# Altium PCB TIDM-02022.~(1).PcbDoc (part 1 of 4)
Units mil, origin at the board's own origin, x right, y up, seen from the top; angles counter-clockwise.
Board outline 1448.82 x 2299.21 mil, 16 copper layers (Top Layer, GND1, PWR1, PWR2, PWR3, GND2, GND3/SIG1, SIG2, SIG3, GND3/SIG4, GND5, PWR4, PWR5, GND6, GND7, Bottom Layer), stack 148.806 mil thick; 257 components, 138 nets, 739 pads, 1147 vias.

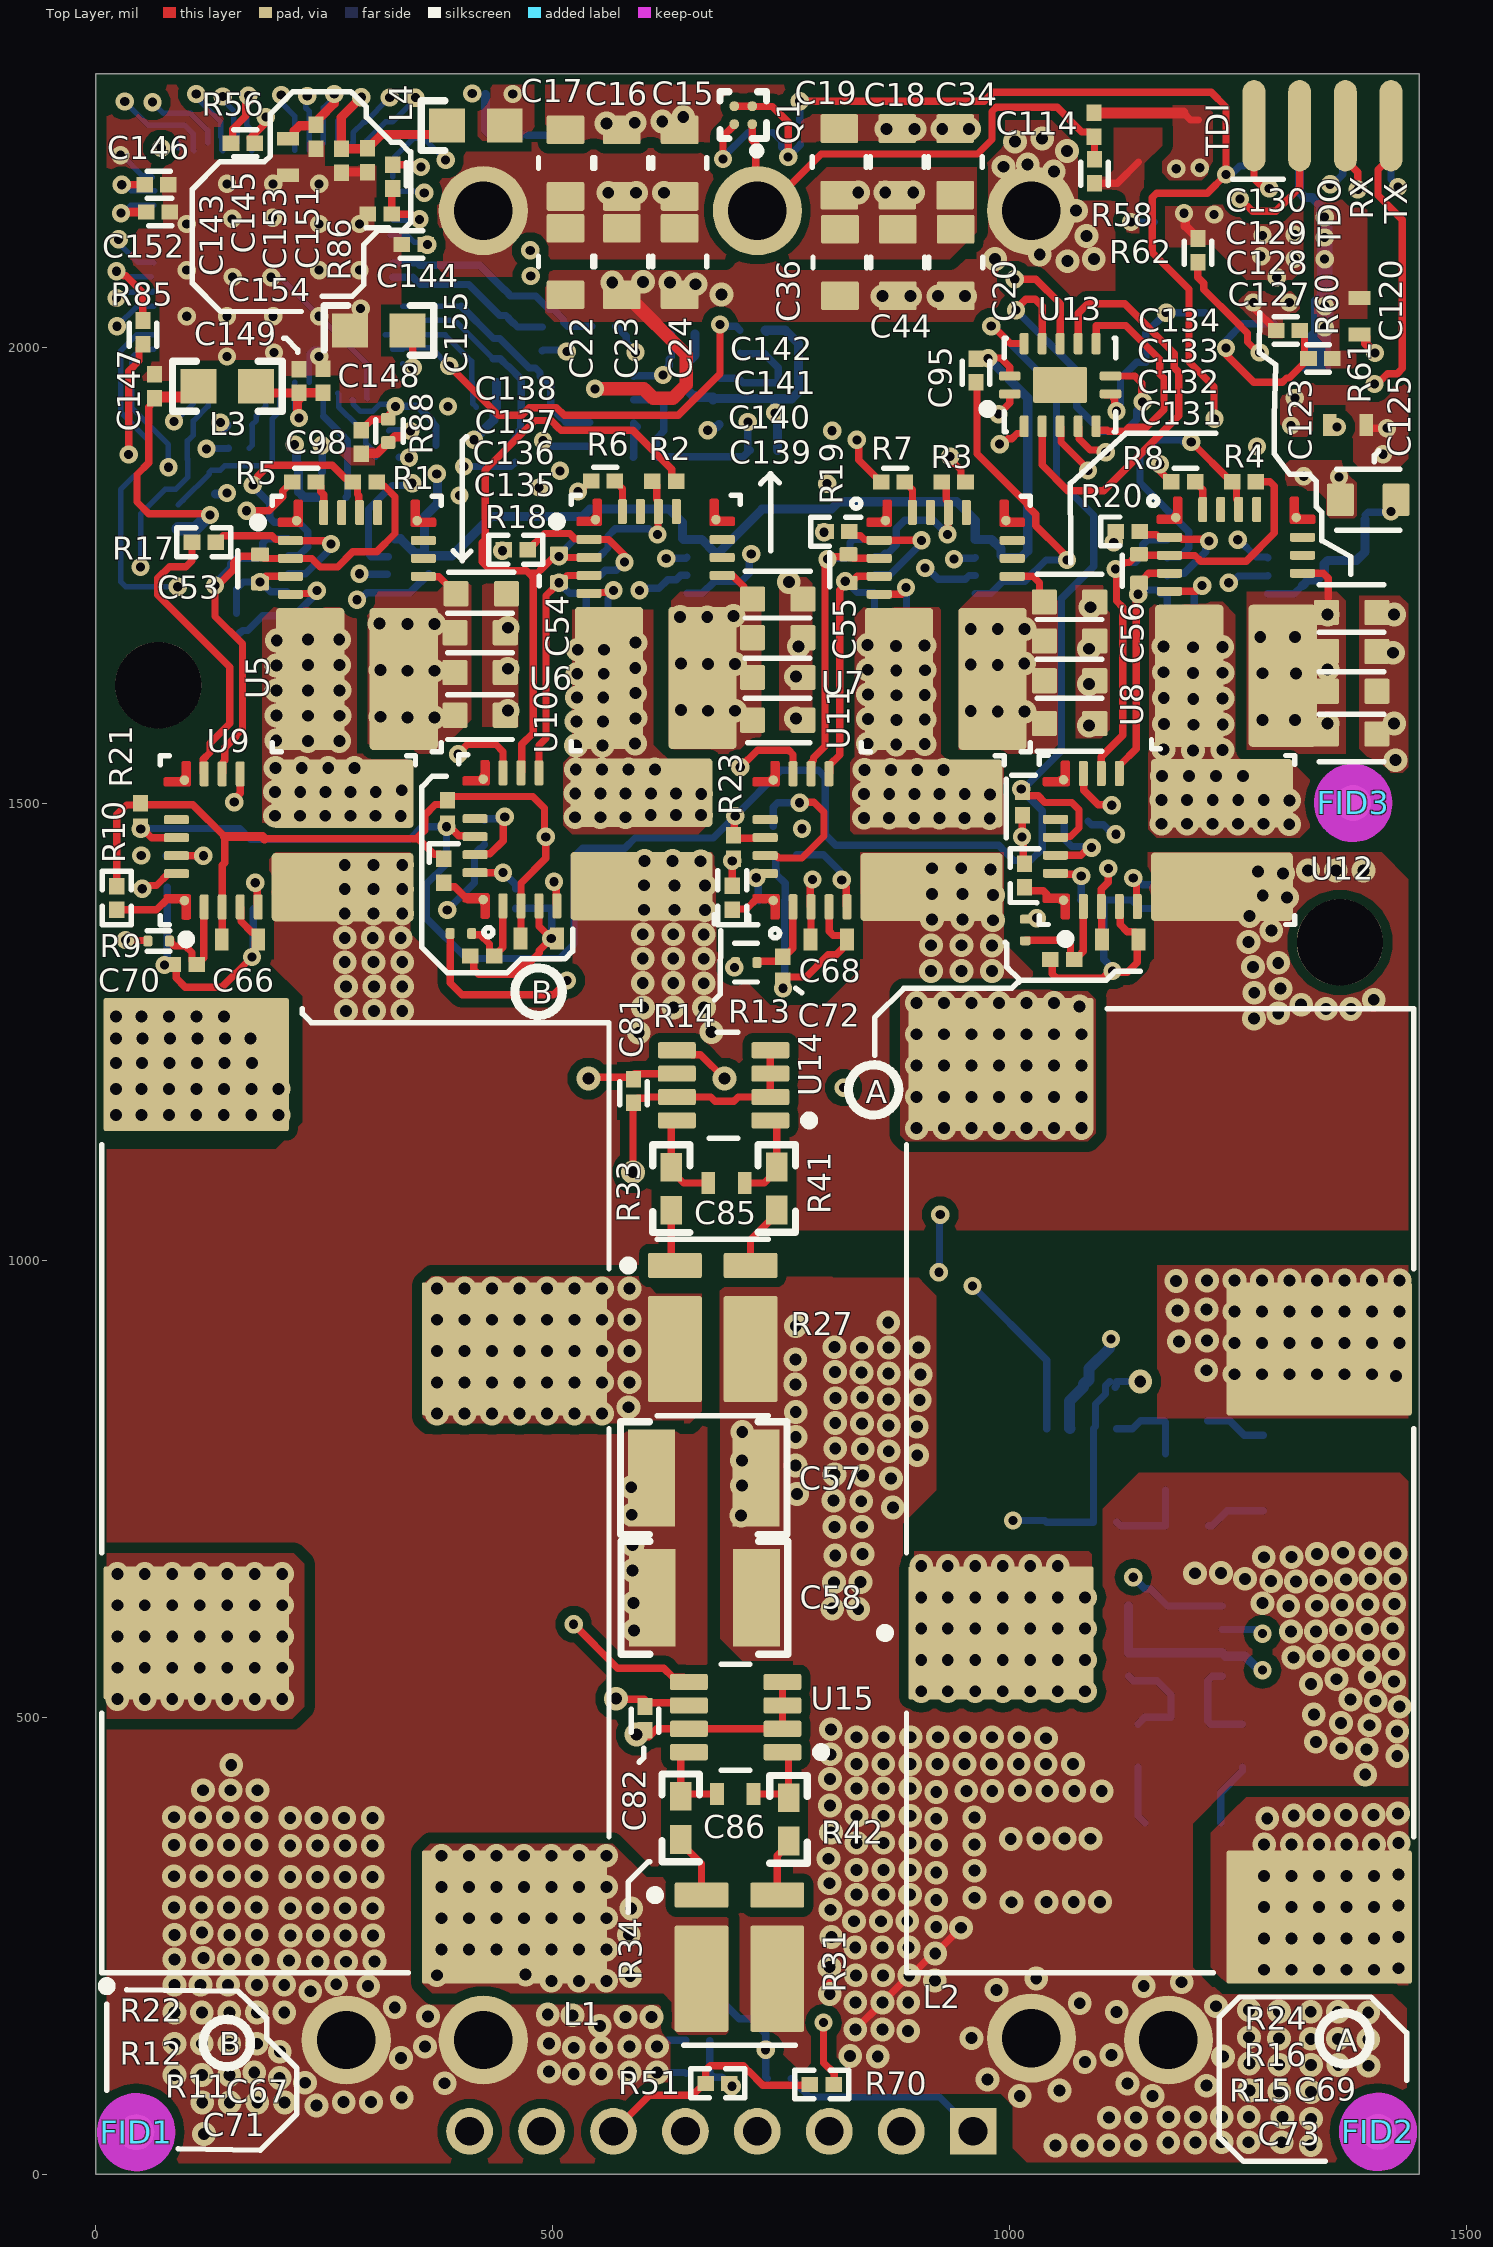
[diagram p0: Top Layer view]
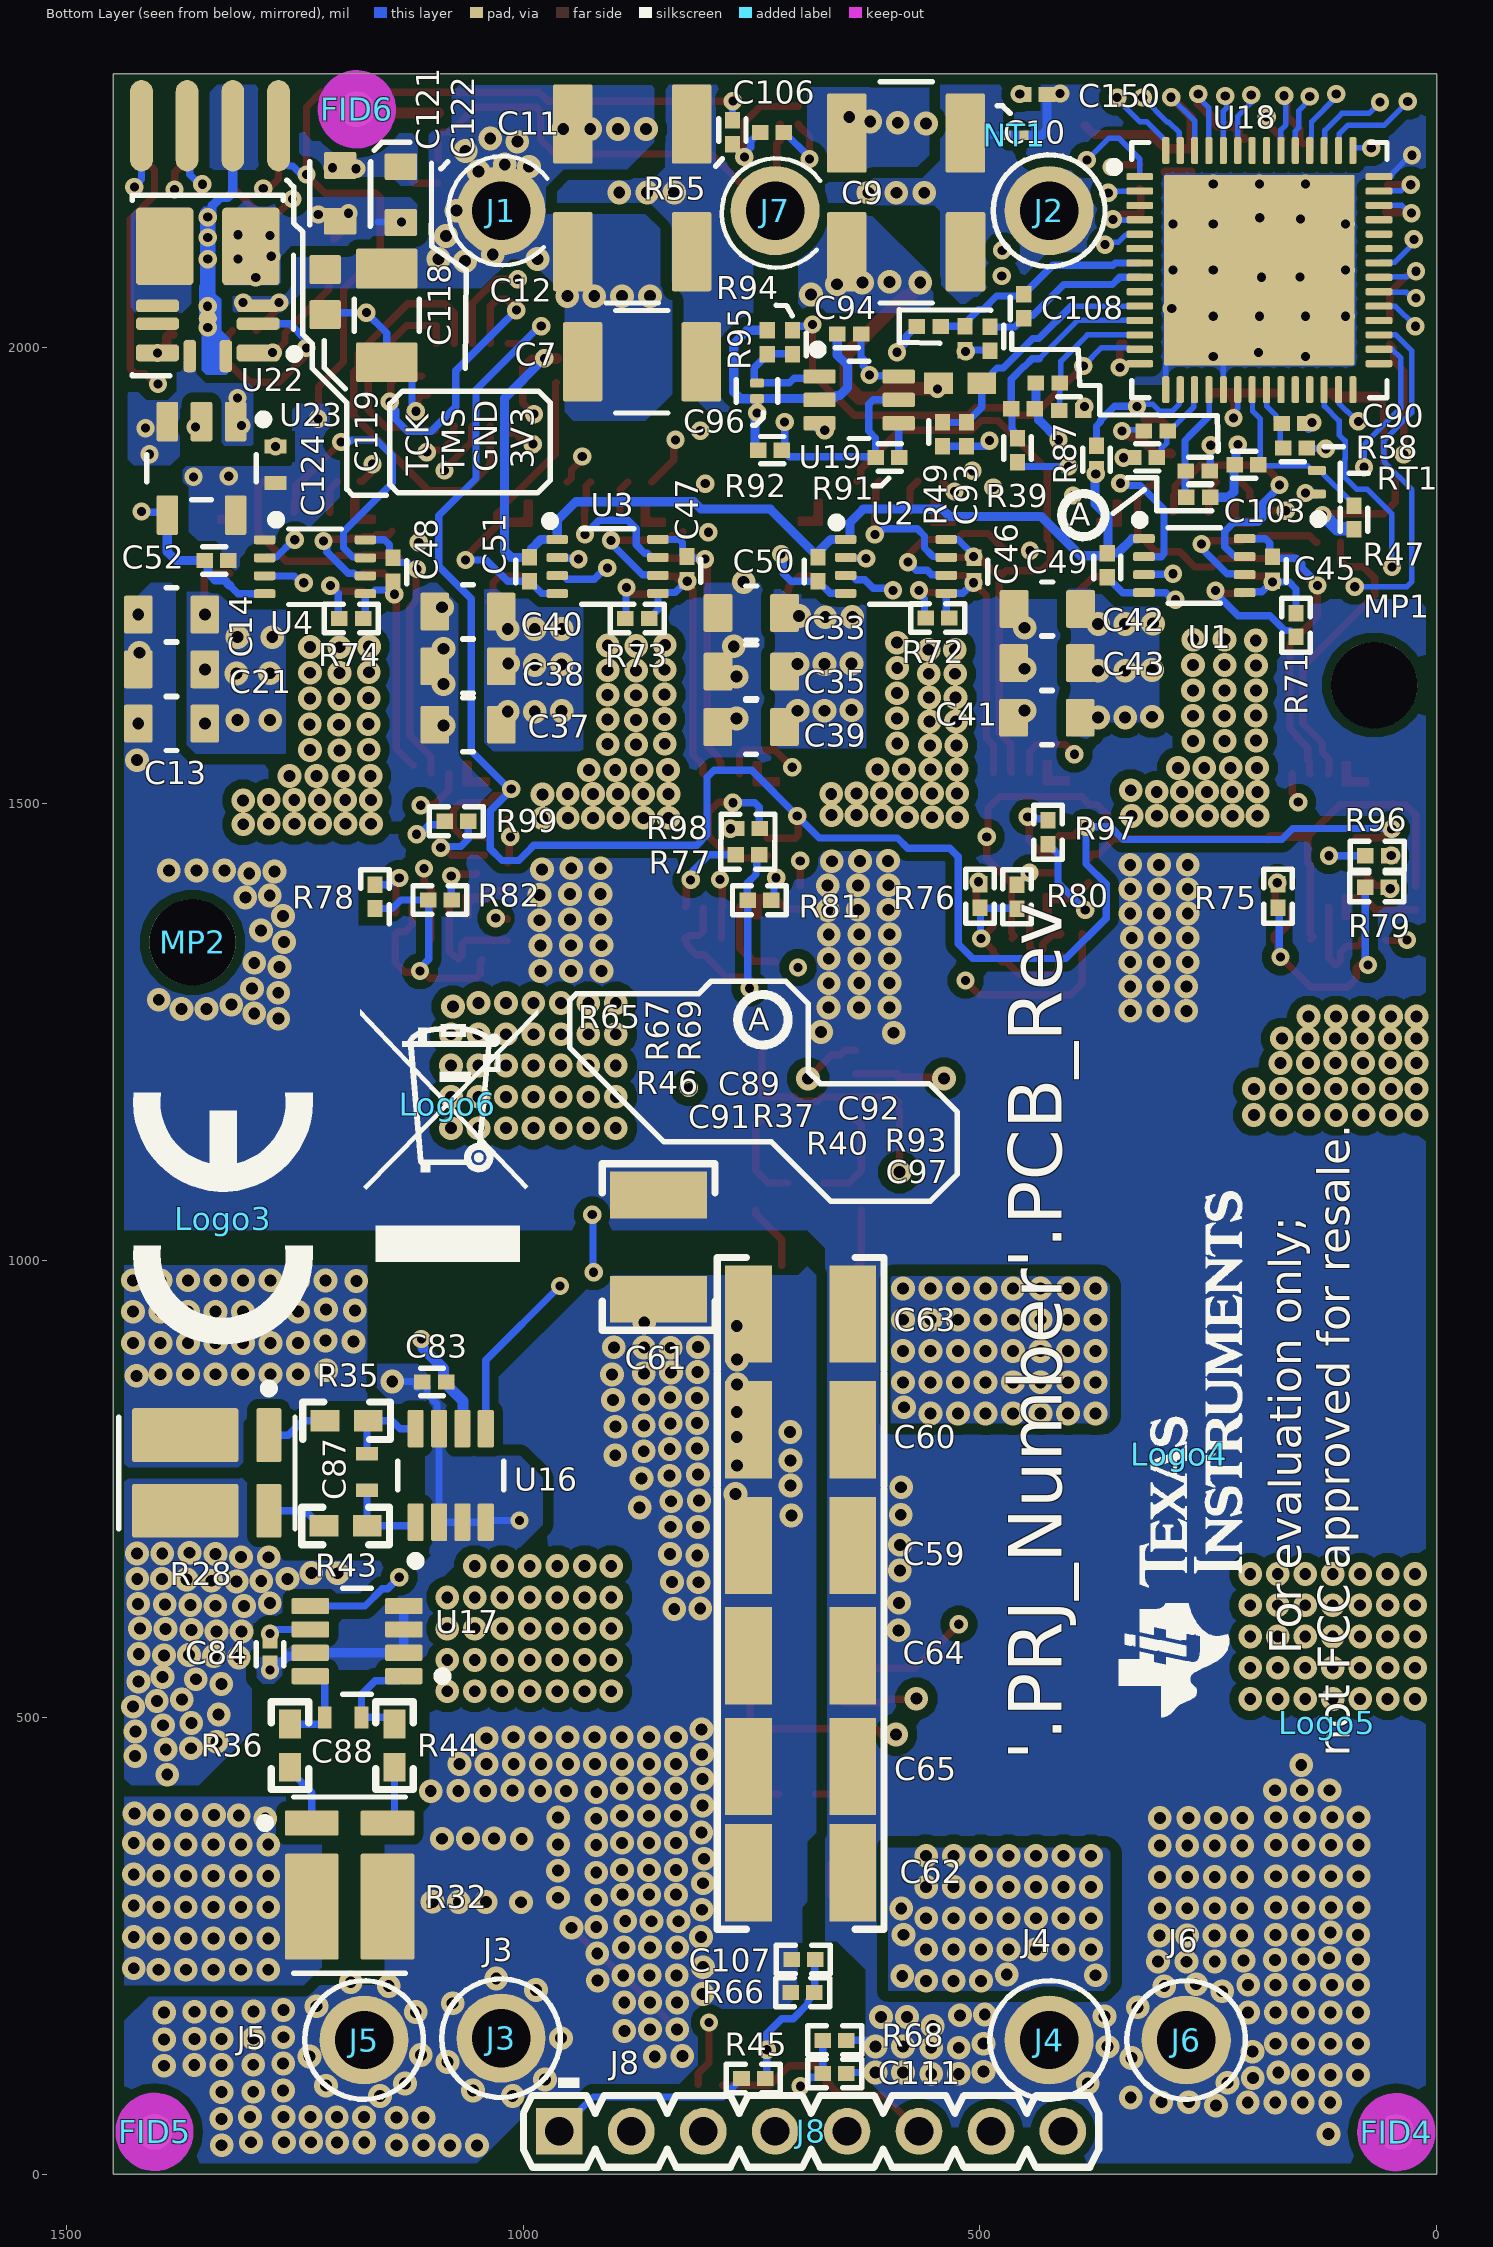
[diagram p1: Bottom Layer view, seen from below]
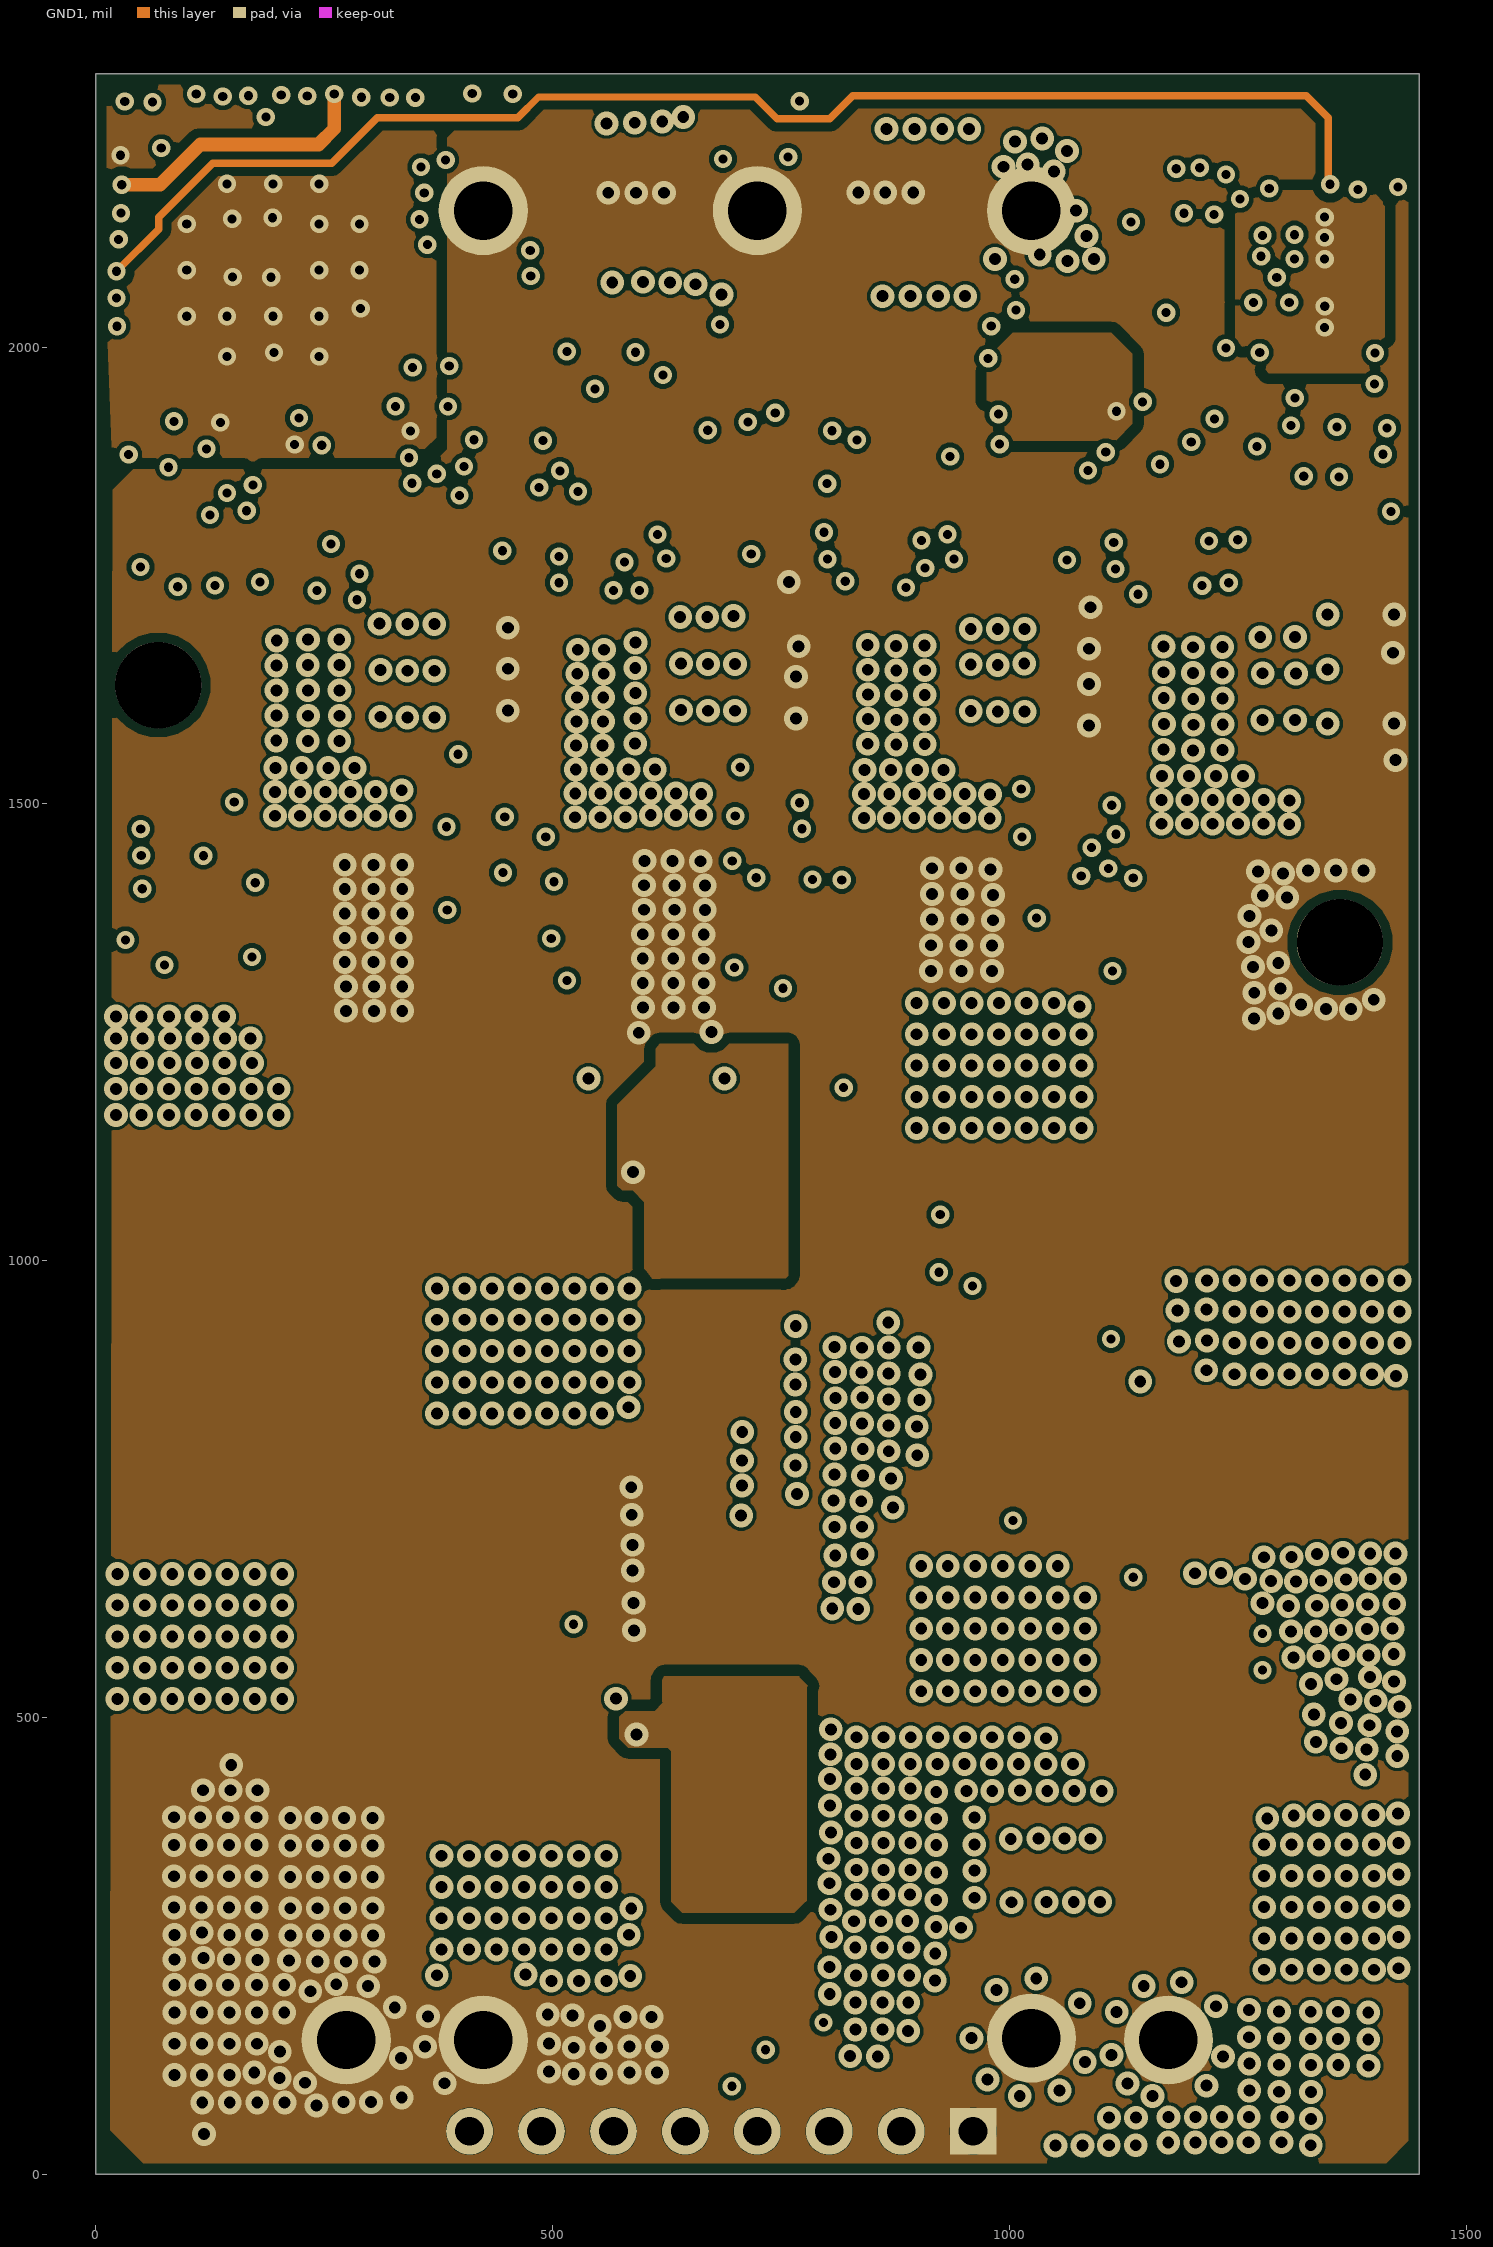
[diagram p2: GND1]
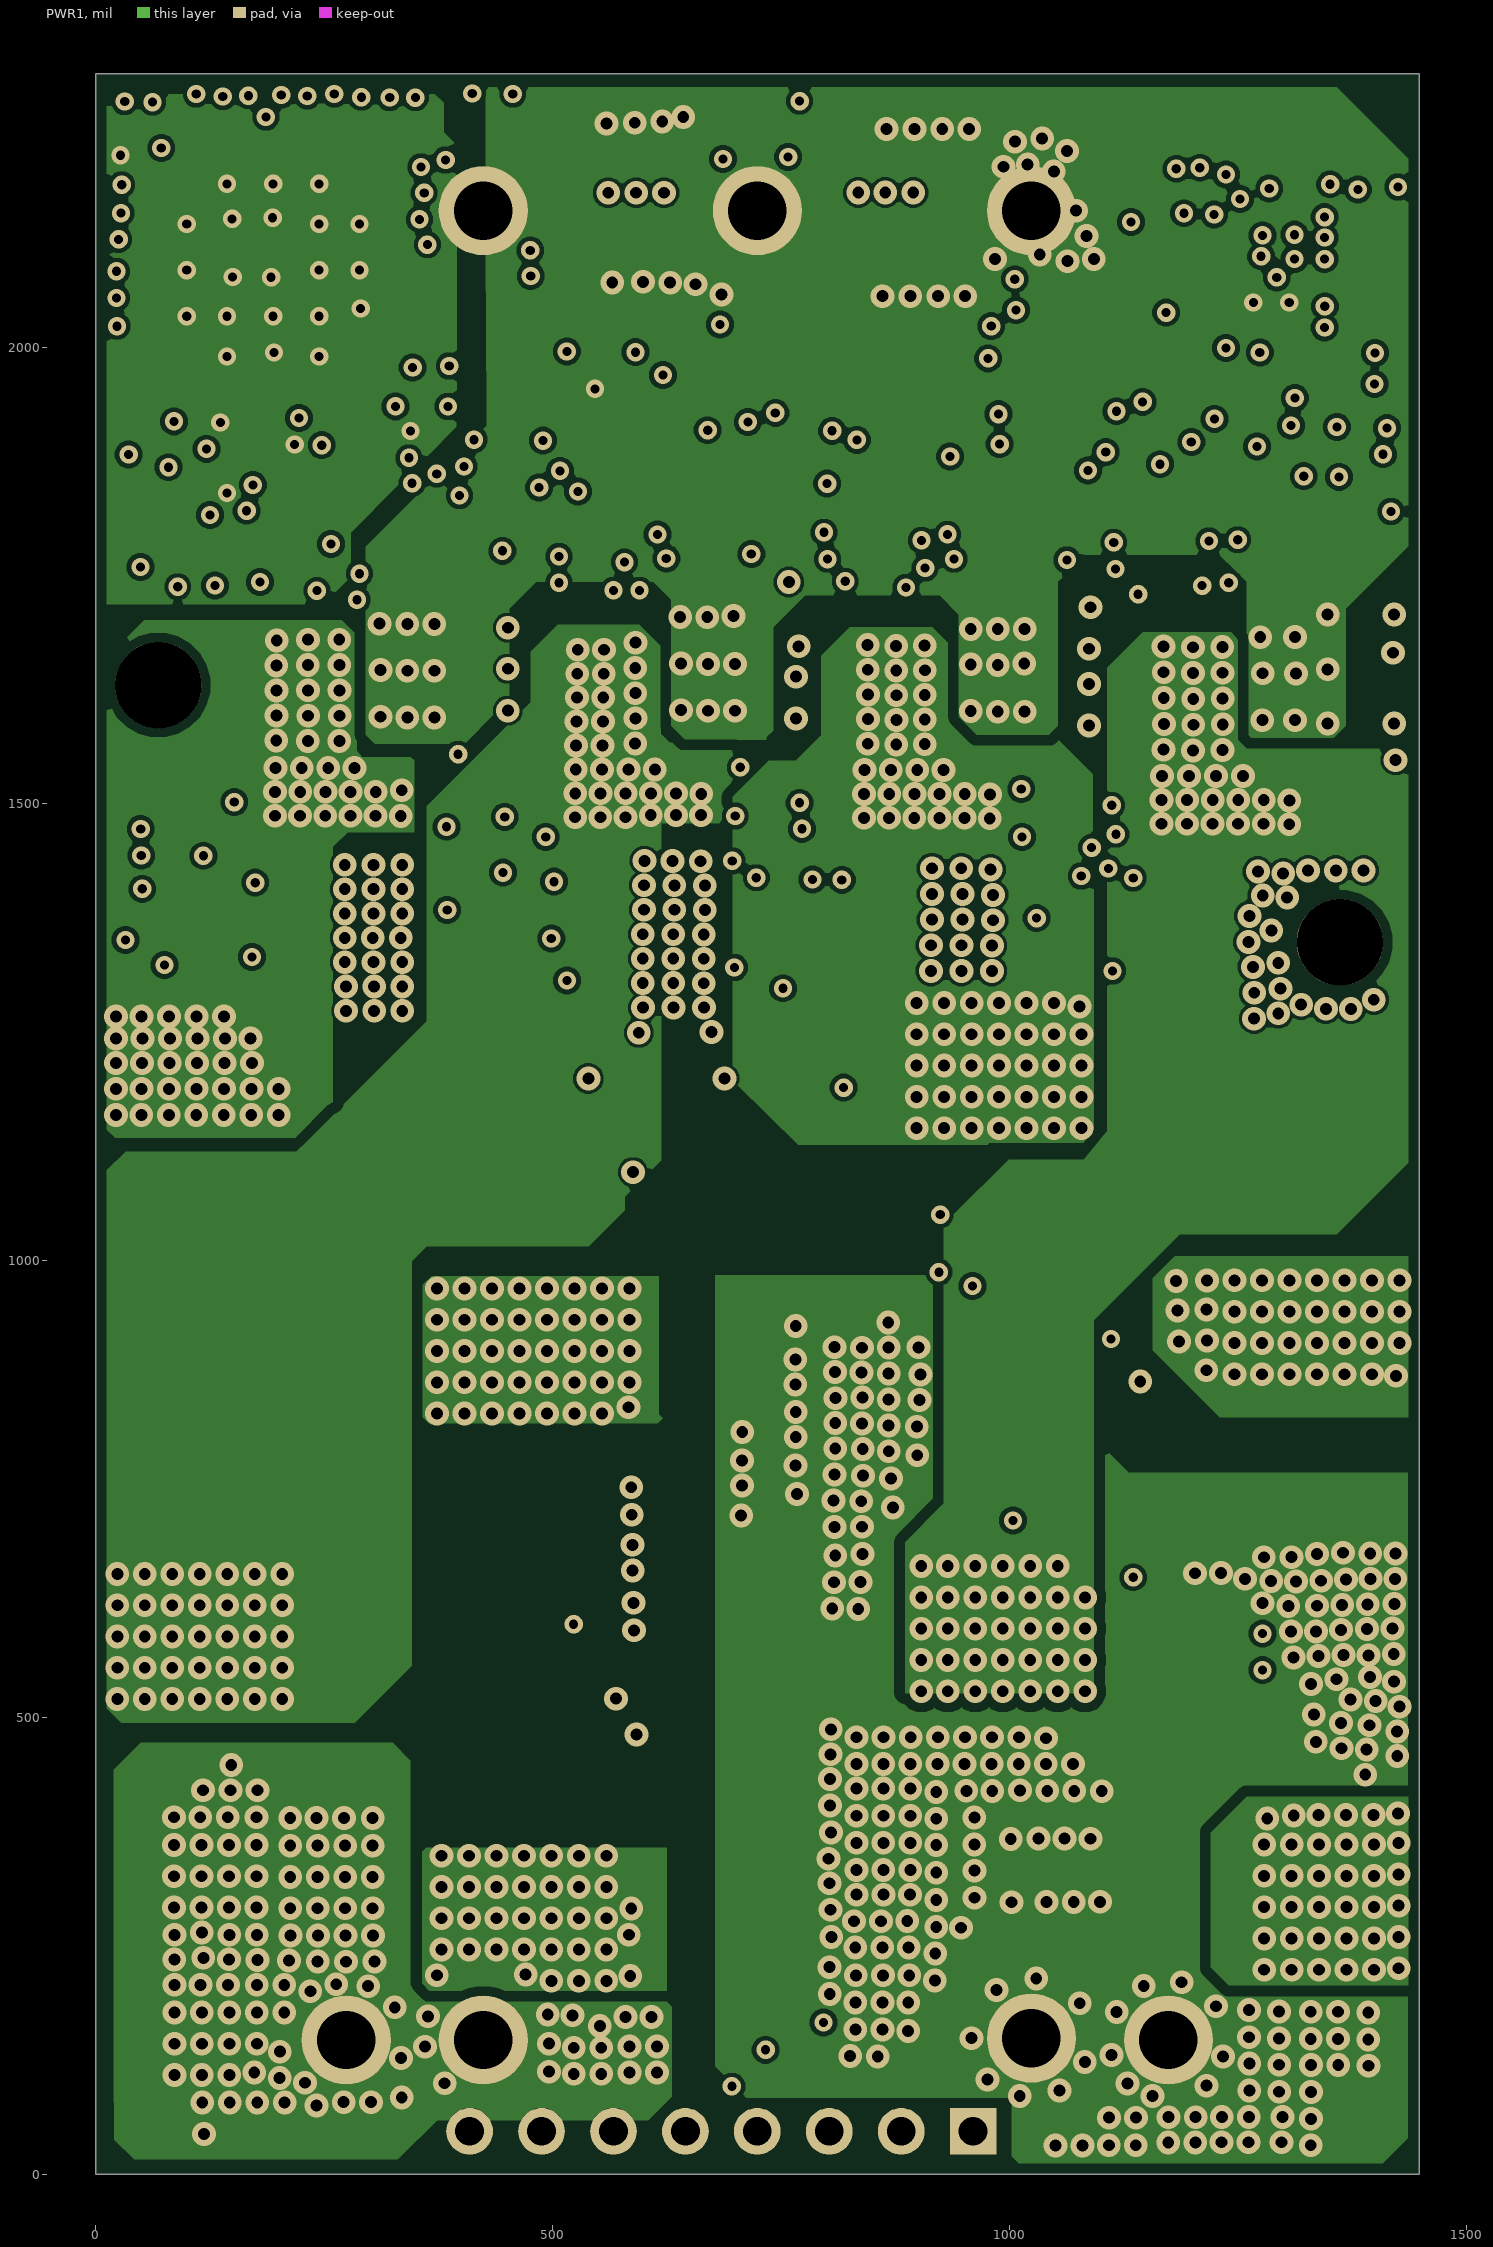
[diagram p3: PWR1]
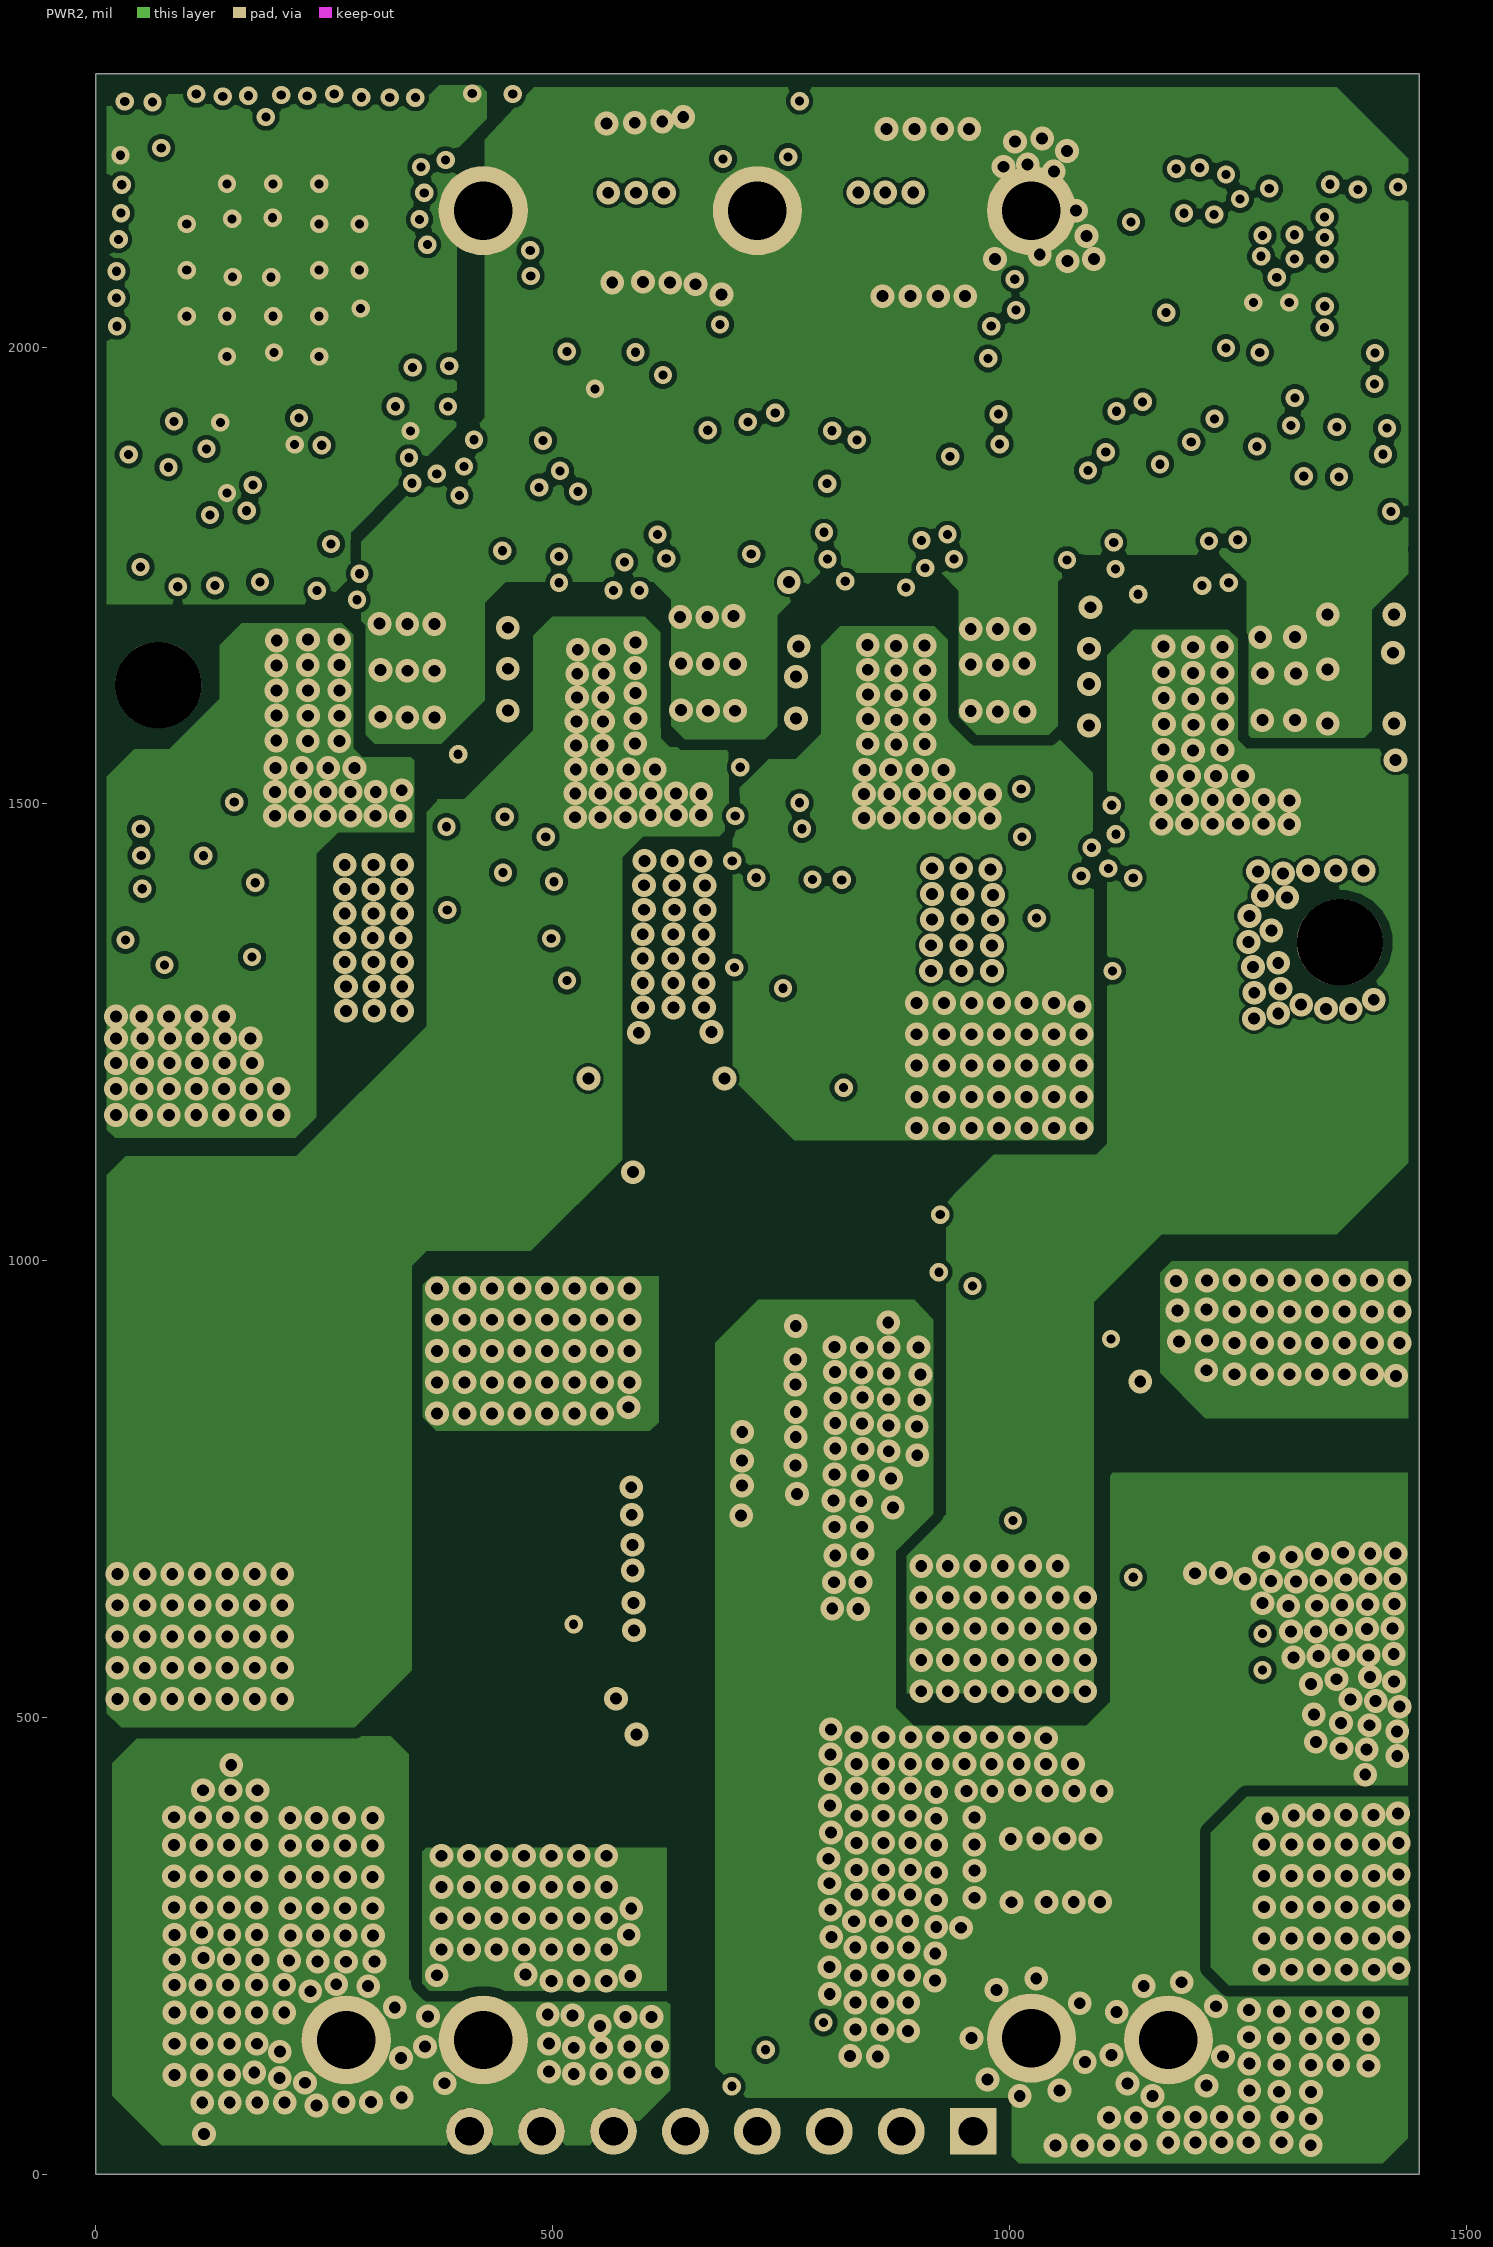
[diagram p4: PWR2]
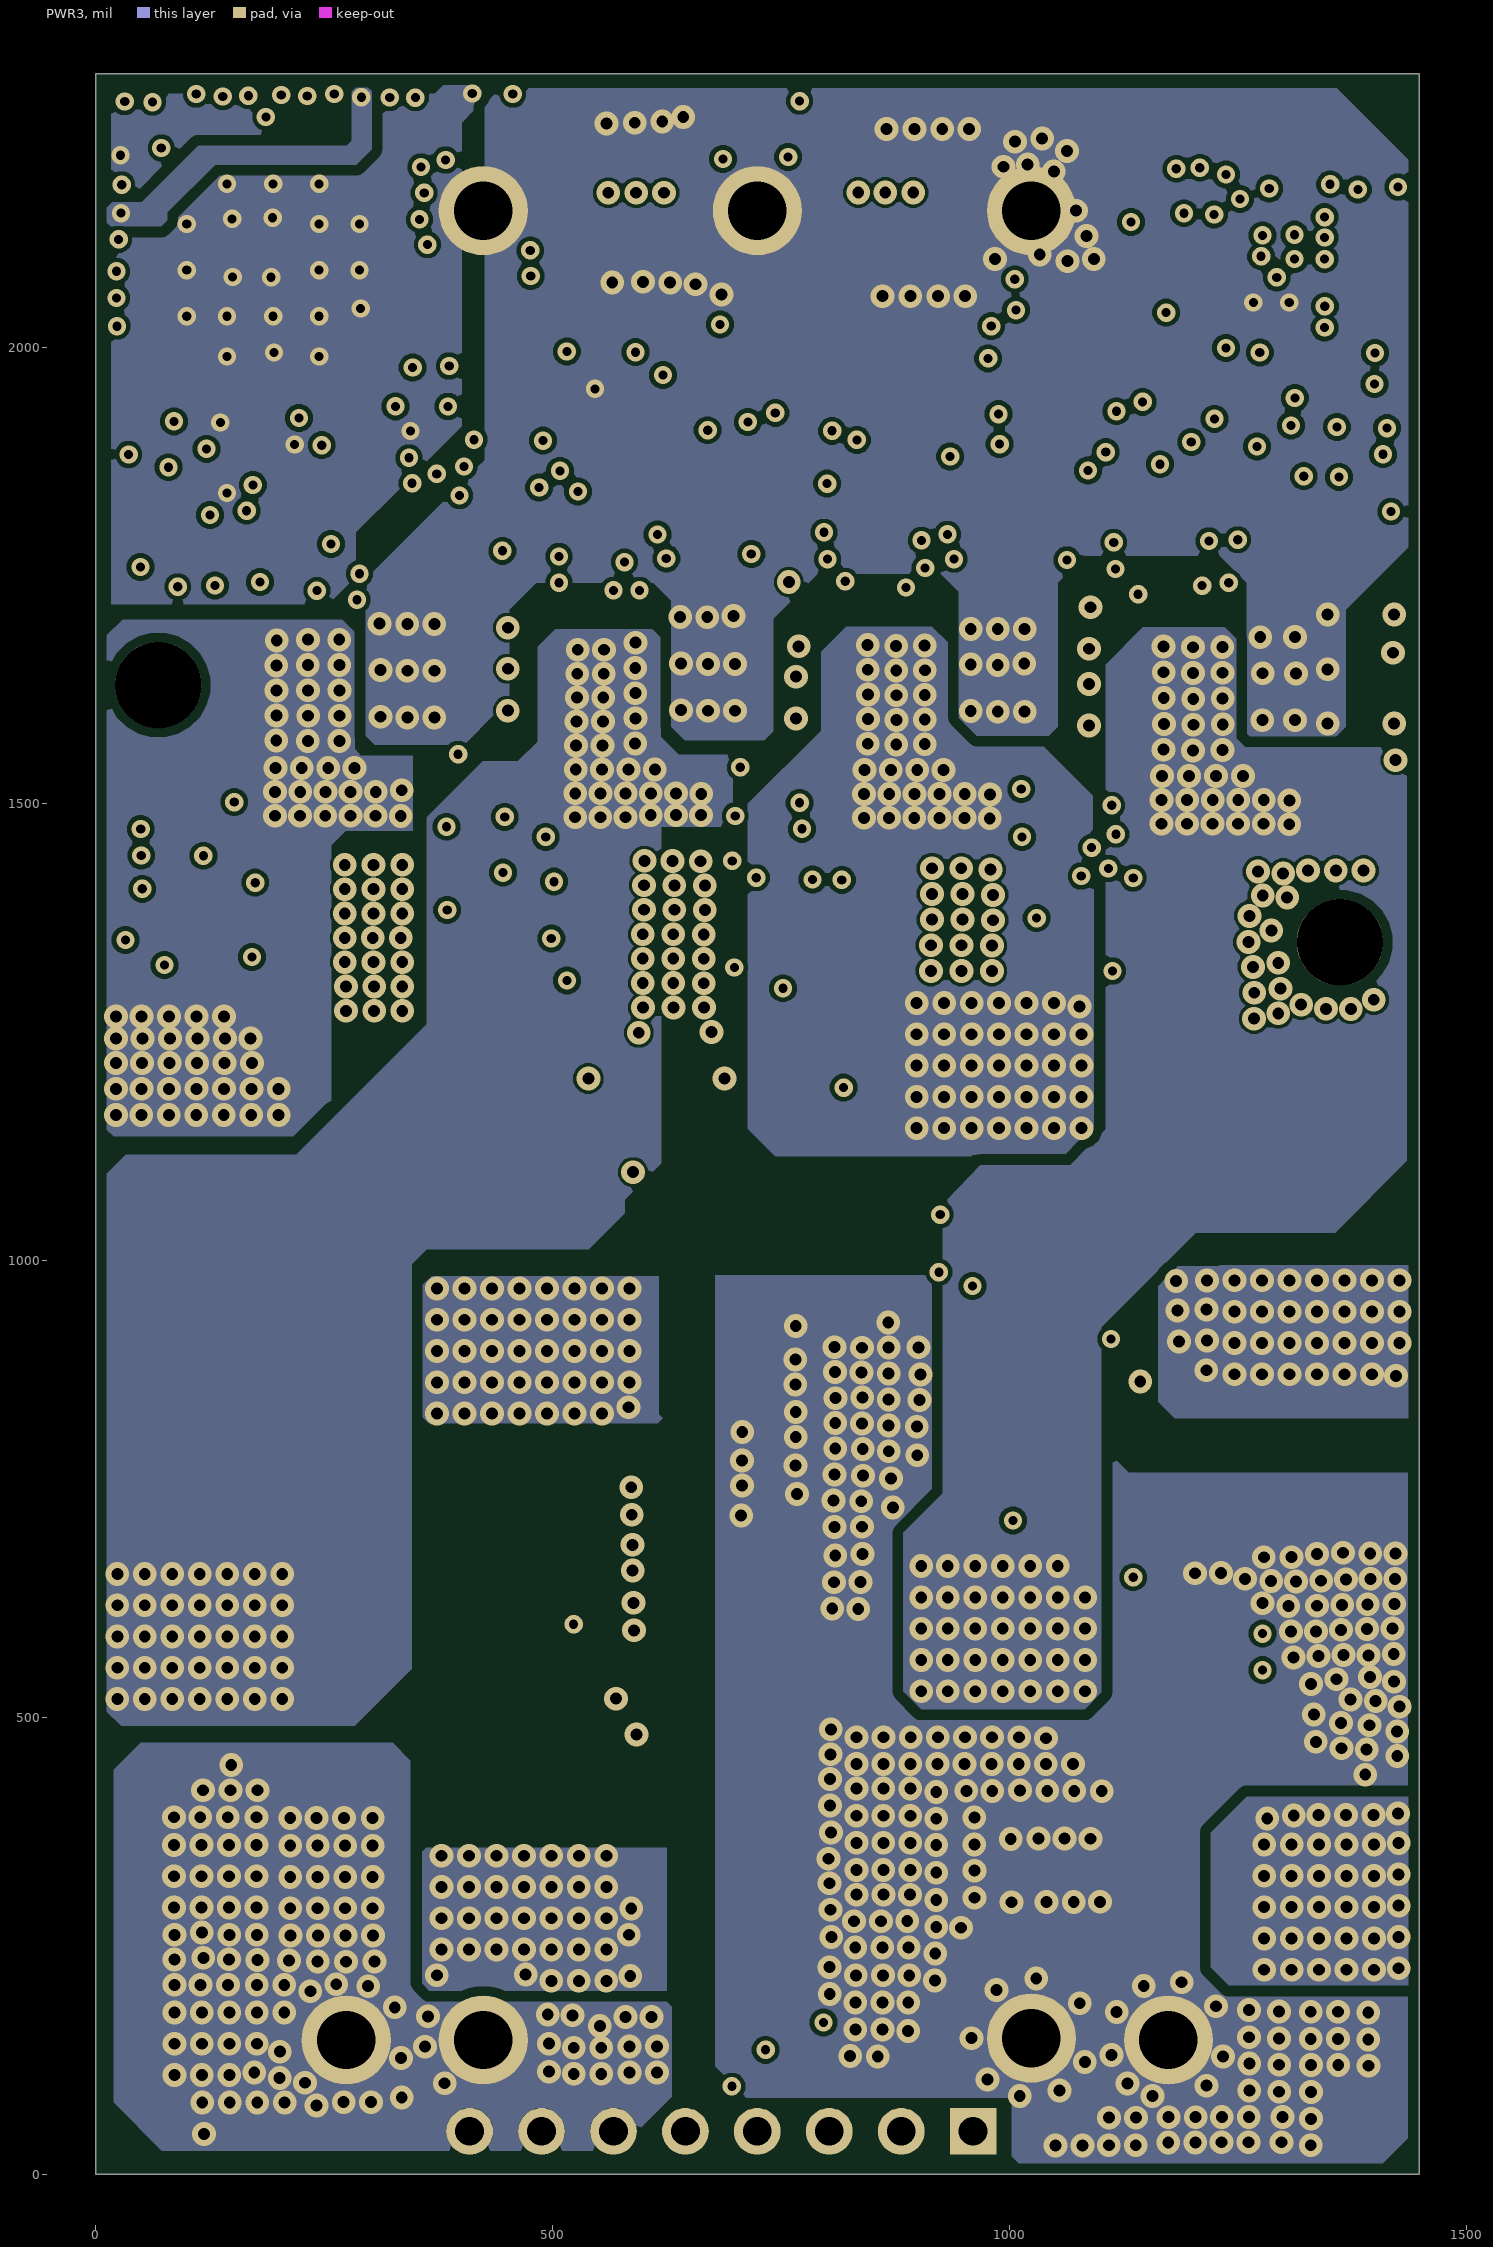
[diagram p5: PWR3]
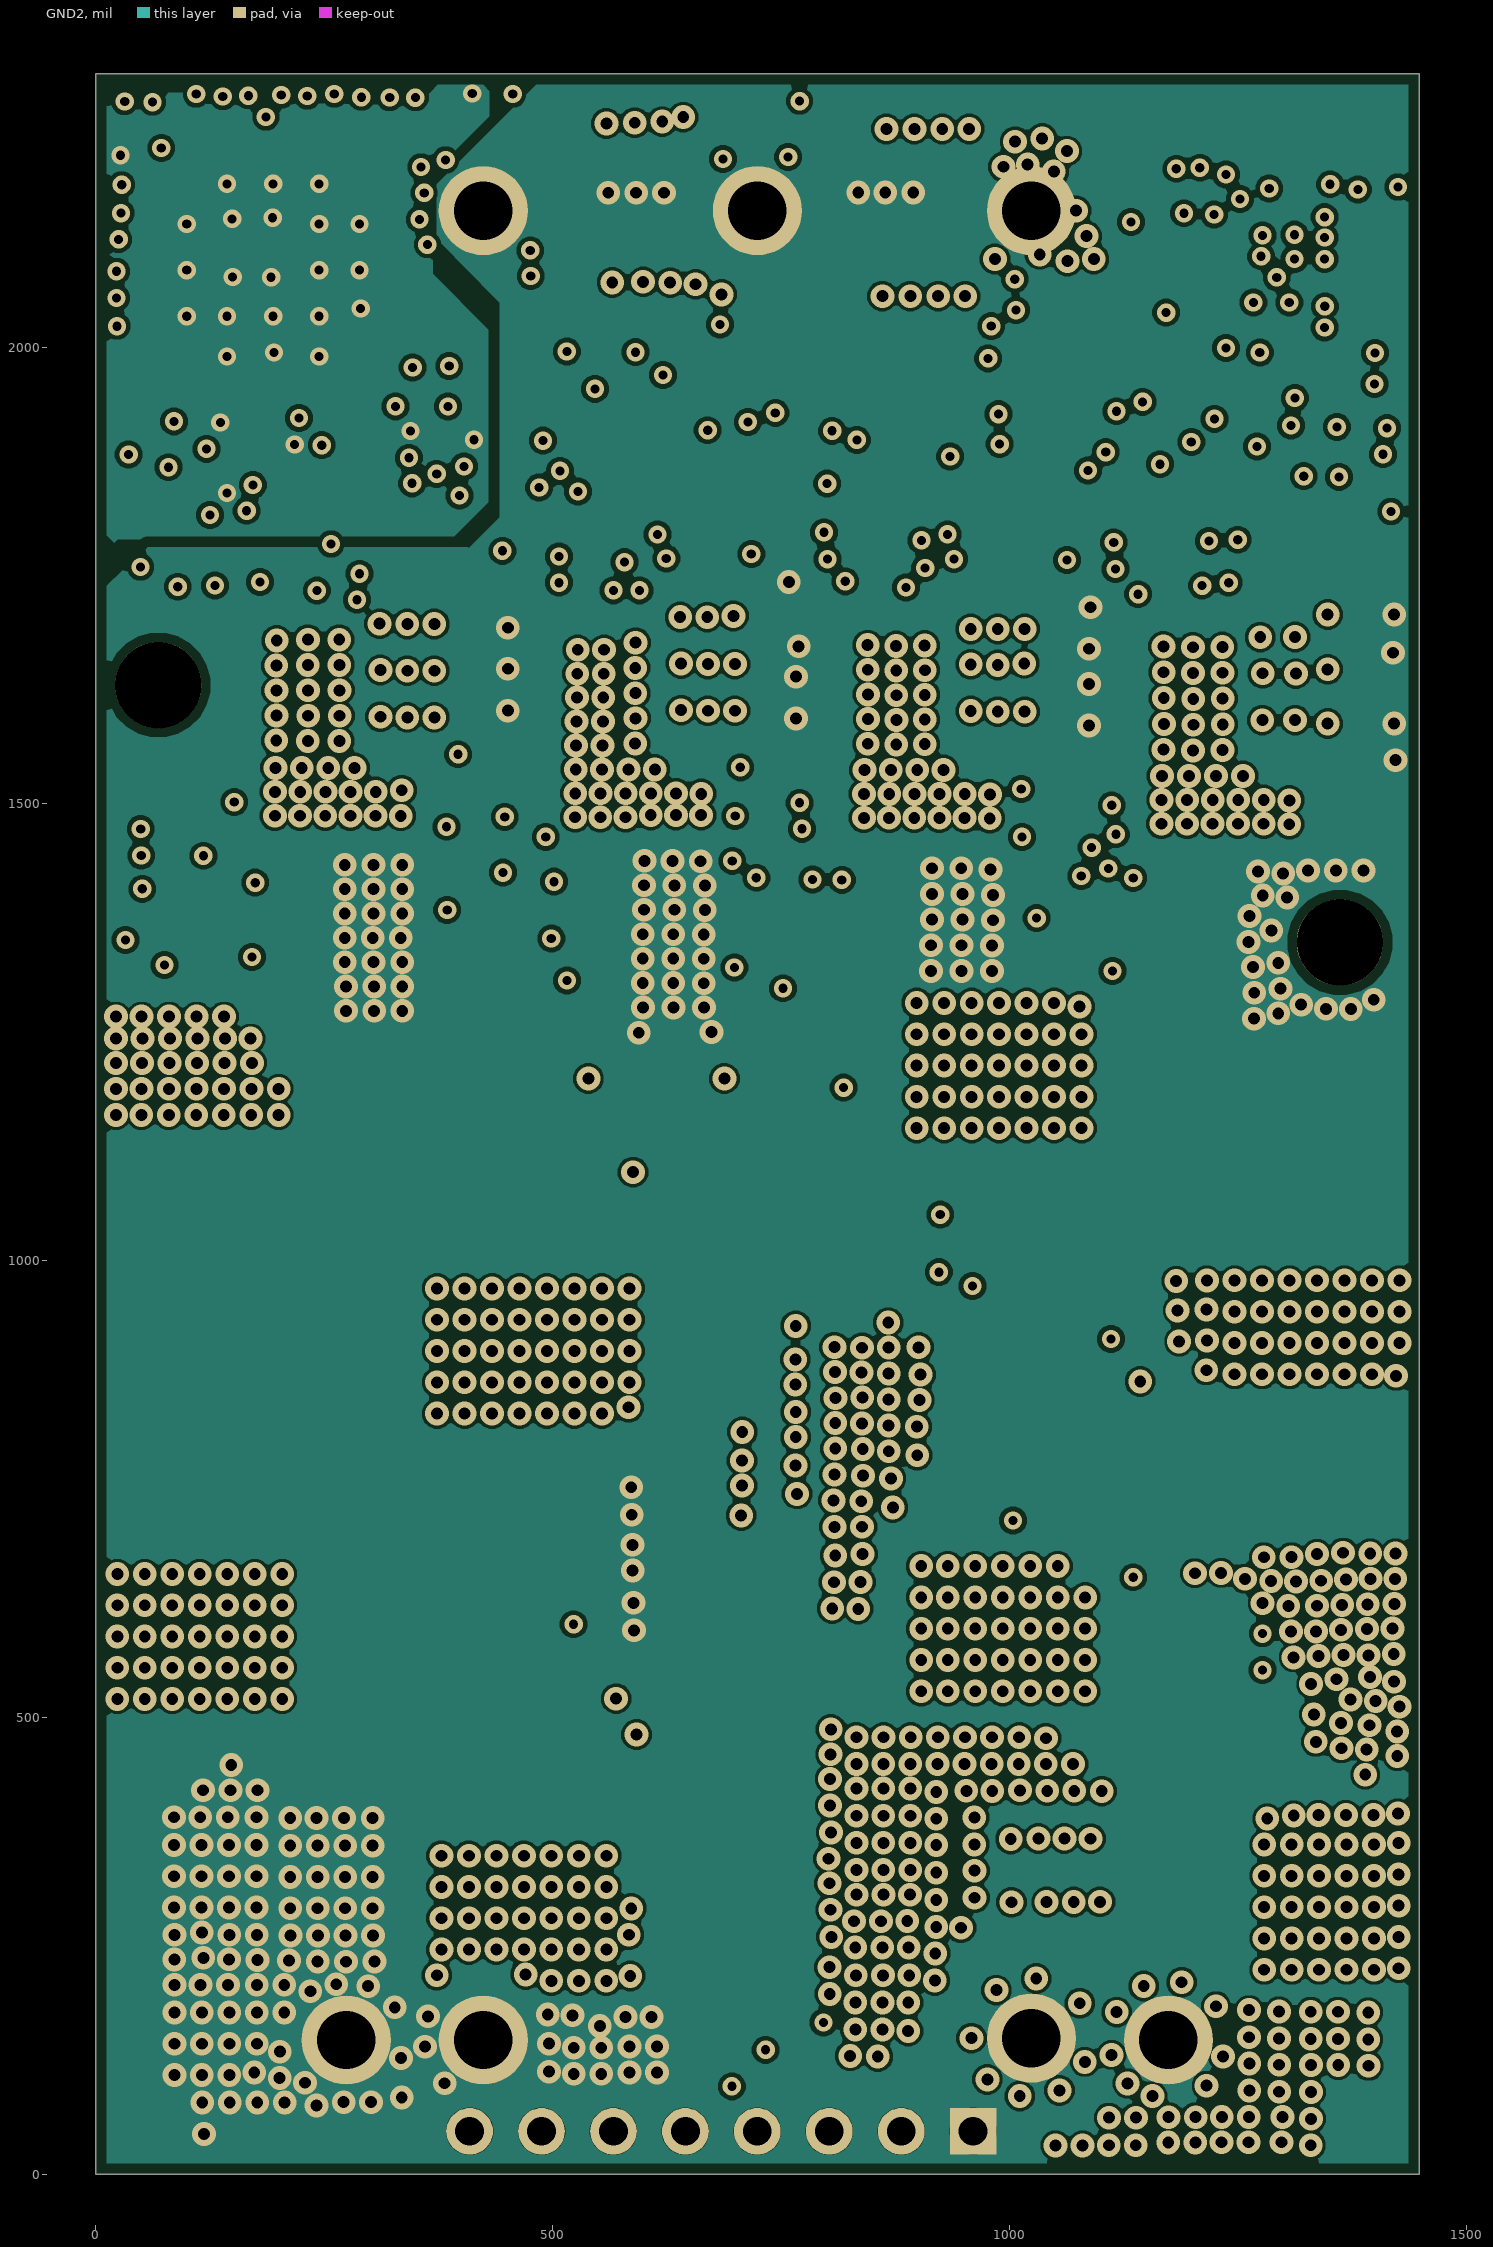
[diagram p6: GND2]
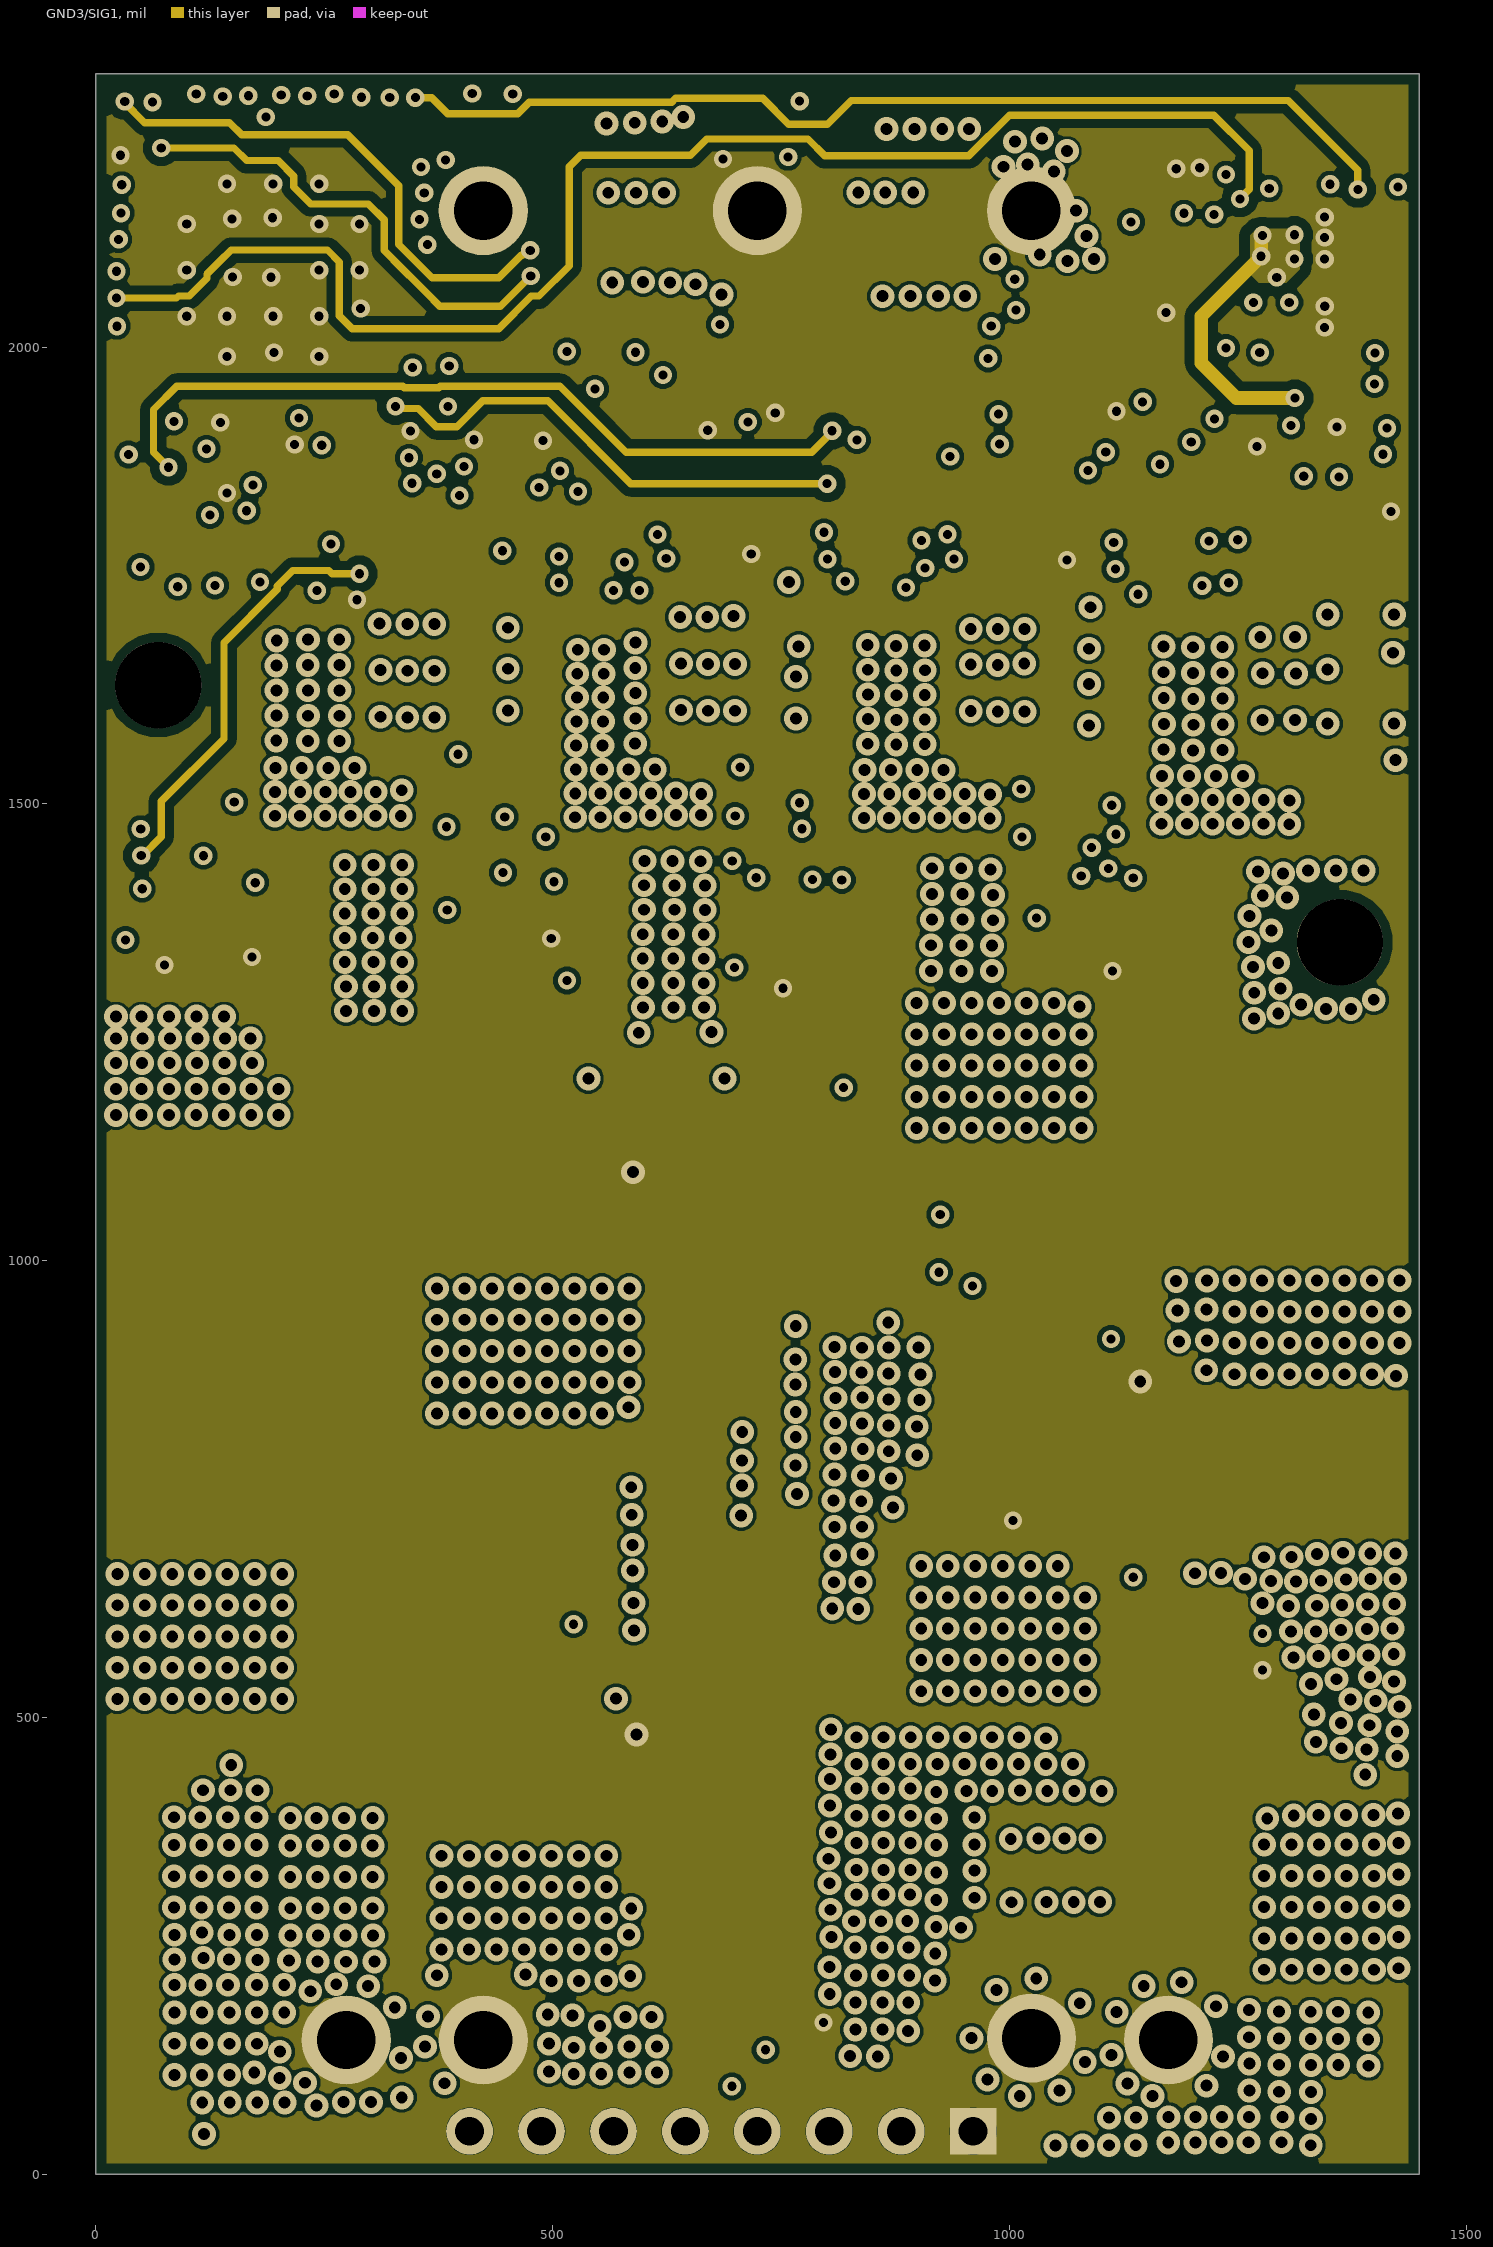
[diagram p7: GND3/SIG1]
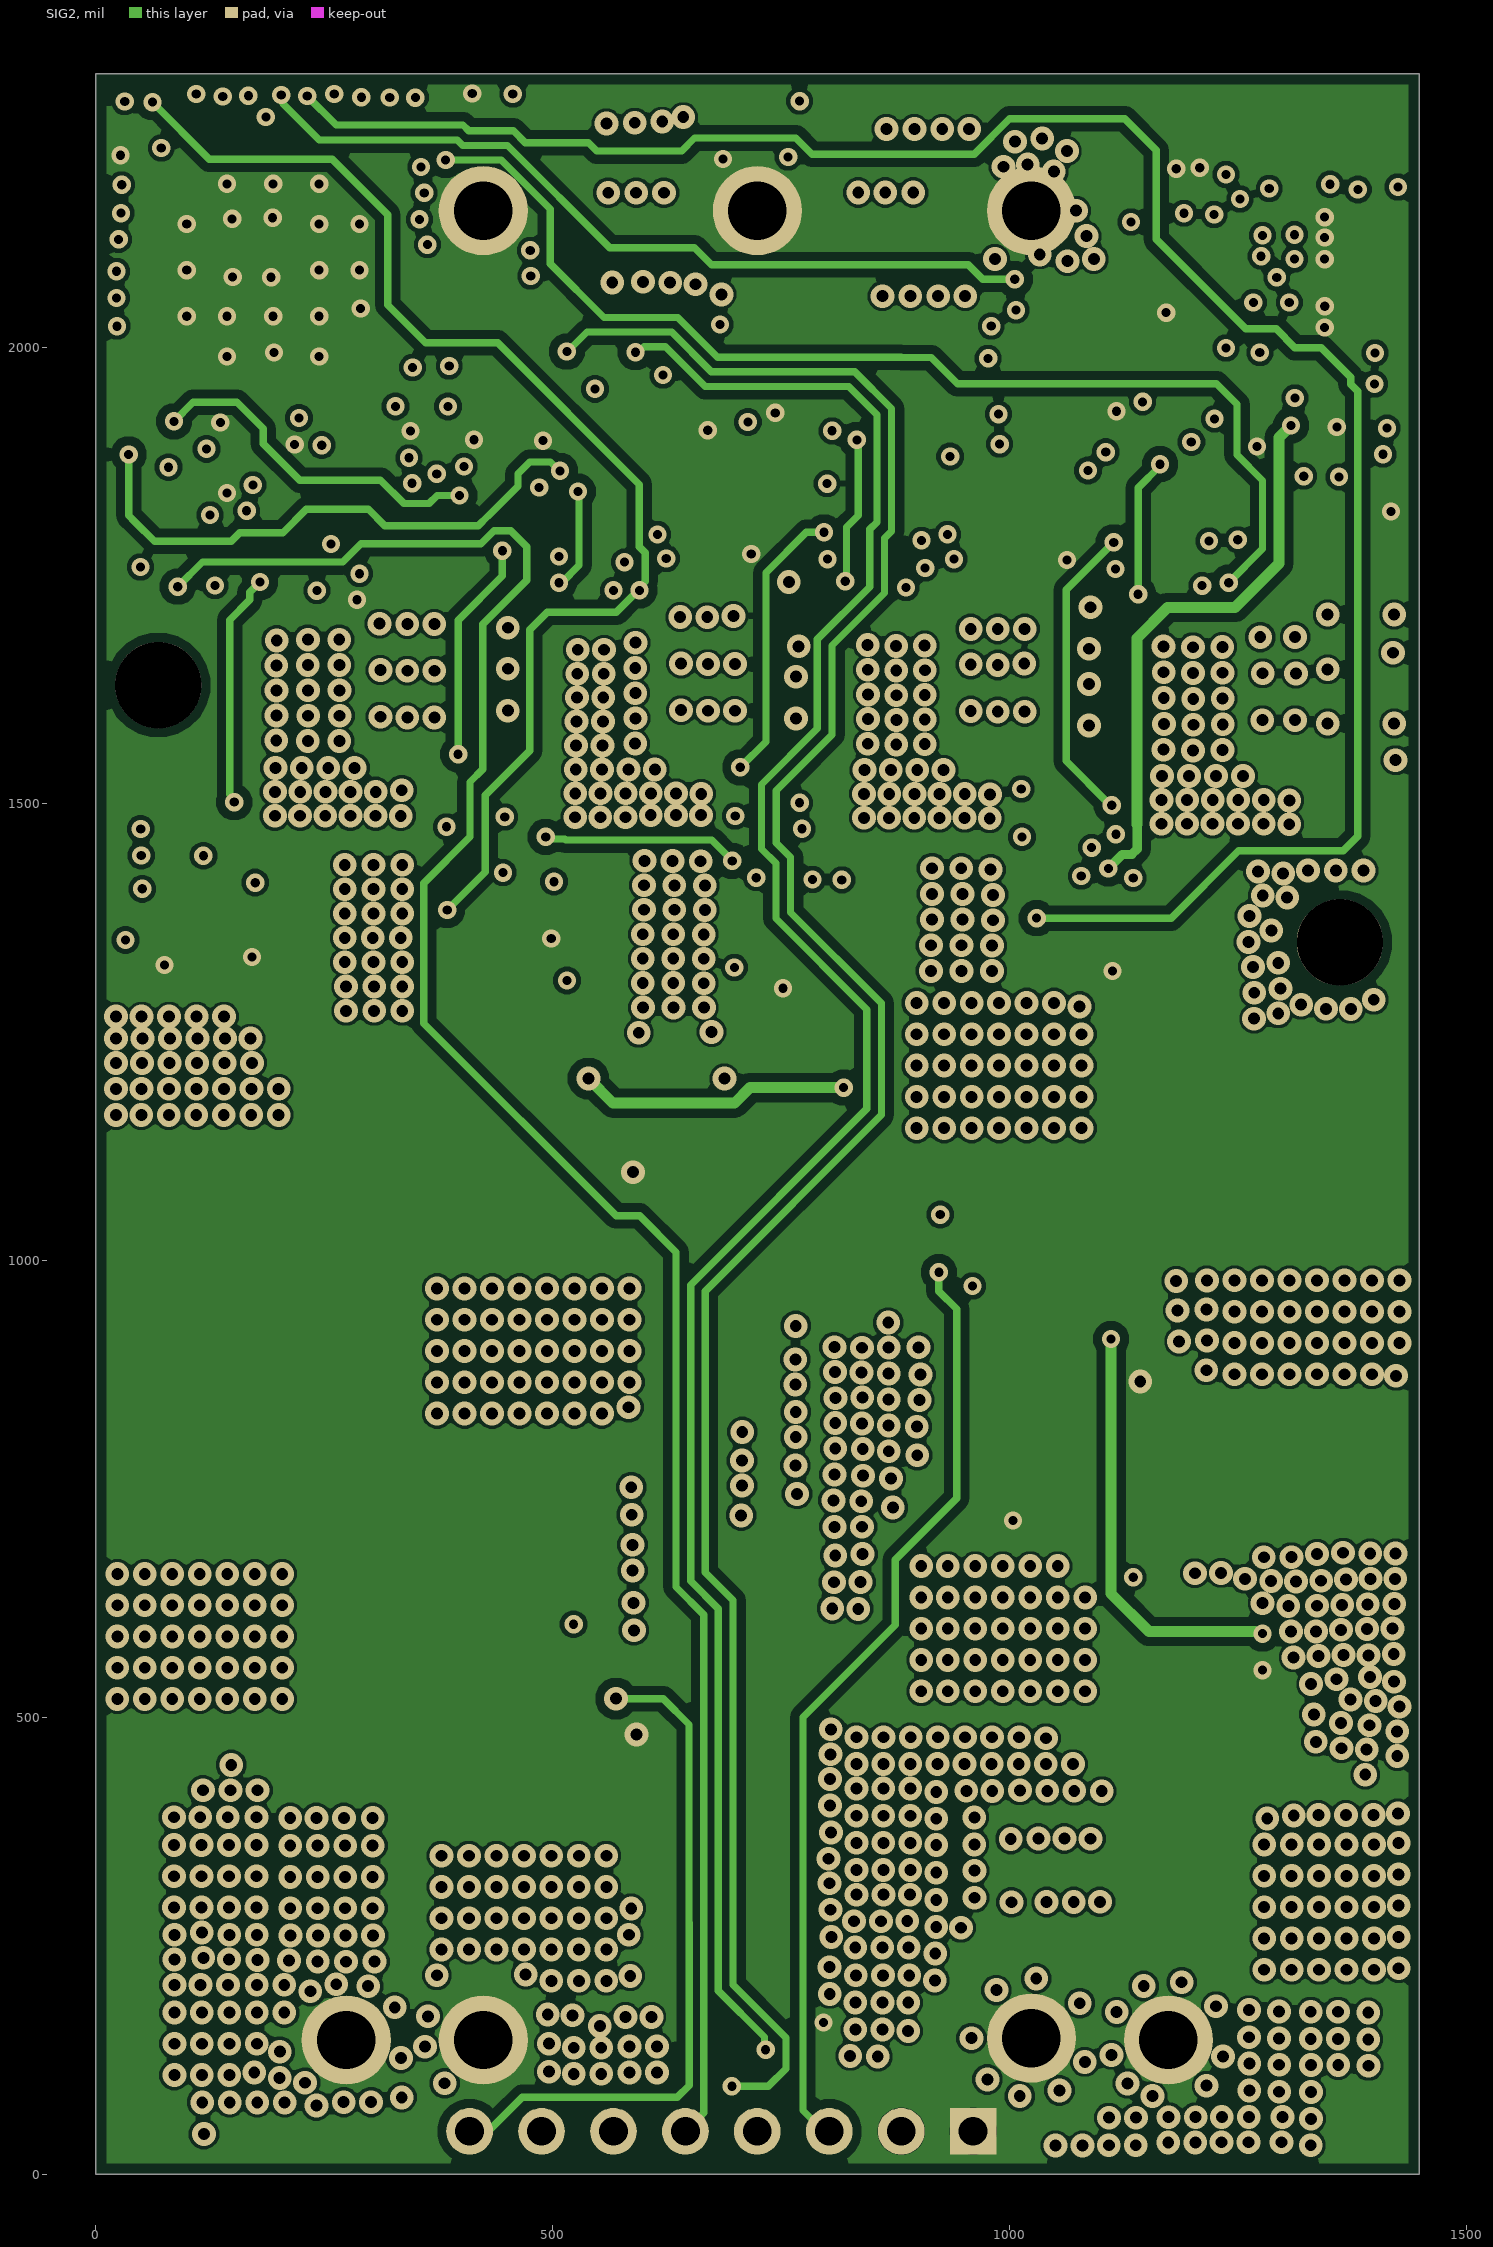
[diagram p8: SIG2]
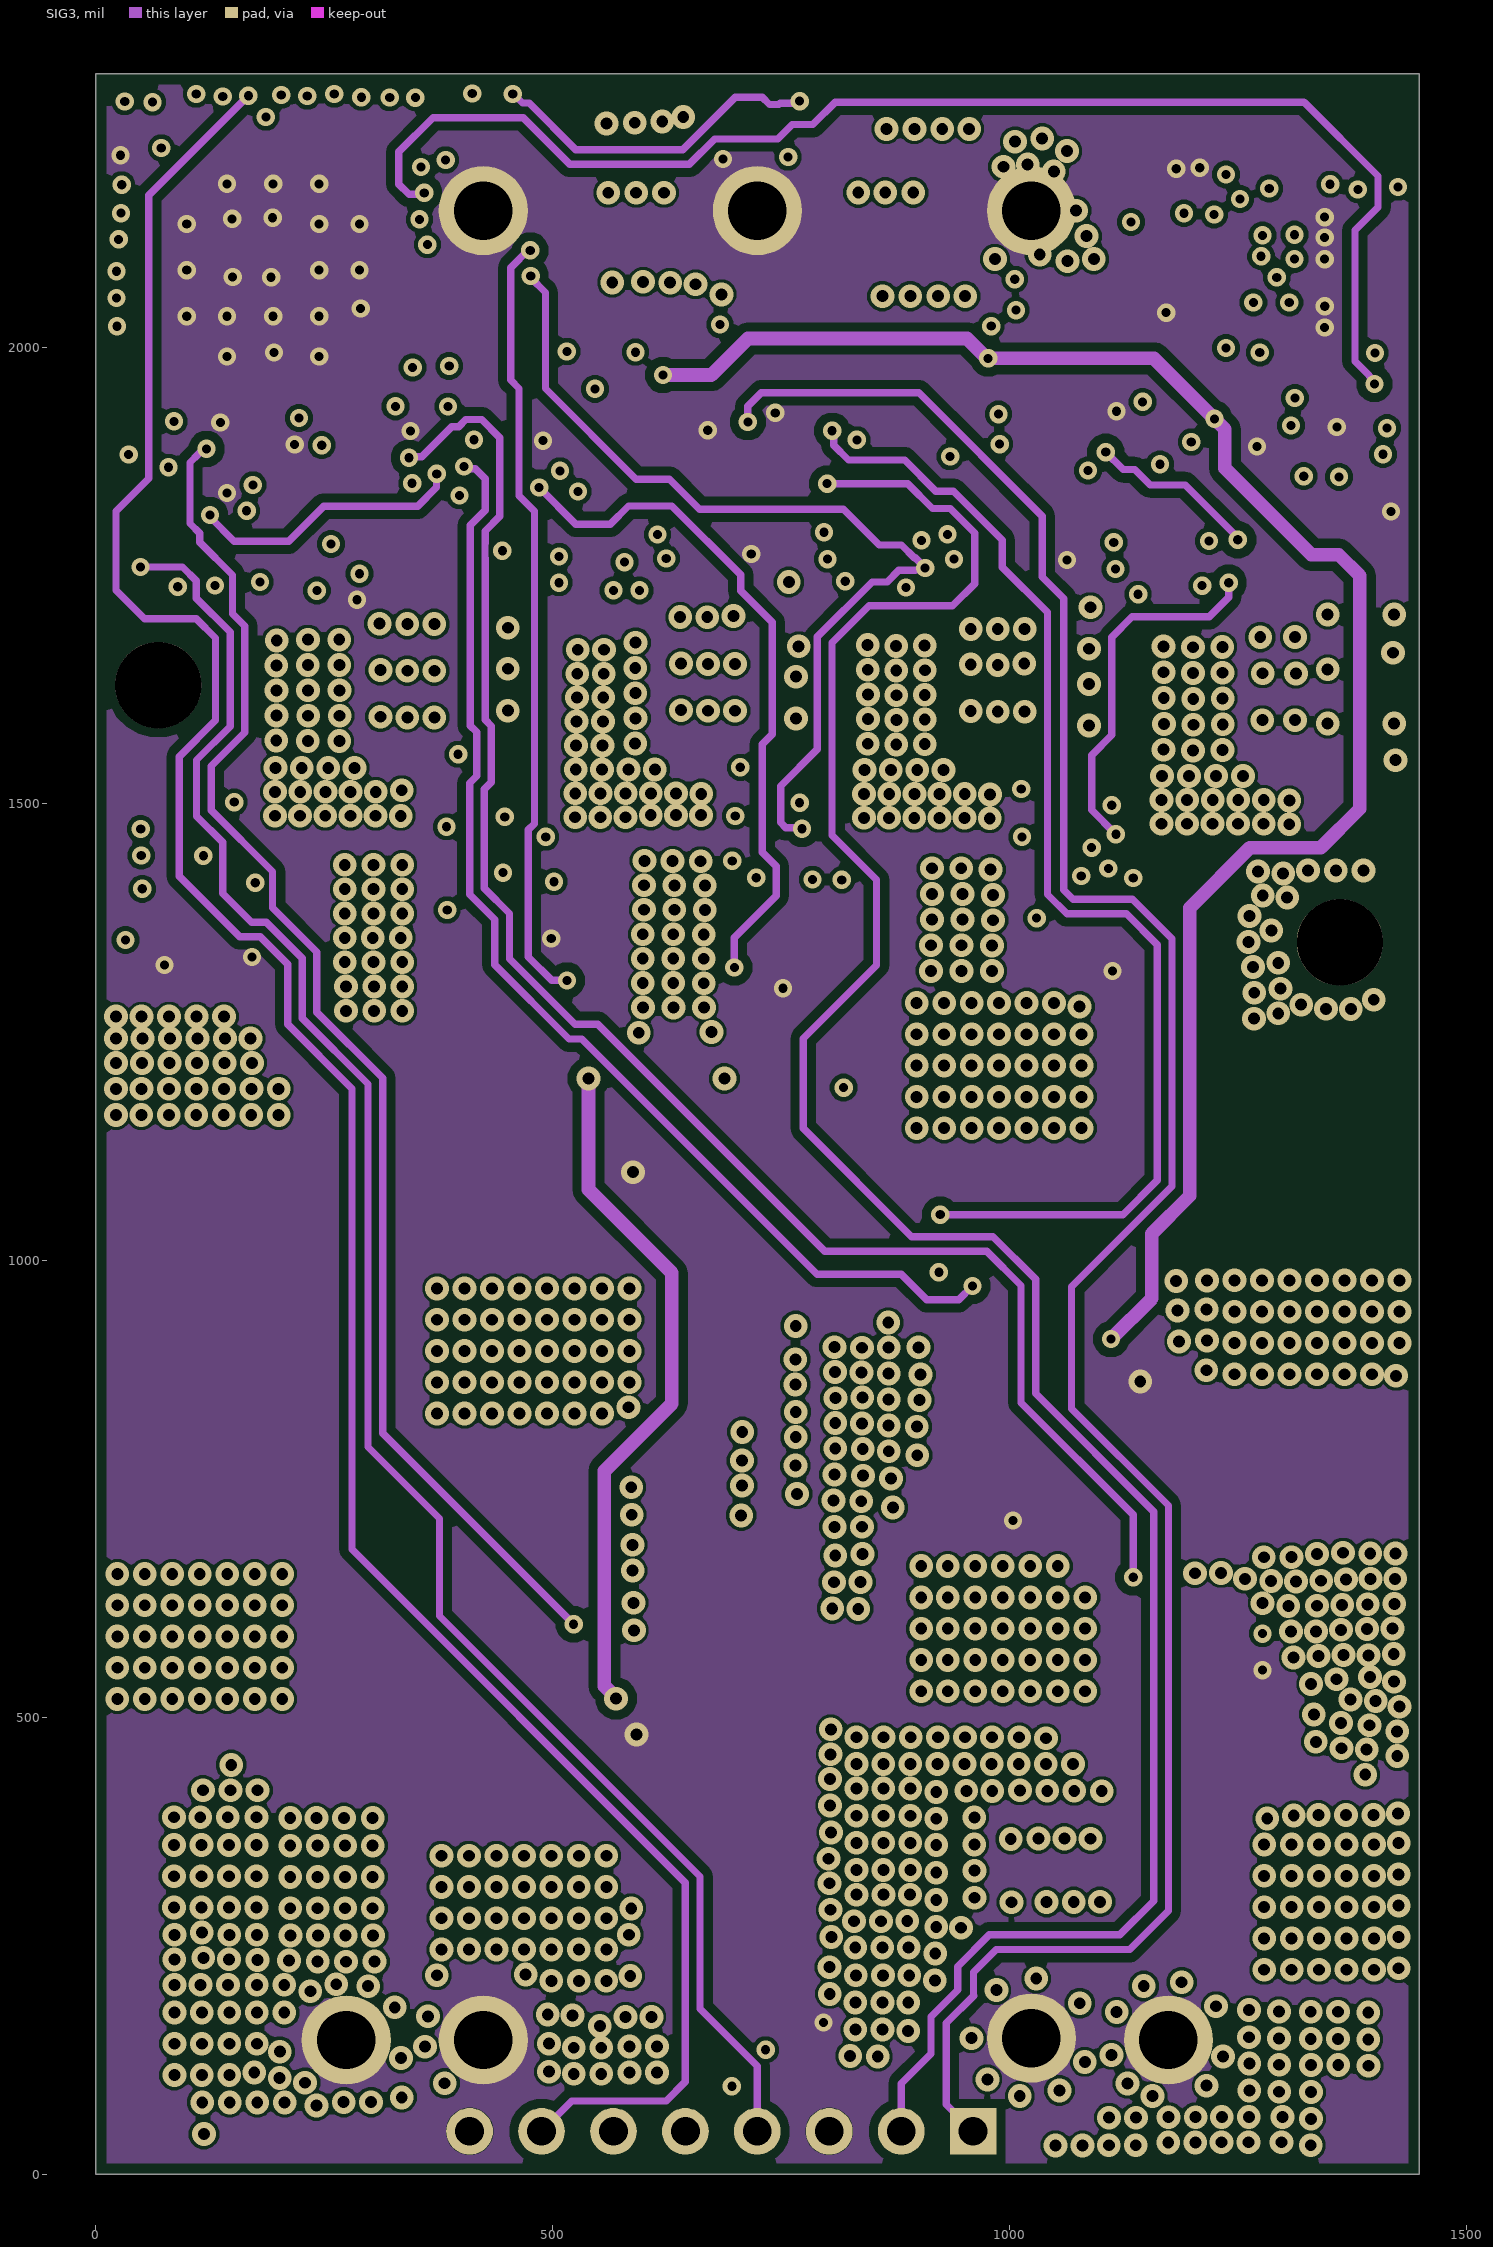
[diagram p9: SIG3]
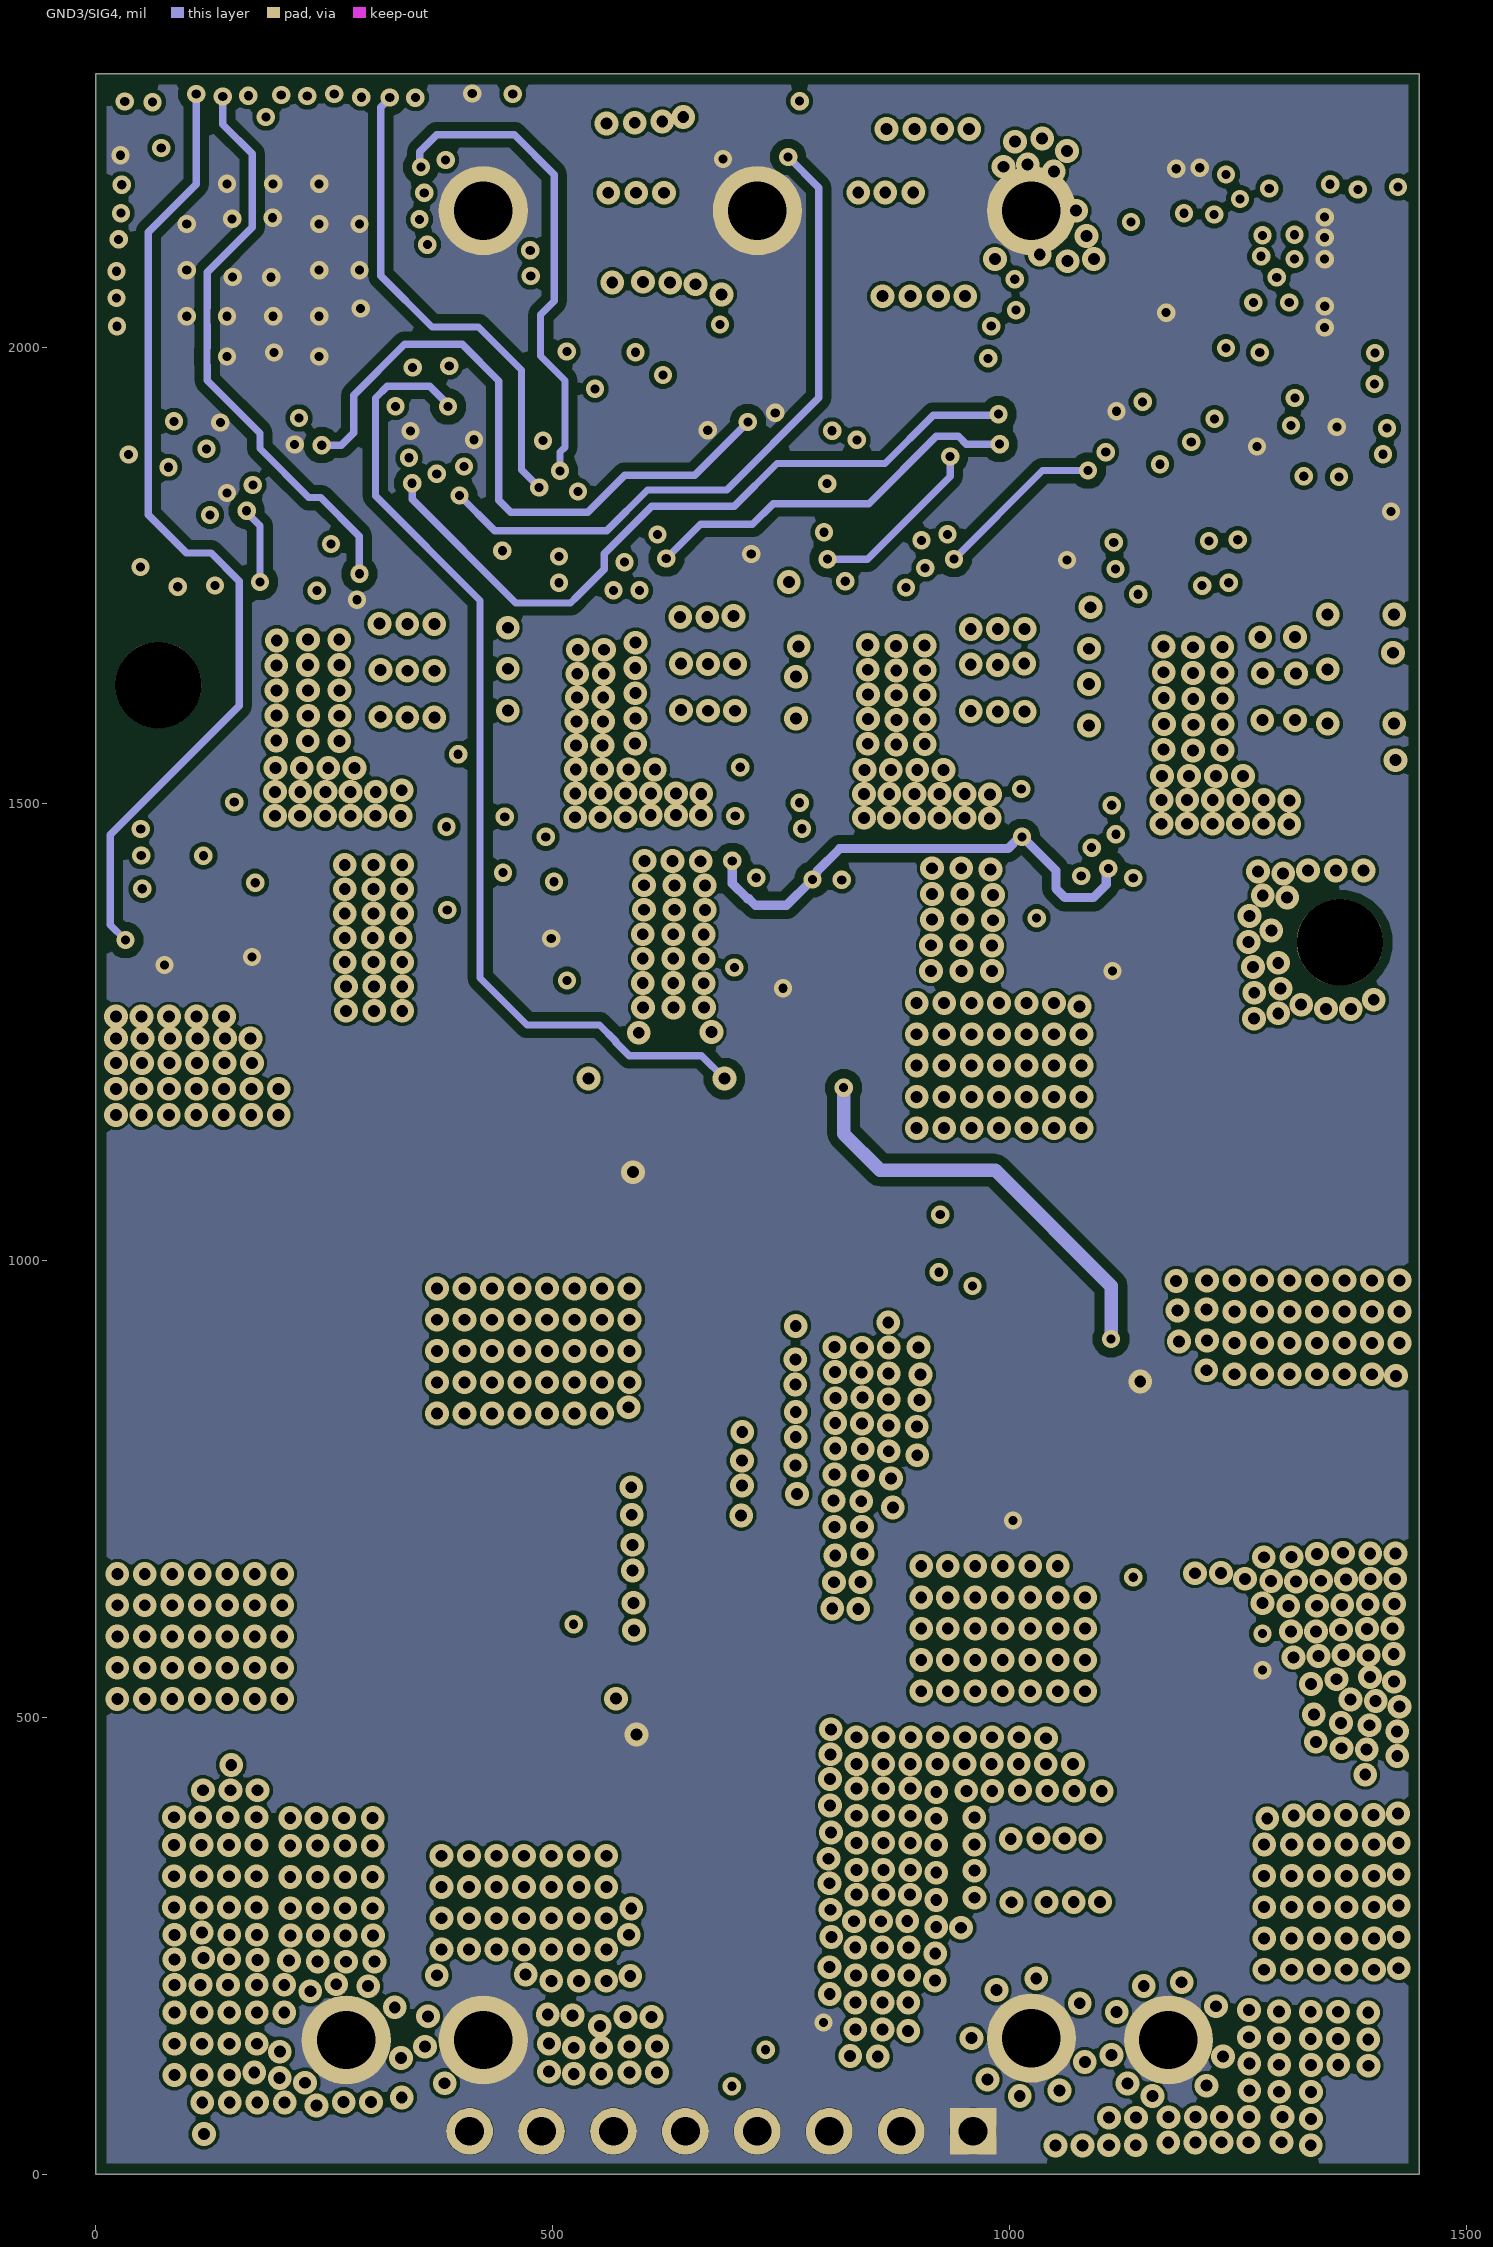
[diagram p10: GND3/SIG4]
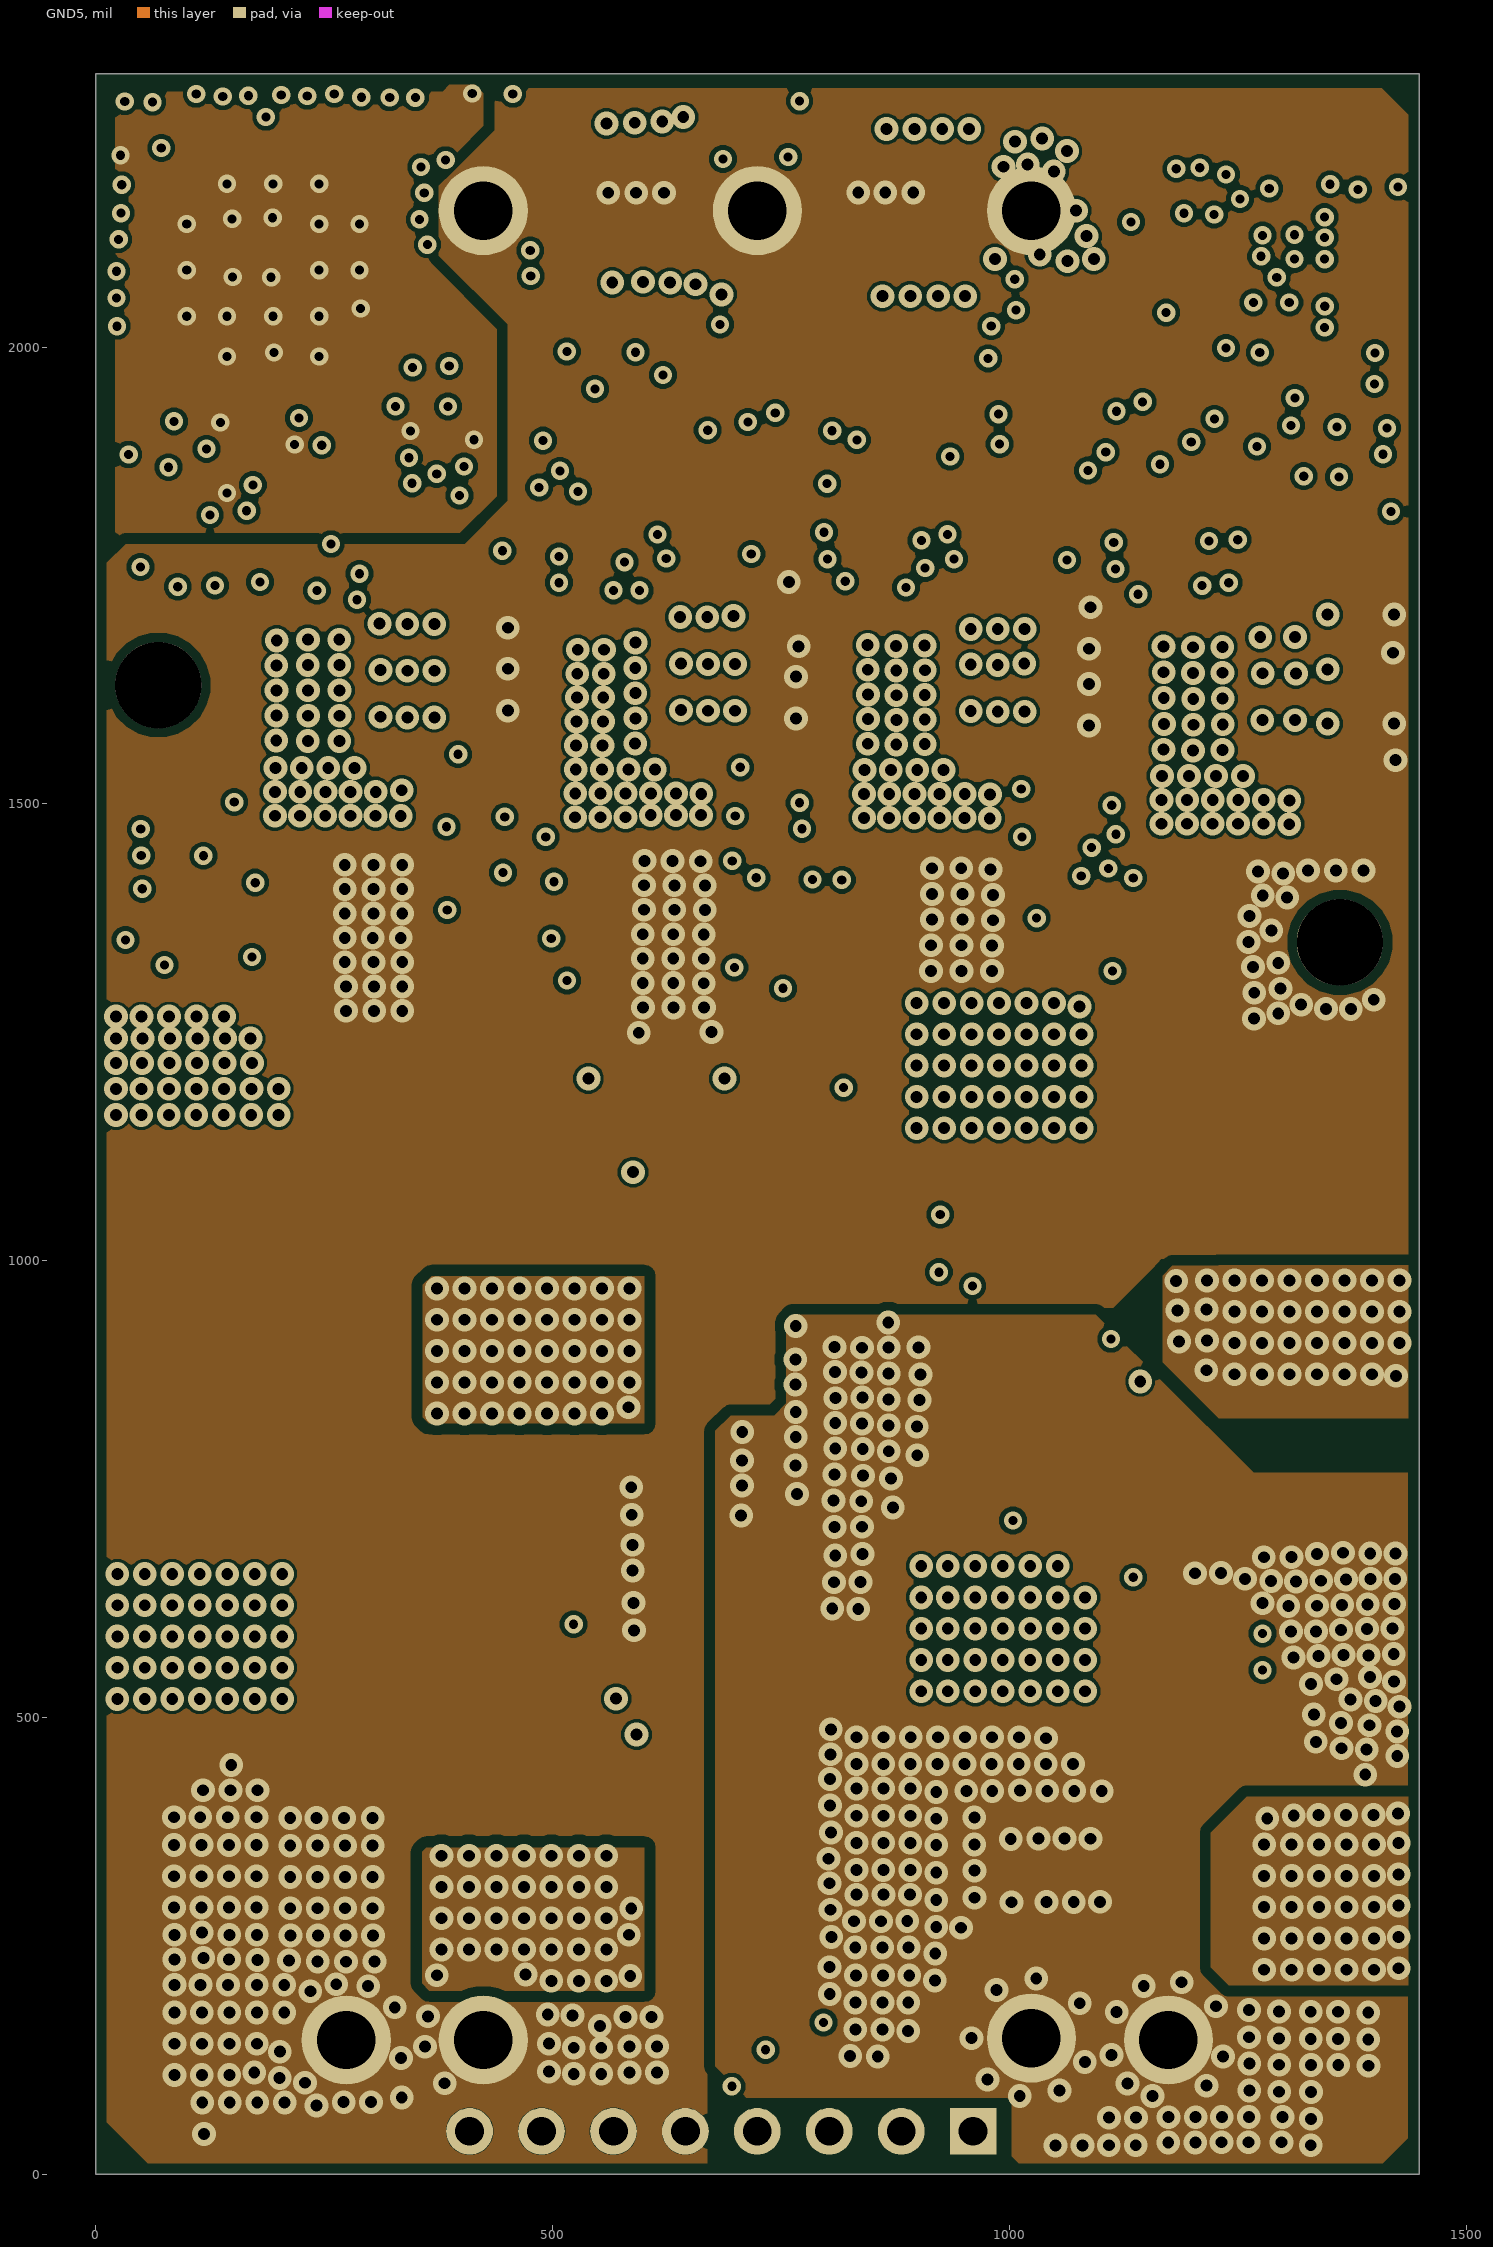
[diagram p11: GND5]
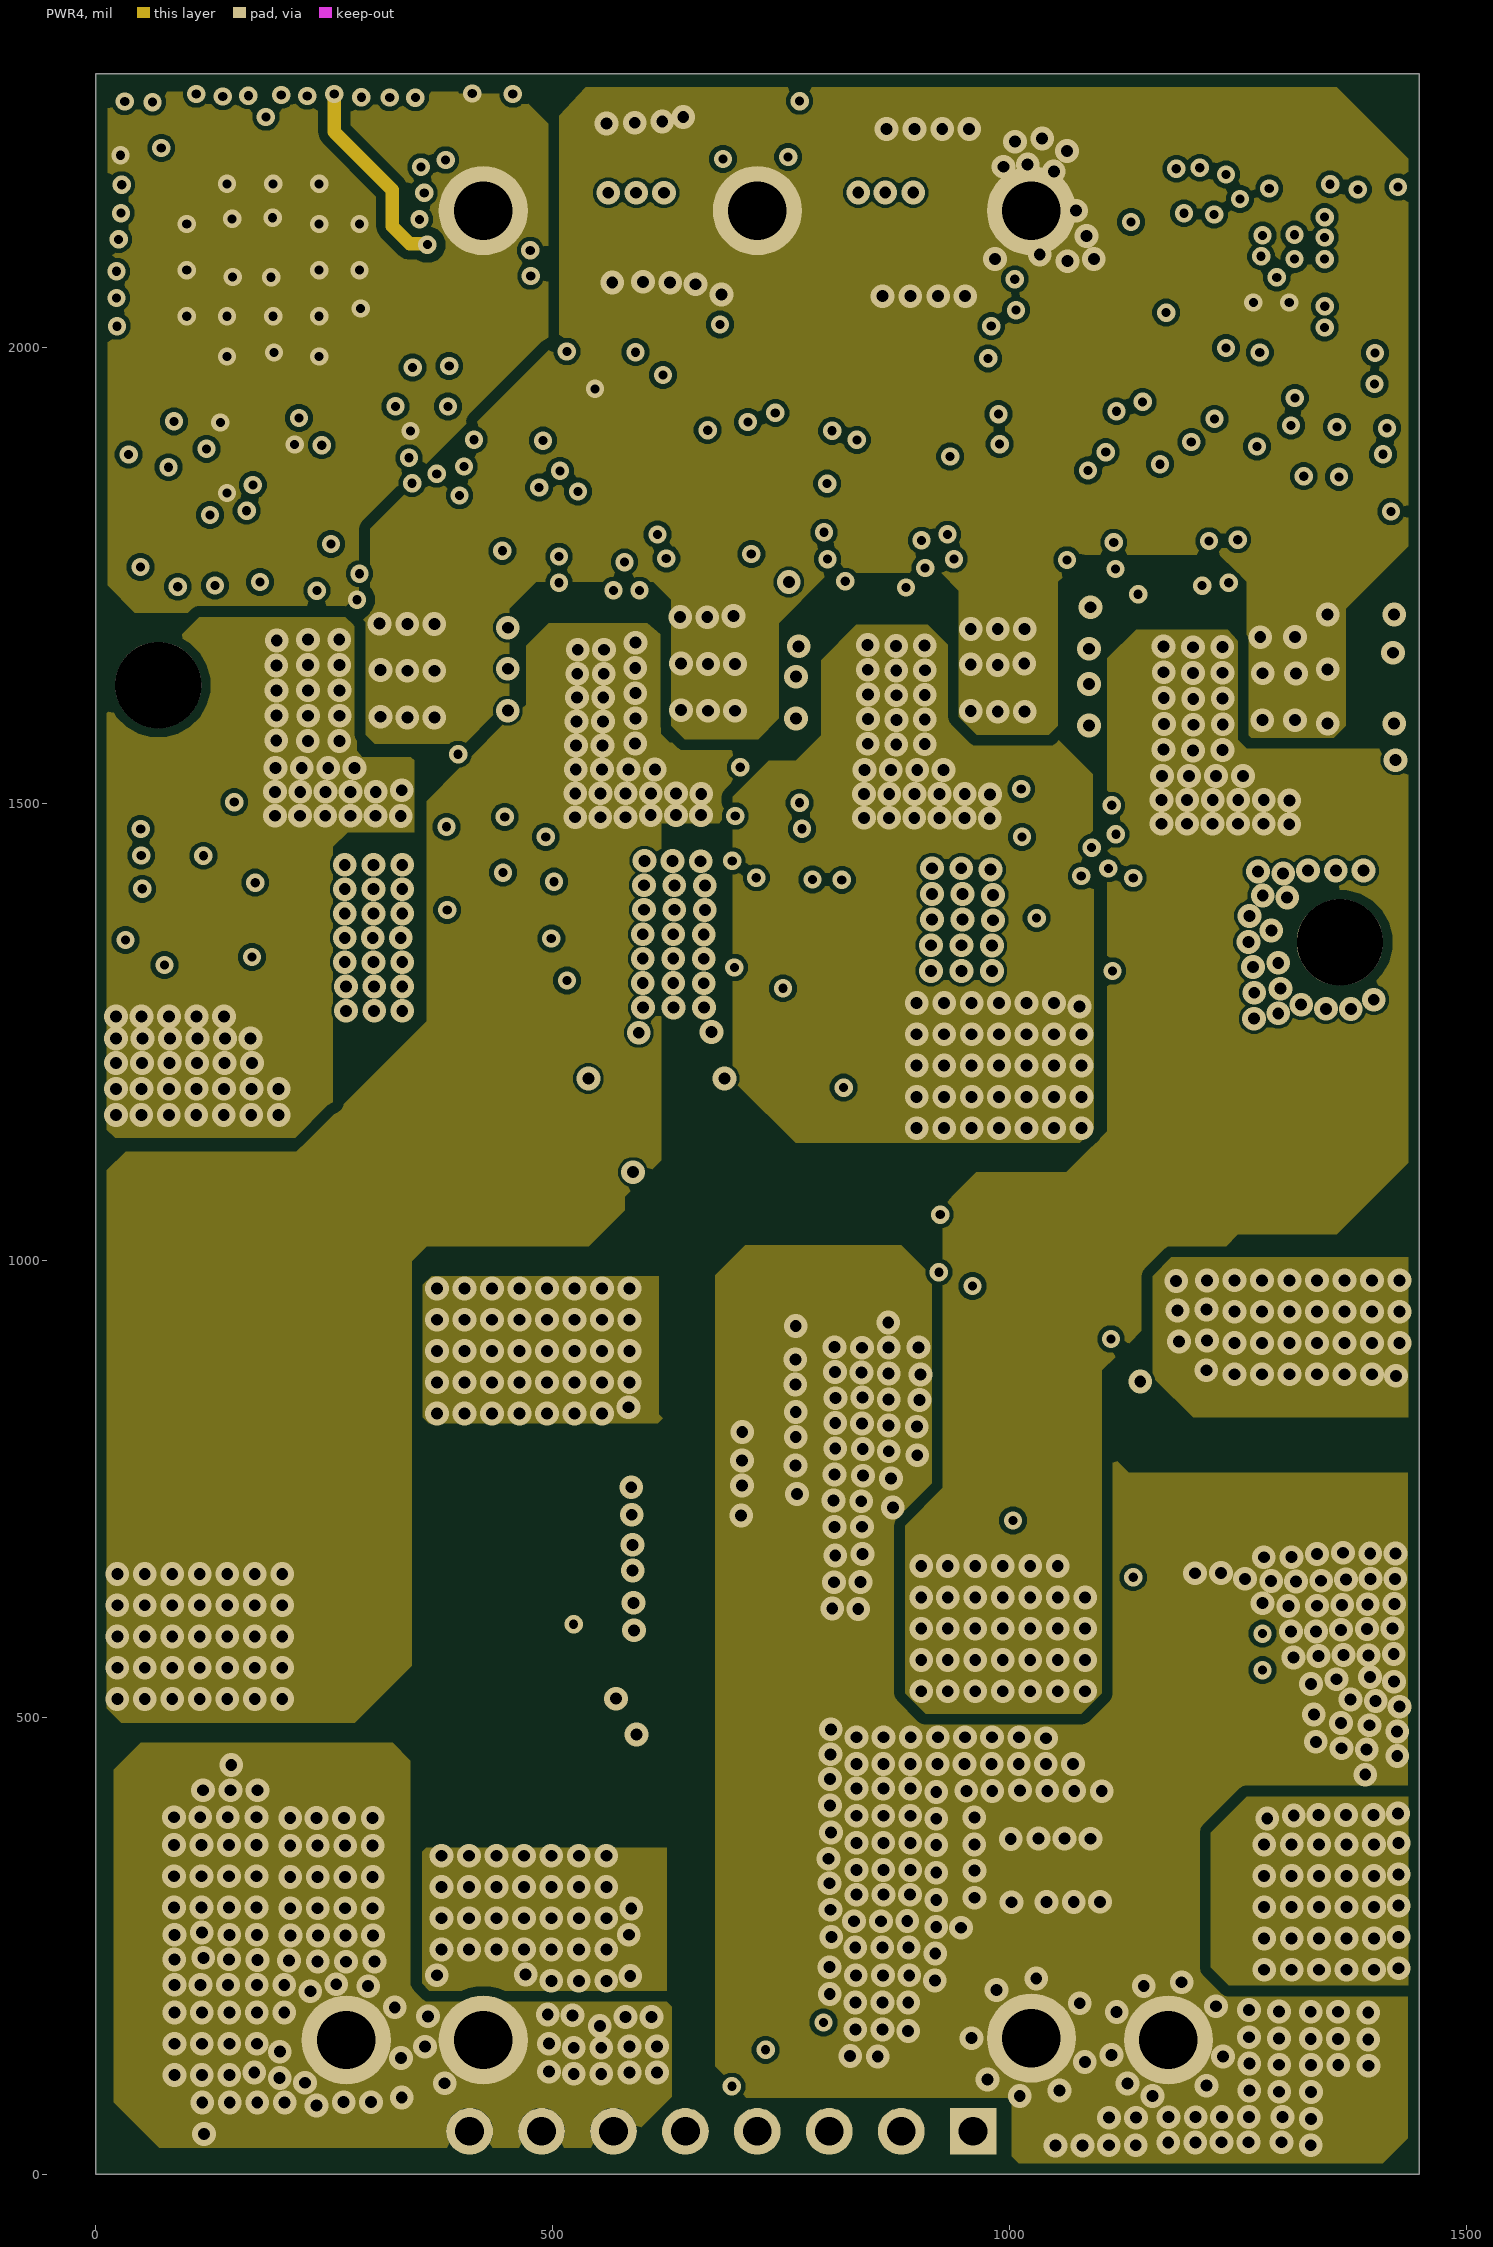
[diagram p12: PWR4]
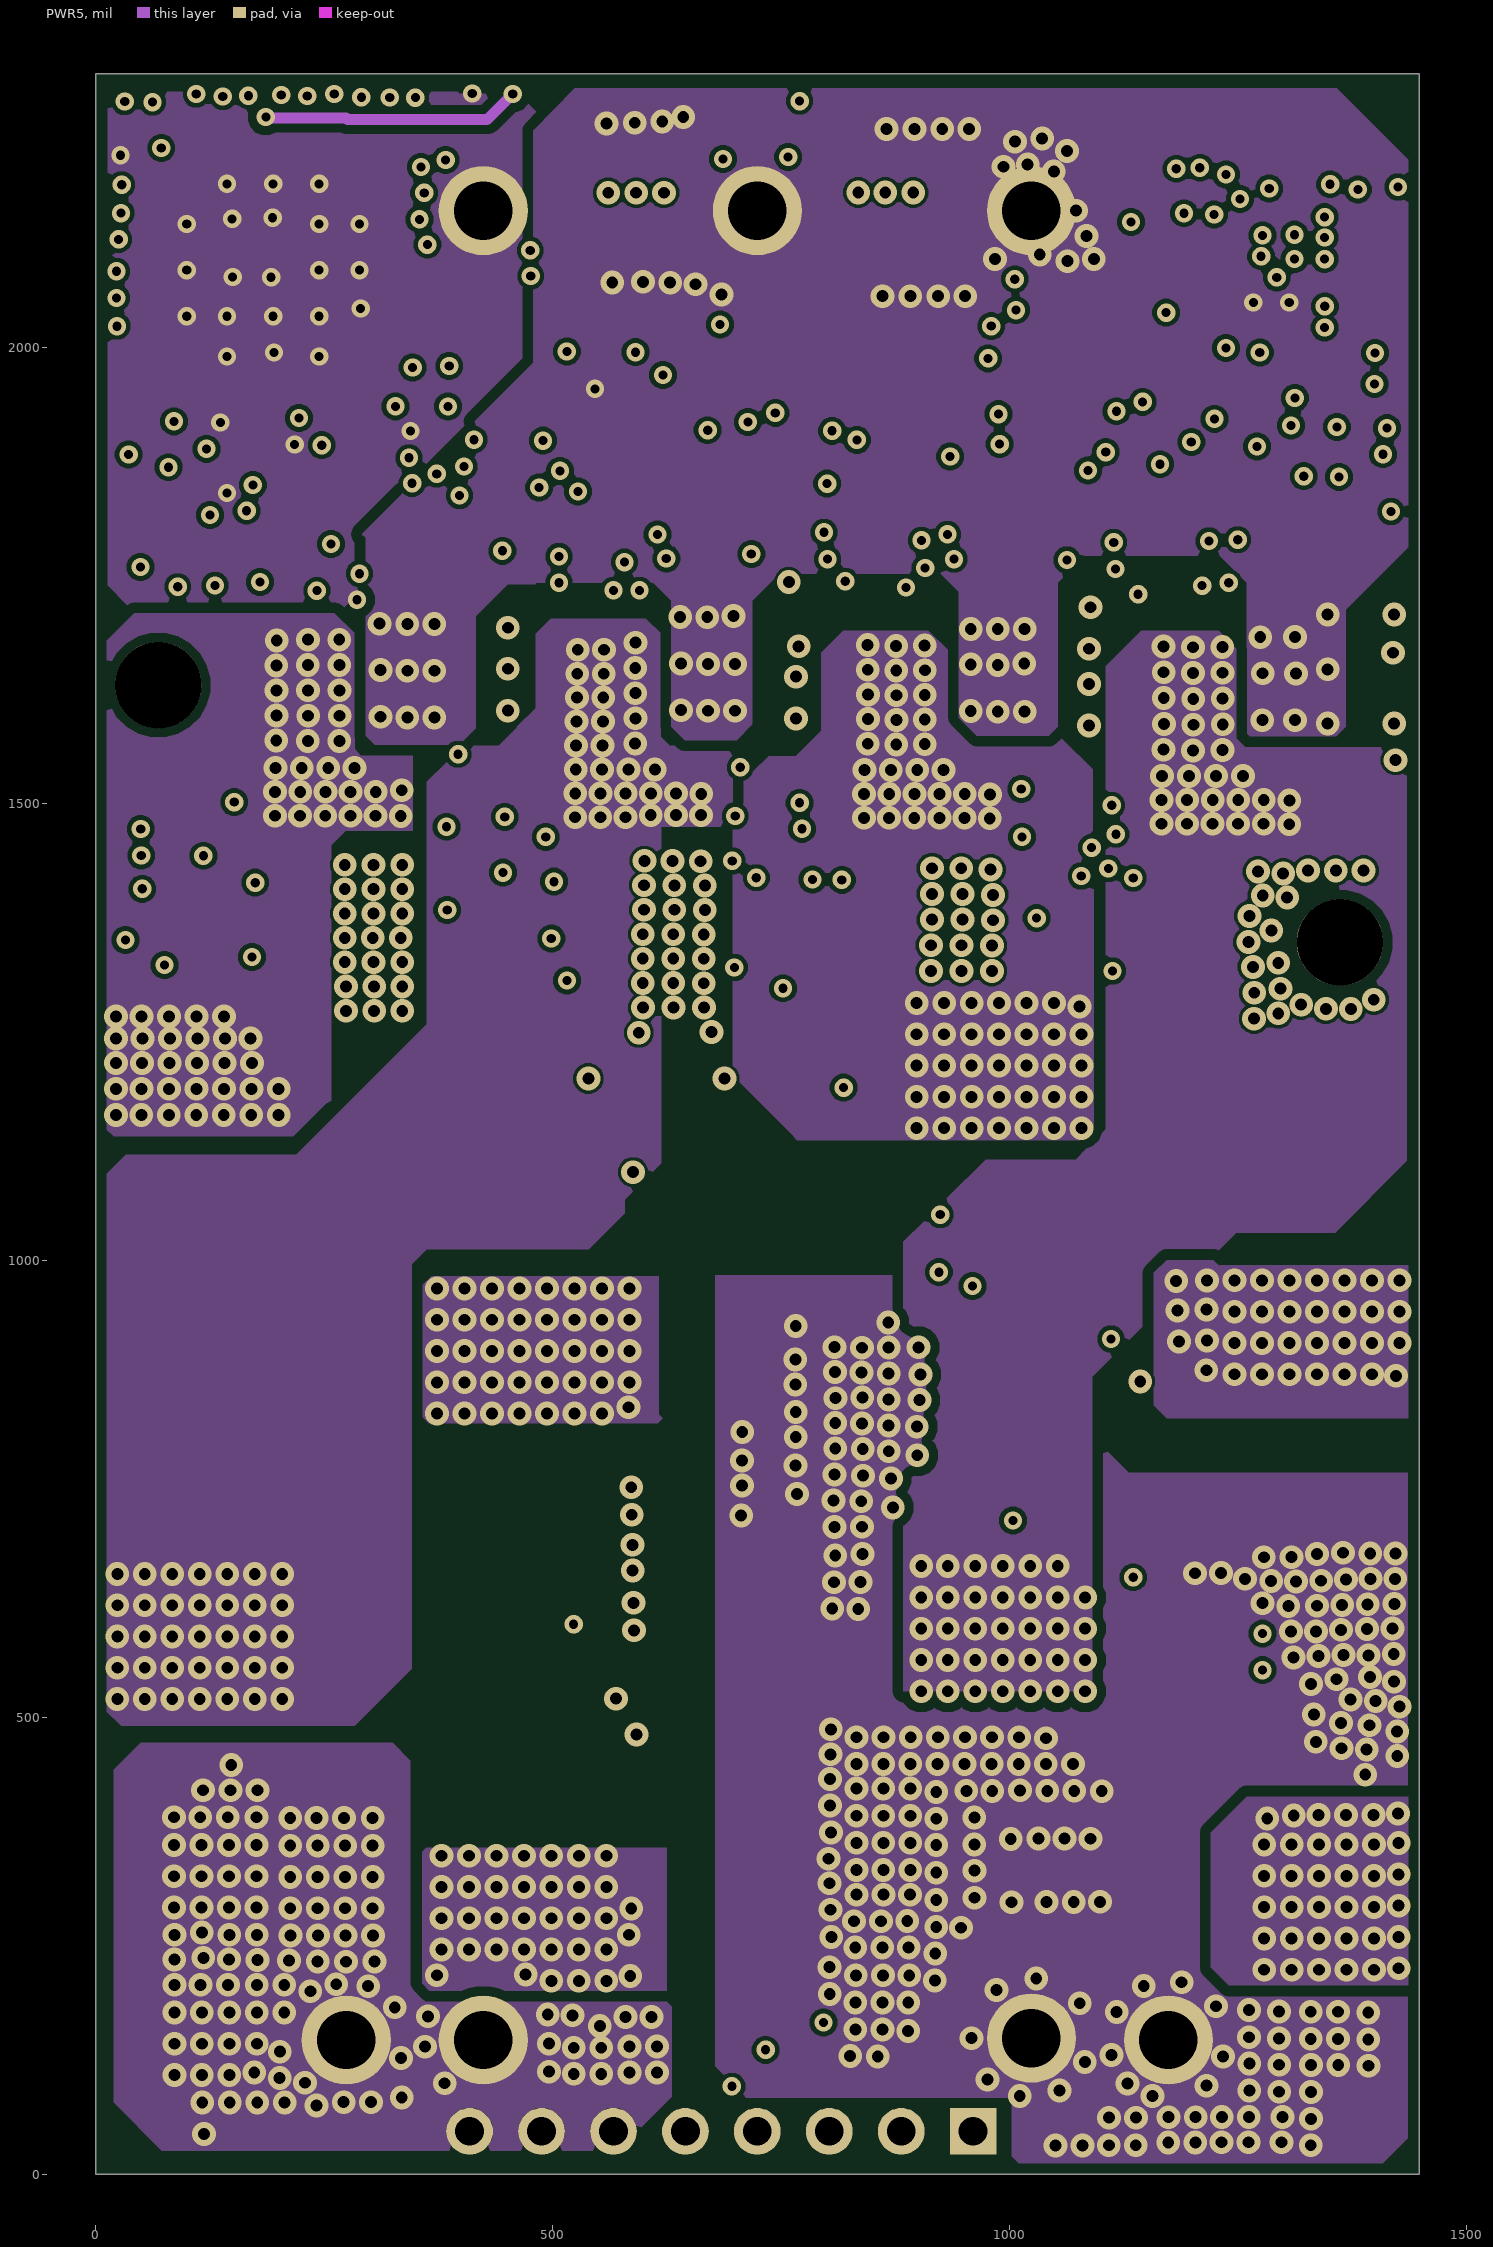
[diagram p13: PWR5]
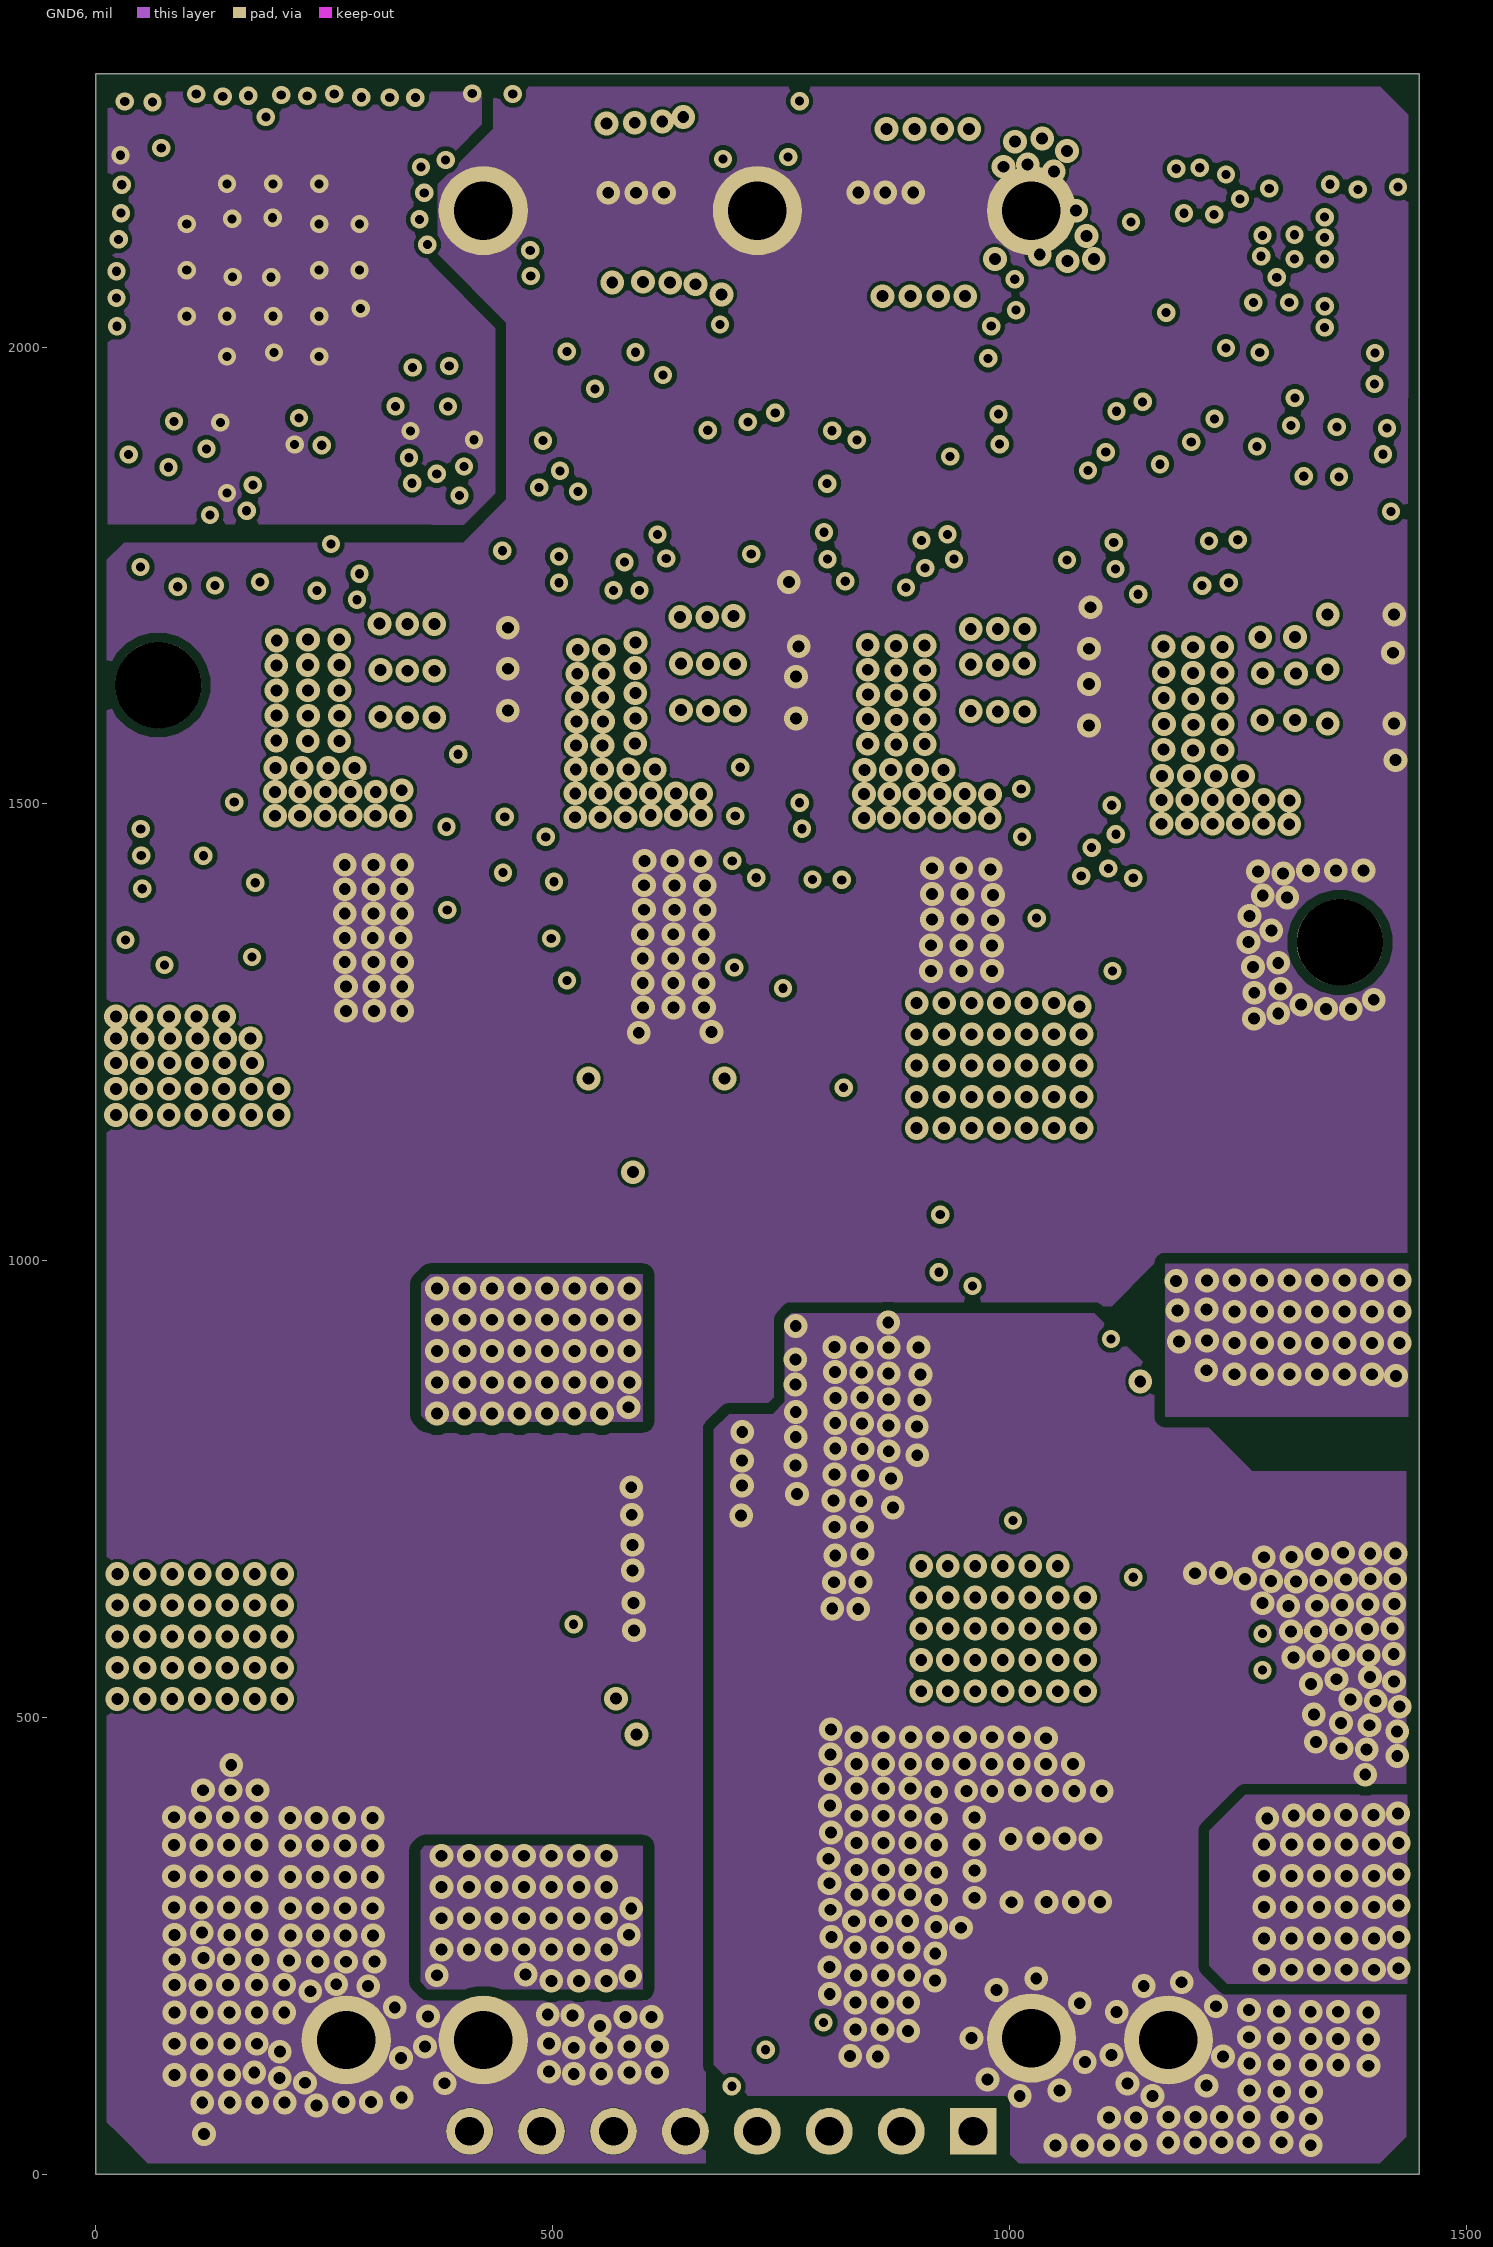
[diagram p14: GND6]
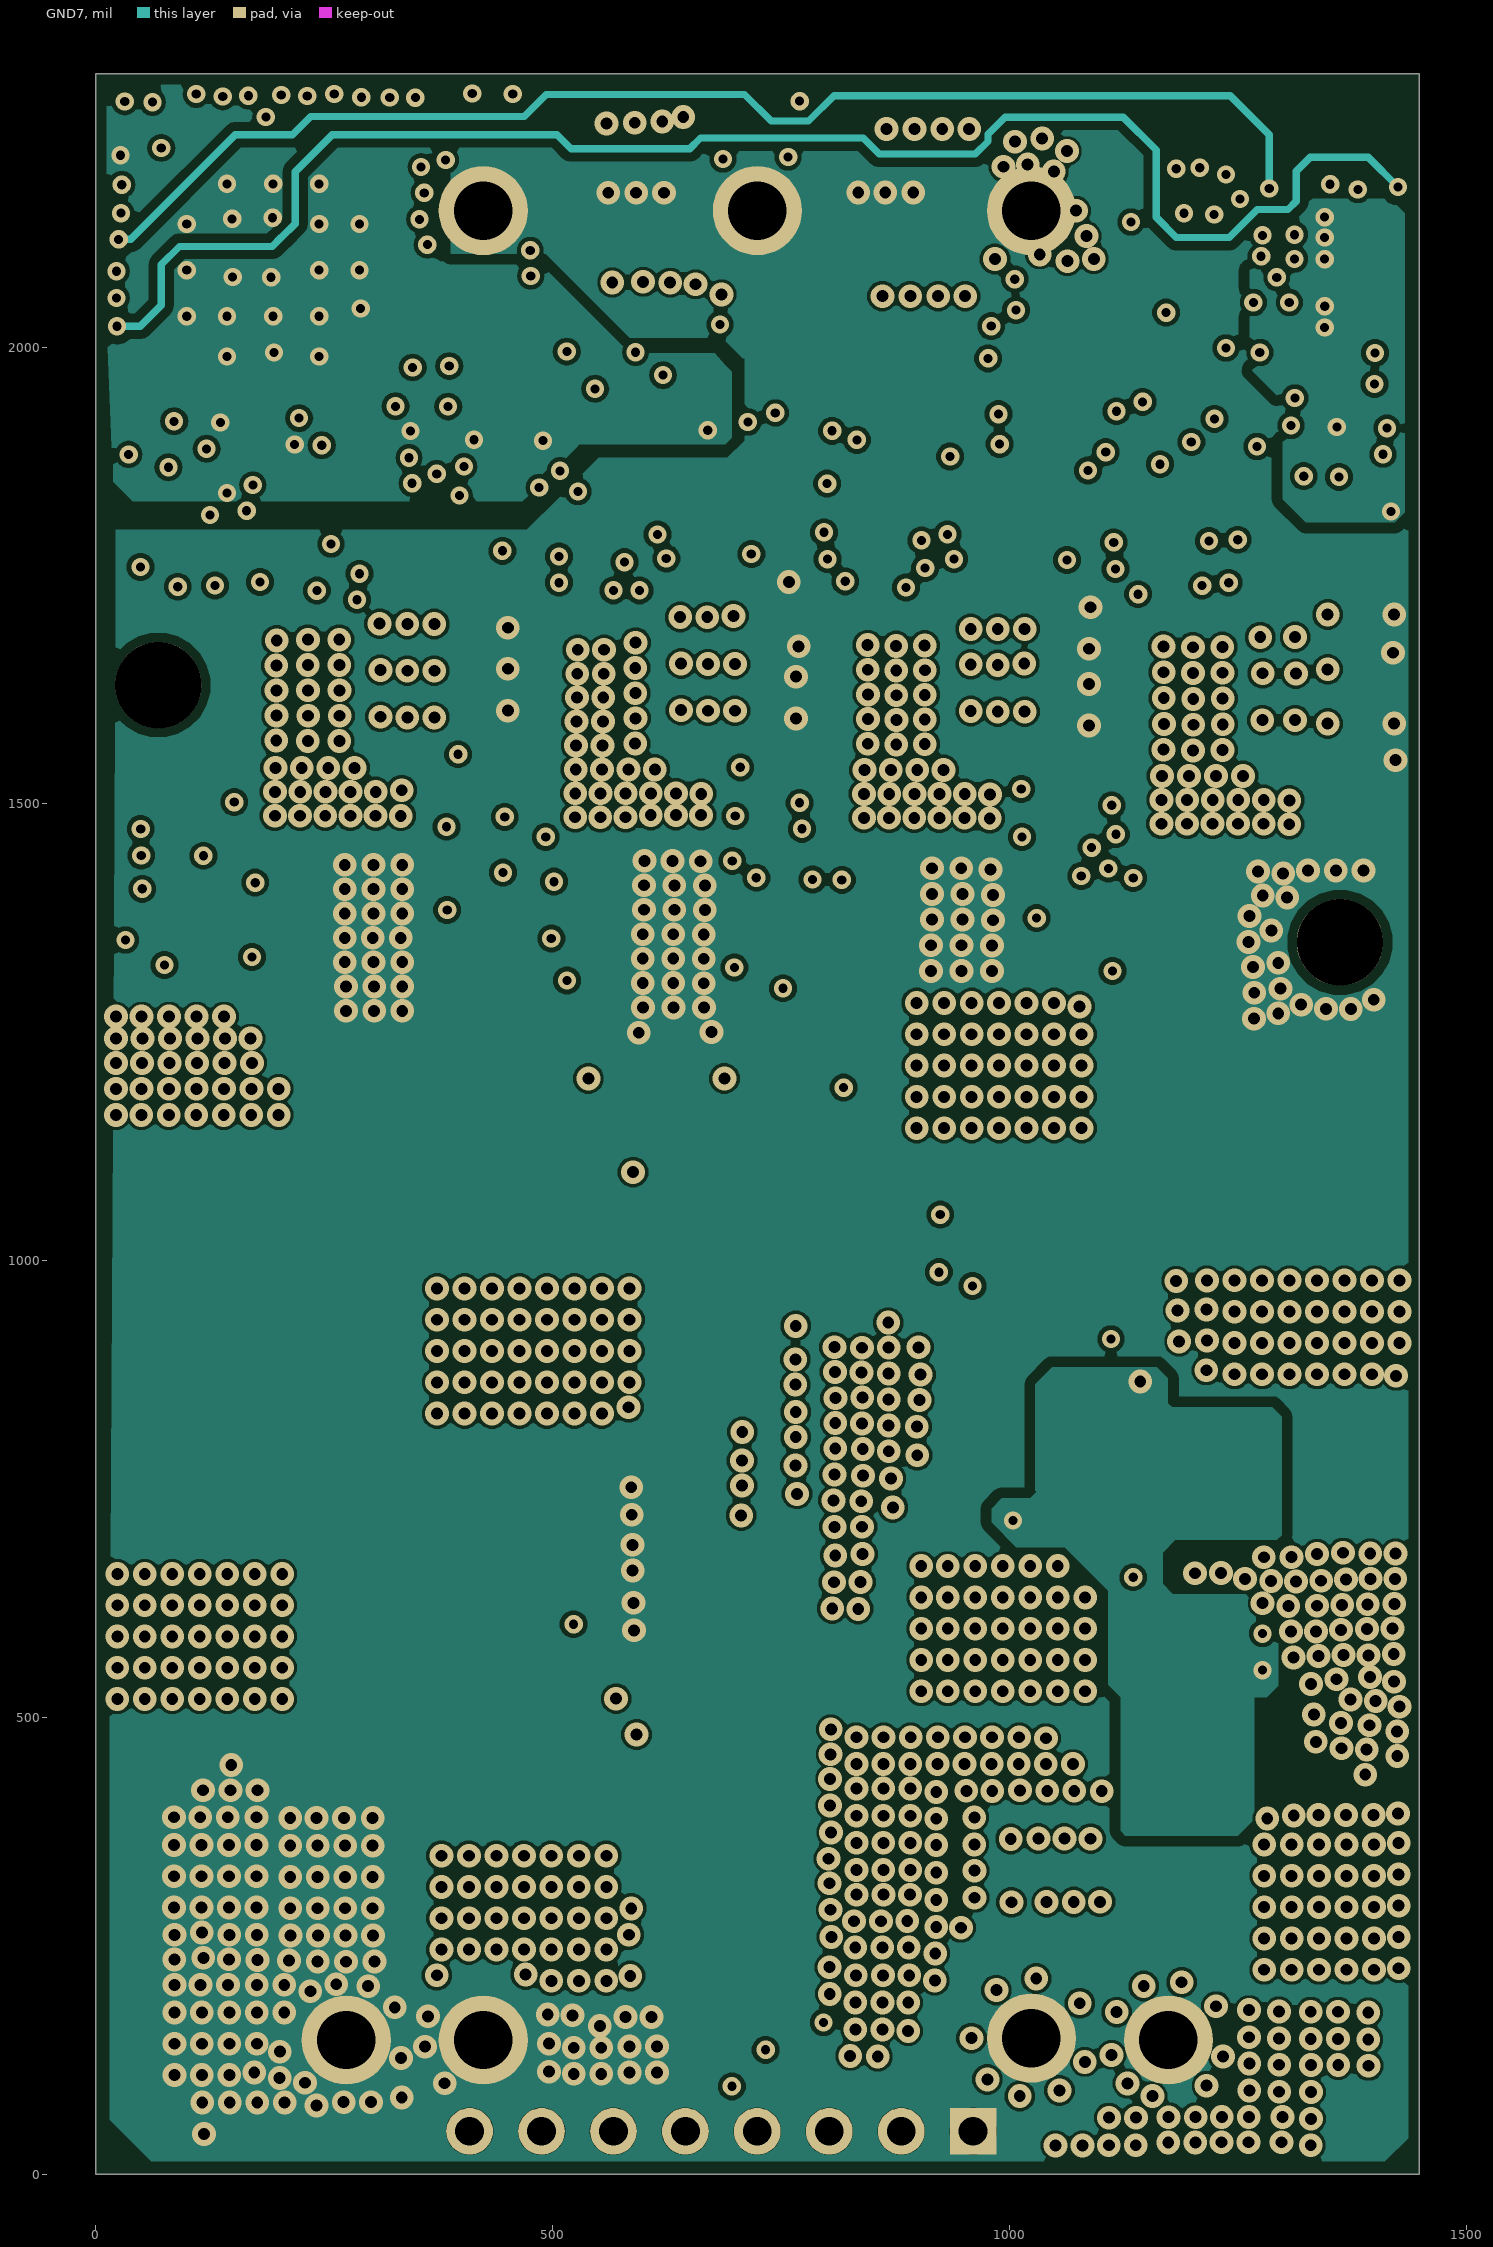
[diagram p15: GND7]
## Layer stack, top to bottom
Top Solder: solder mask 0.4, Solder Resist, Dk 3.5
Top Layer: signal copper 2.756
Dielectric 1: prepreg 2.8, FR-4 High Tg, Dk 4.1
GND1: signal copper 4.134
Dielectric 2: prepreg 2.8, FR-4 High Tg, Dk 4.1
PWR1: signal copper 4.134
Dielectric 3: prepreg 2.8, FR-4 High Tg, Dk 4.1
PWR2: signal copper 4.134
Dielectric 4: prepreg 2.8, FR-4 High Tg, Dk 4.1
PWR3: signal copper 4.134
Dielectric 5: prepreg 2.8, FR-4 High Tg, Dk 4.1
GND2: signal copper 4.134
Dielectric 6: prepreg 2.8, FR-4 High Tg, Dk 4.1
GND3/SIG1: signal copper 4.134
Dielectric 7: prepreg 2.8, FR-4 High Tg, Dk 4.1
SIG2: signal copper 4.134
Dielectric8: core 46.218, FR-4 High Tg, Dk 4.8
SIG3: signal copper 4.134
Dielectric 9: prepreg 2.8, FR-4 High Tg, Dk 4.1
GND3/SIG4: signal copper 4.134
Dielectric 10: prepreg 2.8, FR-4 High Tg, Dk 4.1
GND5: signal copper 4.134
Dielectric 11: prepreg 2.8, FR-4 High Tg, Dk 4.1
PWR4: signal copper 4.134
Dielectric 12: prepreg 2.8, FR-4 High Tg, Dk 4.1
PWR5: signal copper 4.134
Dielectric 13: prepreg 2.8, FR-4 High Tg, Dk 4.1
GND6: signal copper 4.134
Dielectric 14: prepreg 2.8, FR-4 High Tg, Dk 4.1
GND7: signal copper 4.134
Dielectric 15: prepreg 2.8, FR-4 High Tg, Dk 4.1
Bottom Layer: signal copper 2.756
Bottom Solder: solder mask 0.4, Solder Resist, Dk 3.5

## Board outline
0,0 0,2299.21 1448.82,2299.21 1448.82,0

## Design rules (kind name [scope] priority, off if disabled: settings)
AcuteAngle [All] p1: minimum=4.50000000000000E+0001 checktracksonly=FALSE
AssemblyTestPointUsage [All] p1: valid=2
BoardOutlineClearance BoardOutlineClearance_MountingHoles [OnCopper and InComponentClass('Mounting Holes')] p1: gap=14 ignorepadtopadclearanceinfootprint=FALSE
BoardOutlineClearance BoardOutlineClearance_Poly [OnCopper and IsPoly] p2: gap=12 ignorepadtopadclearanceinfootprint=FALSE
BoardOutlineClearance [OnCopper and Not InComponentClass('Logo') and not InComponentClass('FiducialMark') and not InRegion(1000,500,4000,800) and not InPoly] p3: gap=12 ignorepadtopadclearanceinfootprint=FALSE except(6.5: SMDPad-OutlineEdge Via-OutlineEdge)
Clearance Clearance_RoomException [WithinRoom('5VBuck') vs OnLayer('Bottom Layer')] p1: gap=6 ignorepadtopadclearanceinfootprint=TRUE except(5: SMDPad-Via; 8: Arc-Hole Track-Hole SMDPad-Hole THPad-Hole Via-Hole Fill-Hole Poly-Hole Region-Hole Text-Hole)
Clearance Clearance_Poly [InPolygon] p2: gap=10 ignorepadtopadclearanceinfootprint=TRUE except(12: Fill-Fill Fill-Poly Fill-Region Poly-Poly Poly-Region Region-Region)
Clearance Clearance_TOP [OnTopLayer] p3: gap=8 ignorepadtopadclearanceinfootprint=FALSE except(6: Arc-Arc Arc-Track Arc-SMDPad Track-Track Track-SMDPad SMDPad-SMDPad; 10: Arc-Hole Track-Hole SMDPad-Hole THPad-Hole Via-Hole Fill-Hole Poly-Hole Region-Hole Text-Hole; 12: Fill-Fill Fill-Poly Fill-Region Poly-Poly Poly-Region Region-Region)
Clearance Clearance_Bottom [OnBottomLayer] p4: gap=8 ignorepadtopadclearanceinfootprint=TRUE except(6: Arc-Arc Arc-Track Arc-SMDPad Arc-THPad Track-Track Track-SMDPad Track-THPad SMDPad-SMDPad SMDPad-THPad THPad-THPad; 10: Arc-Hole Track-Hole SMDPad-Hole THPad-Hole Via-Hole Fill-Hole Poly-Hole Region-Hole Text-Hole; 12: Fill-Fill Fill-Poly Fill-Region Poly-Poly Poly-Region Region-Region)
Clearance [All] p5: gap=8 ignorepadtopadclearanceinfootprint=TRUE except(10: Arc-Hole Track-Hole SMDPad-Hole THPad-Hole Via-Hole Fill-Hole Poly-Hole Region-Hole Text-Hole; 12: Fill-Fill Fill-Poly Fill-Region Poly-Poly Poly-Region Region-Region)
Clearance Clearance_Keepouts [((IsTrack Or IsArc) And Not InPoly) And IsFree and IsKeepOut vs ((IsTrack Or IsArc) And Not InPoly) And IsFree and IsKeepOut] p6: gap=0 ignorepadtopadclearanceinfootprint=FALSE
Clearance Clearance_FiducialMark [IsKeepOut and InComponentClass('FiducialMark') vs IsPad and InComponentClass('FiducialMark')] p7: gap=0 ignorepadtopadclearanceinfootprint=FALSE
DiffPairsRouting [All] p1: maxlimit=100 minlimit=10 mostfreqgap=10 toplayer_minwidth=7 toplayer_maxwidth=15 toplayer_prefwidth=15 midlayer1_minwidth=7 midlayer1_maxwidth=15 midlayer1_prefwidth=15 midlayer2_minwidth=7 midlayer2_maxwidth=15 midlayer2_prefwidth=15 midlayer3_minwidth=7 midlayer3_maxwidth=15 midlayer3_prefwidth=15 midlayer4_minwidth=7 midlayer4_maxwidth=15 midlayer4_prefwidth=15 midlayer5_minwidth=7 midlayer5_maxwidth=15 midlayer5_prefwidth=15 midlayer6_minwidth=7 midlayer6_maxwidth=15 midlayer6_prefwidth=15 midlayer7_minwidth=7 midlayer7_maxwidth=15 midlayer7_prefwidth=15 midlayer8_minwidth=7 midlayer8_maxwidth=15 midlayer8_prefwidth=15 midlayer9_minwidth=7 midlayer9_maxwidth=15 midlayer9_prefwidth=15 midlayer10_minwidth=7 midlayer10_maxwidth=15 midlayer10_prefwidth=15 midlayer11_minwidth=7 midlayer11_maxwidth=15 midlayer11_prefwidth=15 midlayer12_minwidth=7 midlayer12_maxwidth=15 midlayer12_prefwidth=15 midlayer13_minwidth=7 midlayer13_maxwidth=15 midlayer13_prefwidth=15 midlayer14_minwidth=7 midlayer14_maxwidth=15 midlayer14_prefwidth=15 bottomlayer_minwidth=7 bottomlayer_maxwidth=15 bottomlayer_prefwidth=15 maxuncoupledlength=1000
FabricationTestPointUsage TestPointUsage [All] p1: valid=2 allowmultiple=FALSE
FabricationTestpoint Testpoint [All] p1: side=3 testpointundercomponent=TRUE minsize=40 maxsize=100 preferedsize=60 minholesize=0 maxholesize=40 preferedholesize=32 testpointgrid=1 allowsidetop=TRUE allowsidebottom=TRUE usegrid=TRUE gridtolerance=0.01
FanoutControl Fanout_LCC [IsLCC] p1: bgadir=Out bgaviamode=Centered fanoutstyle=Auto fanoutdirection=Alternating viagrid=1 // Fanout_LCC (Default Rule)
FanoutControl Fanout_BGA [IsBGA] p2: bgadir=Out bgaviamode=Centered fanoutstyle=Auto fanoutdirection=Alternating viagrid=1 // Fanout_BGA (Default Rule)
FanoutControl Fanout_Default [All] p4: bgadir=Out bgaviamode=Centered fanoutstyle=Auto fanoutdirection=Alternating viagrid=1 // Fanout_Default (Default Rule)
FanoutControl Fanout_Small [(CompPinCount < 5)] p5: bgadir=Out bgaviamode=Centered fanoutstyle=Auto fanoutdirection=OutThenIn viagrid=1 // Fanout_Small (Default Rule)
HoleSize [All] p1: absolutevalues=TRUE maxlimit=251 minlimit=7 maxpercent=80.000 minpercent=20.000
MinimumAnnularRing MinimumAnnularRing_ThermalPadVias [IsVia and InAnyComponent] p1: minimumring=5
MinimumAnnularRing [All] p2: minimumring=5
MinimumSolderMaskSliver MinimumSolderMaskSliver_Logo [InComponentClass('Logo') vs InComponentClass('Logo')] p1: minsoldermaskwidth=0.7
MinimumSolderMaskSliver [All] p2: minsoldermaskwidth=3
PlaneConnect [All] p1: planeconnectstyle=Direct reliefexpansion=10 reliefentries=4 reliefconductorwidth=10 reliefairgap=10
PolygonConnect [All] p1: connectstyle=Direct reliefconductorwidth=10 reliefentries=4 polygonreliefangle="90 Angle" airgapwidth=10
RoomDefinition [False vs False] p1: confinementstyle=ConfineIn formatcopy=TRUE lockcomponents=FALSE outline 1279.53,2283.46 1437.01,2283.46 1279.53,2283.46
RoomDefinition 5VBuck [False vs False] p2: confinementstyle=ConfineIn formatcopy=TRUE lockcomponents=FALSE outline 1246.03,2155.43 1446.85,2155.43 1446.85,1958.59 1246.03,1958.59
RoutingVias ThermalPadVias [IsVia and InAnyComponent] p1: holewidth=8 width=30 viastyle="Through Hole" minholewidth=7.87 minwidth=19.68 maxholewidth=20 maxwidth=30
RoutingVias [All] p2: holewidth=10 width=20 viastyle="Through Hole" minholewidth=7.87 minwidth=19.68 maxholewidth=40 maxwidth=65
SilkToBoardRegionClearance [Not ((IsComment or IsDesignator) And (Hide <> 'False')) and not InRegion(1000,500,4000,800)] p1:
SilkToSilkClearance SilkToSilkClearance_Pb-FreeLogo [(HasFootprint('Pb-Free_Overlay_Medium') OR HasFootprint('Pb-Free_Overlay_Small')) vs (HasFootprint('Pb-Free_Overlay_Medium') OR HasFootprint('Pb-Free_Overlay_Small'))] p1: silktosilkclearance=0
SilkToSilkClearance [All] p2: silktosilkclearance=1
SilkToSolderMaskClearance SilkToComponentPadClearance [(IsPad or IsFill or IsRegion) and InAnycomponent] p1: minsilkscreentomaskgap=2 clearancetoexposedcopper=TRUE
SilkToSolderMaskClearance "Silk to Solder Mask Opening" [All] p2: minsilkscreentomaskgap=2 clearancetoexposedcopper=FALSE
SolderMaskExpansion [All] p1: expansion=1.97 istentingtop=FALSE
SupplyNets "Schematic Supply Nets_14" [InNet('VDDIO_3V3')] p1: voltage=0.000
SupplyNets "Schematic Supply Nets_13" [InNet('+3V3_MCU')] p2: voltage=0.000
SupplyNets "Schematic Supply Nets_12" [InNet('GPIO35/TDI')] p3: voltage=0.000
SupplyNets "Schematic Supply Nets_11" [InNet('SCI_RX')] p4: voltage=0.000
SupplyNets "Schematic Supply Nets_10" [InNet('5V')] p5: voltage=0.000
SupplyNets "Schematic Supply Nets_9" [InNet('SCI_TX')] p6: voltage=0.000
SupplyNets "Schematic Supply Nets_8" [InNet('VDD_1V25')] p7: voltage=0.000
SupplyNets "Schematic Supply Nets_7" [InNet('VDDA_3V3')] p8: voltage=0.000
SupplyNets "Schematic Supply Nets_6" [InNet('MCU_TMS')] p9: voltage=0.000
SupplyNets "Schematic Supply Nets_5" [InNet('MCU_TCK')] p10: voltage=0.000
SupplyNets "Schematic Supply Nets_4" [InNet('PGND')] p11: voltage=0.000
SupplyNets "Schematic Supply Nets_3" [InNet('GPIO37/TDO')] p12: voltage=0.000
SupplyNets "Schematic Supply Nets_2" [InNet('3V3')] p13: voltage=0.000
SupplyNets "Schematic Supply Nets_1" [InNet('GND')] p14: voltage=0.000
SupplyNets "Schematic Supply Nets" [InNet('VIN')] p15: voltage=0.000
UnRoutedNet [All] p1: checkbadconnections=TRUE
Width [All] p1: maxlimit=100 minlimit=6 preferedwidth=8 midlayer1_minwidth=8 midlayer2_minwidth=8 midlayer3_minwidth=8 midlayer4_minwidth=8 midlayer5_minwidth=8 midlayer6_minwidth=8 midlayer7_minwidth=8 midlayer8_minwidth=8 midlayer9_minwidth=8 midlayer10_minwidth=8 midlayer11_minwidth=8 midlayer12_minwidth=8 midlayer13_minwidth=8 midlayer14_minwidth=8 minimp=50.000000 maximp=50.000000 favimp=50.000000 checkconnectedcopper=TRUE
15 further rules are at their usual default settings.

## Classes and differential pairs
component class PowerStage: C7 C9 C10 C11 C12 C13 C14 C15 C16 C17 C18 C19 C20 C21 C22 C23 C24 C33 C34 C35 C36 C37 C38 C39 C40 C41 C42 C43 C44 C45 C46 C47 C48 C49 C50 C51 C52 C53 C54 C55 C56 C57 C58 C59 C60 C61 C62 C63 C64 C65 C66 C67 C68 C69 C70 C71 C72 C73 C81 C82 C83 C84 C85 C86 C87 C88 C89 C90 C91 C92 C95 C127 C128 C129 C130 C131 C132 C133 C134 C135 C136 C137 C138 C139 C140 C141 C142 J1 J2 J3 J4 J5 J6 L1 L2 NT1 R1 R2 R3 R4 R5 R6 R7 R8 R9 R10 R11 R12 R13 R14 R15 R16 R17 R18 R19 R20 R21 R22 R23 R24 R27 R28 R31 R32 R33 R34 R35 R36 R37 R38 R39 R40 R41 R42 R43 R44 R71 R72 R73 R74 R75 R76 R77 R78 R79 R80 R81 R82 R96 R97 R98 R99 U1 U2 U3 U4 U5 U6 U7 U8 U9 U10 U11 U12 U13 U14 U15 U16 U17
net class PWM: EPWM1A EPWM1B EPWM2A EPWM2B EPWM3A EPWM3B EPWM4A EPWM4B
component class MCU_Support: 3V3 C143 C144 C145 C146 C147 C148 C149 C150 C151 C152 C153 C154 GND L3 L4 R56 R85 R86 RX TCK TDI TDO TMS TX
component class TIDA-05x_Hardware: !PCB1 Logo3 Logo4 Logo5 Logo6
component class Logo: Logo4
net class HV: SW1 SW2 SW3 SW4 VIN
component class Header: J8
component class Control: C93 C94 C96 C97 C98 C103 C106 C107 C108 C111 C114 C118 C119 C120 C121 C122 C123 C124 C125 C155 J7 J8 MP1 MP2 Q1 R45 R46 R47 R49 R51 R55 R58 R60 R61 R62 R65 R66 R67 R68 R69 R70 R87 R88 R91 R92 R93 R94 R95 RT1 U18 U19 U22 U23
differential pair VOSNS: +VOSNS_P -VOSNS_N

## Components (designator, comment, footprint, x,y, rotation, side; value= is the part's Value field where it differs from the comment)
3V3 "TP_SM_1MM" tp_custom 1267.8,2242.26 r0 bottom
C7 "C3225X7R2A106K250AC" FP-C3225X7R2A106K250AC_1210-MFG 869.95,1983.96 r0 bottom value=10µF
C9 "C3225X7R2A106K250AC" FP-C3225X7R2A106K250AC_1210-MFG 580.71,2104.45 r0 bottom value=10µF
C10 "C3225X7R2A106K250AC" FP-C3225X7R2A106K250AC_1210-MFG 580.82,2234.23 r0 bottom value=10µF
C11 "C3225X7R2A106K250AC" FP-C3225X7R2A106K250AC_1210-MFG 880.6,2244.09 r0 bottom value=10µF
C12 "C3225X7R2A106K250AC" FP-C3225X7R2A106K250AC_1210-MFG 880.6,2104.45 r0 bottom value=10µF
C13 "C2012X5R2A475K125AC" FP-C2012X5R2A475K125AC_0805-MFG 1384.85,1587.97 r180 bottom value=4.7µF
C14 "C2012X5R2A475K125AC" FP-C2012X5R2A475K125AC_0805-MFG 1384.85,1707.28 r180 bottom value=4.7µF
C15 "C2012X5R2A475K125AC" FP-C2012X5R2A475K125AC_0805-MFG 639.1,2201.42 r90 top value=4.7µF
C16 "C2012X5R2A475K125AC" FP-C2012X5R2A475K125AC_0805-MFG 575.84,2201.42 r90 top value=4.7µF
C17 "C2012X5R2A475K125AC" FP-C2012X5R2A475K125AC_0805-MFG 514.17,2201.42 r90 top value=4.7µF
C18 "C2012X5R2A475K125AC" FP-C2012X5R2A475K125AC_0805-MFG 877.32,2202.77 r90 top value=4.7µF
C19 "C2012X5R2A475K125AC" FP-C2012X5R2A475K125AC_0805-MFG 813.94,2202.77 r90 top value=4.7µF
C20 "C2012X5R2A475K125AC" FP-C2012X5R2A475K125AC_0805-MFG 941.33,2092.61 r270 top value=4.7µF
C21 "C2012X5R2A475K125AC" FP-C2012X5R2A475K125AC_0805-MFG 1384.85,1647.25 r180 bottom value=4.7µF
C22 "C2012X5R2A475K125AC" FP-C2012X5R2A475K125AC_0805-MFG 514.17,2093.67 r270 top value=4.7µF
C23 "C2012X5R2A475K125AC" FP-C2012X5R2A475K125AC_0805-MFG 575.84,2093.67 r270 top value=4.7µF
C24 "C2012X5R2A475K125AC" FP-C2012X5R2A475K125AC_0805-MFG 639.1,2093.67 r270 top value=4.7µF
C33 "C2012X5R2A475K125AC" FP-C2012X5R2A475K125AC_0805-MFG 750.22,1708.99 r180 bottom value=4.7µF
C34 "C2012X5R2A475K125AC" FP-C2012X5R2A475K125AC_0805-MFG 940.7,2202.77 r90 top value=4.7µF
C35 "C2012X5R2A475K125AC" FP-C2012X5R2A475K125AC_0805-MFG 750.22,1644.84 r180 bottom value=4.7µF
C36 "C2012X5R2A475K125AC" FP-C2012X5R2A475K125AC_0805-MFG 814.58,2092.61 r270 top value=4.7µF
C37 "C2012X5R2A475K125AC" FP-C2012X5R2A475K125AC_0805-MFG 1060.29,1586.65 r180 bottom value=4.7µF
C38 "C2012X5R2A475K125AC" FP-C2012X5R2A475K125AC_0805-MFG 1060.29,1650.6 r180 bottom value=4.7µF
C39 "C2012X5R2A475K125AC" FP-C2012X5R2A475K125AC_0805-MFG 750.44,1584.05 r180 bottom value=4.7µF
C40 "C2012X5R2A475K125AC" FP-C2012X5R2A475K125AC_0805-MFG 1060.29,1710.48 r180 bottom value=4.7µF
C41 "C2012X5R2A475K125AC" FP-C2012X5R2A475K125AC_0805-MFG 426.7,1594.29 r180 bottom value=4.7µF
C42 "C2012X5R2A475K125AC" FP-C2012X5R2A475K125AC_0805-MFG 426.24,1713.39 r180 bottom value=4.7µF
C43 "C2012X5R2A475K125AC" FP-C2012X5R2A475K125AC_0805-MFG 426.48,1654.18 r180 bottom value=4.7µF
C44 "C2012X5R2A475K125AC" FP-C2012X5R2A475K125AC_0805-MFG 877.95,2092.61 r270 top value=4.7µF
C45 "GRM033Z71C104KE14D" 0201 179.69,1757.43 r270 bottom value=0.1uF
C46 "GRM033Z71C104KE14D" 0201 506.33,1756.64 r270 bottom value=0.1uF
C47 "GRM033Z71C104KE14D" 0201 820.61,1757.82 r270 bottom value=0.1uF
C48 "GRM033Z71C104KE14D" 0201 1142.24,1756.22 r270 bottom value=0.1uF
C49 "GRM033Z71C104KE14D" 0201 360.61,1761.26 r270 bottom value=0.1uF
C50 "GRM033Z71C104KE14D" 0201 677.41,1756.86 r270 bottom value=0.1uF
C51 "GRM033Z71C104KE14D" 0201 993.02,1756.79 r270 bottom value=0.1uF
C52 "GRM033Z71C104KE14D" 0201 1335.71,1766.5 r0 bottom value=0.1uF
C53 "GRT155R71A474KE01D" FP-GRT155R71A474KE01D_0402-MFG 179.82,1757.23 r90 top value=470nF
C54 "GRT155R71A474KE01D" FP-GRT155R71A474KE01D_0402-MFG 506.88,1758.32 r90 top value=470nF
C55 "GRT155R71A474KE01D" FP-GRT155R71A474KE01D_0402-MFG 824.05,1757.53 r90 top value=470nF
C56 "GRT155R71A474KE01D" FP-GRT155R71A474KE01D_0402-MFG 1142.12,1757.65 r90 top value=470nF
C57 "CL32B106KBJNNWE" 1210_270 665.5,761.99 r180 top value=10uF
C58 "CL32B106KBJNNWE" 1210_270 666.11,631.01 r180 top value=10uF
C59 "CL32B106KBJNNWE" 1210_270 696.23,688.04 r180 bottom locked value=10uF
C60 "CL32B106KBJNNWE" 1210_270 696.23,814.88 r180 bottom locked value=10uF
C61 "CL32B106KBJNNWE" 1210_270 851.79,1014.91 r90 bottom value=10uF
C62 "CL32B106KBJNNWE" 1210_270 696.23,329.95 r180 bottom locked value=10uF
C63 "CL32B106KBJNNWE" 1210_270 696.23,941.72 r180 bottom locked value=10uF
C64 "CL32B106KBJNNWE" 1210_270 696.23,567.54 r180 bottom locked value=10uF
C65 "CL32B106KBJNNWE" 1210_270 696.23,446.42 r180 bottom locked value=10uF
C66 "C1005X5R1C225K050BC" 0402S 157.8,1351.63 r0 top value=2.2uF
C67 "C1005X5R1C225K050BC" 0402S 484.86,1352.72 r0 top value=2.2uF
C68 "C1005X5R1C225K050BC" 0402S 802.34,1351.76 r0 top value=2.2uF
C69 "C1005X5R1C225K050BC" 0402S 1121.33,1351.72 r0 top value=2.2uF
C70 "GRM033R71E101JA01D" 0201_033 97.33,1324.08 r180 top value=100pF
C71 "GRM033R71E101JA01D" 0201_033 423,1333.44 r180 top value=100pF
C72 "GRM033R71E101JA01D" 0201_033 751.98,1319.53 r270 top value=100pF
C73 "GRM033R71E101JA01D" 0201_033 1057.85,1329.66 r180 top value=100pF
C81 "GRM033Z71C104KE14D" 0201 588.75,1185.7 r270 top value=0.1uF
C82 "GRM033Z71C104KE14D" 0201 601.08,498.98 r270 top value=0.1uF
C83 "GRM033Z71C104KE14D" 0201 1097.26,867.32 r0 bottom value=0.1uF
C84 "GRM033Z71C104KE14D" 0201 1277.07,571.76 r270 bottom value=0.1uF
C85 "GRM155R71C104KA88D" 0402S 690.42,1085.04 r0 top value=0.1uF
C86 "GRM155R71C104KA88D" 0402S 699.97,416.22 r0 top value=0.1uF
C87 "GRM155R71C104KA88D" 0402S 1170.87,768.57 r270 bottom value=0.1uF
C88 "GRM155R71C104KA88D" 0402S 1197.04,500.12 r180 bottom value=0.1uF
C89 "GRM033R71E101JA01D" 0201_033 425.72,1960.56 r0 bottom value=100pF
C90 "GRM033R71E101JA01D" 0201_033 156.73,1916.53 r180 bottom value=100pF
C91 "GRM033R71E101JA01D" 0201_033 452.76,1932.59 r180 bottom value=100pF
C92 "GRM033R71E101JA01D" 0201_033 307.43,1908.4 r0 bottom value=100pF
C93 "0201BB104KW160" 0201_033 514.6,1904.58 r270 bottom value=0.1uF
C94 "GRM033Z71C104KE14D" 0201 643.13,2014.26 r0 bottom value=0.1uF
C95 "GRM033Z71C104KE14D" 0201 963.51,1974.35 r270 top value=0.1uF
C96 "250R05L101FV4T" FP-250R05L101FV4T_0201-MFG 743.96,1952.03 r90 bottom value=100pF
C97 "GRM033R71C102KA01D" 0201 261.06,1835.7 r180 bottom value=1000pF
C98 "0201BB104KW160" 0201_033 290.58,1896.21 r270 top value=0.1uF
C103 "CL03A105MP3NSNC" 0201 208.25,1871.25 r0 bottom value=1uF
C106 "GRM033R61A225KE47D" 0201_040 727.62,2235 r180 bottom value=2.2uF
C107 "GRM033R71C102KA01D" 0201_Silk 693.23,234.96 r0 bottom value=1000pF
C108 "GRM033R71C101KA01D" 0201 452.02,2044.71 r270 bottom value=100pF
C111 "GRM033R71C102KA01D" 0201_Silk 659.11,110.28 r180 bottom value=1000pF
C114 "GRM033R61A225KE47D" 0201_040 1092.66,2243.47 r90 top value=2.2uF
C118 "12061C225KAT2A" FP-12061C225KAT2A_1206-IPC_C 1149.32,2034.78 r90 bottom value=2.2µF
C119 "06031C104K4T2A" FP-06031C104K4T2A_0603-IPC_C 1216.68,2060.2 r90 bottom locked value=100nF
C120 "C1005X5R1C225K050BC" 0402S 1383.08,2033.79 r90 top value=2.2uF
C121 "GRT188R61C106KE13D" FP-GRT188R61C106KE13D_0603-MFG 1200.27,2168.3 r270 bottom value=10µF
C122 "GRT188R61C106KE13D" FP-GRT188R61C106KE13D_0603-MFG 1133.81,2166.94 r270 bottom value=10µF
C123 "C1005X5R1C225K050BC" 0402S 1370.65,1914.81 r180 top value=2.2uF
C124 "C1005X5R1C225K050BC" 0402S 1271.19,1871.21 r90 bottom value=2.2uF
C125 "GRT188R61C106KE13D" FP-GRT188R61C106KE13D_0603-MFG 1392.88,1832.92 r180 top value=10µF
C127 "C1608X7R2A105K080AC" FP-C1608X7R2A105K080AC_0603-MFG 1374.73,1576.58 r180 top value=1µF
C128 "C1608X7R2A105K080AC" FP-C1608X7R2A105K080AC_0603-MFG 1374.73,1623.31 r180 top value=1µF
C129 "C1608X7R2A105K080AC" FP-C1608X7R2A105K080AC_0603-MFG 1374.73,1666.87 r180 top value=1µF
C130 "C1608X7R2A105K080AC" FP-C1608X7R2A105K080AC_0603-MFG 1374.73,1709.55 r180 top value=1µF
C131 "C1608X7R2A105K080AC" FP-C1608X7R2A105K080AC_0603-MFG 1065.92,1588.06 r180 top value=1µF
C132 "C1608X7R2A105K080AC" FP-C1608X7R2A105K080AC_0603-MFG 1065.92,1634.79 r180 top value=1µF
C133 "C1608X7R2A105K080AC" FP-C1608X7R2A105K080AC_0603-MFG 1065.92,1678.34 r180 top value=1µF
C134 "C1608X7R2A105K080AC" FP-C1608X7R2A105K080AC_0603-MFG 1065.92,1721.02 r180 top value=1µF
C135 "C1608X7R2A105K080AC" FP-C1608X7R2A105K080AC_0603-MFG 420.73,1597.05 r180 top value=1µF
C136 "C1608X7R2A105K080AC" FP-C1608X7R2A105K080AC_0603-MFG 420.73,1643.78 r180 top value=1µF
C137 "C1608X7R2A105K080AC" FP-C1608X7R2A105K080AC_0603-MFG 420.73,1687.34 r180 top value=1µF
C138 "C1608X7R2A105K080AC" FP-C1608X7R2A105K080AC_0603-MFG 422.02,1730.02 r180 top value=1µF
C139 "C1608X7R2A105K080AC" FP-C1608X7R2A105K080AC_0603-MFG 746.43,1591.64 r180 top value=1µF
C140 "C1608X7R2A105K080AC" FP-C1608X7R2A105K080AC_0603-MFG 746.43,1638.37 r180 top value=1µF
C141 "C1608X7R2A105K080AC" FP-C1608X7R2A105K080AC_0603-MFG 746.43,1681.93 r180 top value=1µF
C142 "C1608X7R2A105K080AC" FP-C1608X7R2A105K080AC_0603-MFG 746.51,1724.15 r180 top value=1µF
C143 "GRM155R61A106ME21D" 0402_070 210.24,2208.17 r270 top value=10uF
C144 "GRM033Z71C104KE14D" 0201 348.04,2112.44 r180 top value=0.1uF
C145 "GRM033Z71C104KE14D" 0201 241.04,2230.23 r270 top value=0.1uF
C146 "GRM033Z71C104KE14D" 0201 66.54,2177.74 r0 top value=0.1uF
C147 "GRM033R61A225KE47D" 0201_040 64.06,1957.14 r90 top value=2.2uF
C148 "GRM033R61A225KE47D" 0201_040 248.6,1963.17 r90 top value=2.2uF
C149 "GRM033Z71C104KE14D" 0201 222.31,1962.81 r90 top value=0.1uF
C150 "GRM033R61A225KE47D" 0201_040 439.55,2276.56 r180 bottom value=2.2uF
C151 "GRM033R61A225KE47D" 0201_040 297.54,2204.59 r270 top value=2.2uF
C152 "GRM033Z71C104KE14D" 0201 68,2147.76 r0 top value=0.1uF
C153 "GRM033Z71C104KE14D" 0201 268.93,2204.08 r270 top value=0.1uF
C154 "GRM033Z71C104KE14D" 0201 310.89,2145.54 r180 top value=0.1uF
C155 "885012106018" 0603 309.92,2018.32 r0 top value=2.2uF
FID1 "Fiducial" Fiducial10-20 44.32,46 r0 top
FID2 "Fiducial" Fiducial10-20 1403.51,46.34 r0 top
FID3 "Fiducial" Fiducial10-20 1376.32,1501.04 r0 top
FID4 "Fiducial" Fiducial10-20 44.32,46 r180 bottom
FID5 "Fiducial" Fiducial10-20 1403.51,46.34 r180 bottom
FID6 "Fiducial" Fiducial10-20 1182.22,2260.26 r180 bottom
GND "TP_SM_1MM" tp_custom 1317.8,2242.26 r0 bottom
J1 "5191-0-00-15-00-00-03-0" FP-5191-0-00-15-00-00-03-0_CONN_PIN-MFG 1024.16,2149.36 r0 bottom locked
J2 "5191-0-00-15-00-00-03-0" FP-5191-0-00-15-00-00-03-0_CONN_PIN-MFG 424.16,2149.36 r0 bottom
J3 "5191-0-00-15-00-00-03-0" FP-5191-0-00-15-00-00-03-0_CONN_PIN-MFG 1024.16,148.91 r0 bottom
J4 "5191-0-00-15-00-00-03-0" FP-5191-0-00-15-00-00-03-0_CONN_PIN-MFG 424.16,146.91 r0 bottom
J5 "5191-0-00-15-00-00-03-0" FP-5191-0-00-15-00-00-03-0_CONN_PIN-MFG 1174.16,146.91 r0 bottom locked
J6 "5191-0-00-15-00-00-03-0" FP-5191-0-00-15-00-00-03-0_CONN_PIN-MFG 274.16,146.91 r0 bottom locked
J7 "5191-0-00-15-00-00-03-0" FP-5191-0-00-15-00-00-03-0_CONN_PIN-MFG 724.16,2149.36 r0 bottom locked
J8 "62000811121" Wurth_62000811121 684.79,46.91 r180 bottom locked
L1 "ERUC23-2R8K" FP-ERUC23-2R8K_SMT_IND_26MM8_13MM8-MFG 284.2,748.03 r90 top locked value=5.4uH
L2 "ERUC23-2R8K" FP-ERUC23-2R8K_SMT_IND_26MM8_13MM8-MFG 1164.96,748.03 r90 top locked value=5.4uH
L3 "742792602" 0603 144,1957.14 r0 top value="60 ohm"
L4 "742792602" 0603 416.17,2242.44 r180 top value="60 ohm"
Logo3 "CE Mark" CE_Mark_5mm 1328.5,1046 r90 bottom
Logo4 "Texas Instruments" TI_Stacked_Overlay_Small_Vertical 282,788 r180 bottom
Logo5 "FCC disclaimer" FCC_disclaimer_stacked 120,494 r90 bottom
Logo6 "WEEE logo" WEEE_Minimum 1082.68,1171.26 r180 bottom
MP1 "50M020040D006" FP-50M020040D006_M2_NYLON_SCREW-MFG 68.35,1630 r180 bottom
MP2 "50M020040D006" FP-50M020040D006_M2_NYLON_SCREW-MFG 1361.9,1348.43 r0 bottom
NT1 "Net-Tie" Net-Tie_10mil 461.71,2231.97 r0 bottom net-tie
Q1 "CSD13201W10" YZB0004AEAE 708.73,2253.89 r180 top value=12V
R1 "CRCW02014K70FKED" 0201_033 294.52,1852.18 r180 top value=4.70k
R2 "CRCW02014K70FKED" 0201_033 622.35,1853.19 r180 top value=4.70k
R3 "CRCW02014K70FKED" 0201_033 939.05,1852.31 r180 top value=4.70k
R4 "CRCW02014K70FKED" 0201_033 1256.81,1852.6 r180 top value=4.70k
R5 "CRCW02012K00FKED" 0201 228.05,1852.18 r0 top value=2.00k
R6 "CRCW02012K00FKED" 0201 555.11,1853.27 r0 top value=2.00k
R7 "CRCW02012K00FKED" 0201 872.59,1852.31 r0 top value=2.00k
R8 "CRCW02012K00FKED" 0201 1190.35,1852.6 r0 top value=2.00k
R9 "ERJ-1GNF1100C" FP-ERJ-1GNF1100C_0201-MFG 68.74,1349.86 r0 top value=110
R10 "CRCW02010000Z0ED" 0201_Silk 22.9,1396.99 r270 top value=0
R11 "ERJ-1GNF1100C" FP-ERJ-1GNF1100C_0201-MFG 399.71,1358.16 r0 top value=110
R12 "CRCW02010000Z0ED" 0201_Silk 380.84,1426.89 r270 top value=0
R13 "ERJ-1GNF1100C" FP-ERJ-1GNF1100C_0201-MFG 711.96,1326.29 r0 top value=110
R14 "CRCW02010000Z0ED" 0201_Silk 696.76,1397.21 r270 top value=0
R15 "ERJ-1GNF1100C" FP-ERJ-1GNF1100C_0201-MFG 1017.51,1361.95 r270 top value=110
R16 "CRCW02010000Z0ED" 0201_Silk 1016.66,1421.59 r270 top value=0
R17 "CRCW02010000Z0ED" 0201_Silk 118.3,1786.44 r0 top value=0
R18 "CRCW02010000Z0ED" 0201_Silk 459.7,1778.17 r0 top value=0
R19 "CRCW02010000Z0ED" 0201_Silk 811.97,1798.01 r0 top value=0
R20 "CRCW02010000Z0ED" 0201_Silk 1129.73,1798.3 r0 top value=0
R21 "CRCW02014K70FKED" 0201_033 49.15,1487.93 r90 top value=4.70k
R22 "CRCW02014K70FKED" 0201_033 384.79,1491.2 r90 top value=4.70k
R23 "CRCW02014K70FKED" 0201_033 698,1452.82 r270 top value=4.70k
R24 "CRCW02014K70FKED" 0201_033 1014.6,1500.4 r270 top value=4.70k
R27 "WSK1216L2000FEA" FP-WSK1216L2000FEA_1612-MFG 675.34,926.83 r0 top value=200µ
R28 "WSK1216L2000FEA" FP-WSK1216L2000FEA_1612-MFG 1346.24,767.63 r270 bottom value=200µ
R31 "WSK1216L2000FEA" FP-WSK1216L2000FEA_1612-MFG 704.55,237.63 r0 top locked value=200µ
R32 "WSK1216L2000FEA" FP-WSK1216L2000FEA_1612-MFG 1189.94,316.49 r180 bottom value=200µ
R33 "CRCW040210R0FKED" 0402 630.01,1078.74 r90 top value=10.0
R34 "CRCW040210R0FKED" 0402 640.26,390.15 r90 top value=10.0
R35 "CRCW040210R0FKED" 0402 1193.22,824.71 r180 bottom value=10.0
R36 "CRCW040210R0FKED" 0402 1255.2,469.08 r90 bottom value=10.0
R37 "CRCW0201100RFKED" 0201 399.99,1930.57 r0 bottom value=100
R38 "CRCW0201100RFKED" 0201 155.16,1889.41 r0 bottom value=100
R39 "CRCW0201100RFKED" 0201 458.82,1887.16 r90 bottom value=100
R40 "CRCW0201100RFKED" 0201 319.24,1879.39 r180 bottom value=100
R41 "CRCW040210R0FKED" 0402 745.37,1078.96 r90 top value=10.0
R42 "CRCW040210R0FKED" 0402 758.35,388.38 r90 top value=10.0
R43 "CRCW040210R0FKED" 0402 1194.36,709.68 r180 bottom value=10.0
R44 "CRCW040210R0FKED" 0402 1140.83,469.08 r90 bottom value=10.0
R45 "CRCW02010000Z0ED" 0201_Silk 748,104.69 r180 bottom value=0
R46 "CRCW0402100KDHEDP" 0402 521.65,1960.42 r0 bottom value=100k
R47 "RC0201FR-073K3L" 0201 90.41,1813.56 r270 bottom value=3.30k
R49 "RC0201FR-075K1L" 0201 541,1904.58 r90 bottom value=5.10k
R51 "CRCW02010000Z0ED" 0201_Silk 680.67,99.47 r0 top value=0
R55 "RC0201FR-7D2K2L" 0201 771.04,2235.12 r90 bottom value=2.20k
R56 "RC0201FR-7D2K2L" 0201 161.03,2223.16 r0 top value=2.20k
R58 "RC0201FR-7D2K2L" 0201 1093.27,2192.44 r270 top value=2.20k
R60 "RC0201FR-07768KL" 0201 1305.1,2018.09 r180 top value=768k
R61 "RC0201FR-07100KL" 0201 1340.48,1987.44 r180 top value=100k
R62 "RC0201FR-07100KL" 0201 1206.33,2105.91 r270 top value=100k
R65 "RC0201FR-075K62L" 0201 556.07,2022.79 r180 bottom value=5.62k
R66 "RC0201FR-0715RL" 0201_Silk 694.15,199.03 r180 bottom value=15.0
R67 "RC0201FR-071K43L" 0201 516.34,2009.82 r90 bottom value=1.43k
R68 "RC0201FR-0715RL" 0201_Silk 659.11,146.55 r0 bottom value=15.0
R69 "RC0201FR-071K13L" 0201 488.84,2009.11 r90 bottom value=1.13k
R70 "CRCW02010000Z0ED" 0201_Silk 794.75,98.13 r0 top value=0
R71 "CRCW02010000Z0ED" 0201_Silk 153.95,1695.77 r270 bottom value=0
R72 "CRCW02010000Z0ED" 0201_Silk 546.33,1703.51 r0 bottom value=0
R73 "CRCW02010000Z0ED" 0201_Silk 875.13,1702.84 r0 bottom value=0
R74 "CRCW02010000Z0ED" 0201_Silk 1188.09,1703.05 r0 bottom value=0
R75 "CRCW02010000Z0ED" 0201_Silk 173.59,1399.08 r90 bottom value=0
R76 "CRCW02010000Z0ED" 0201_Silk 499.89,1399.08 r90 bottom value=0
R77 "CRCW02010000Z0ED" 0201_Silk 754.29,1444.3 r0 bottom value=0
R78 "CRCW02010000Z0ED" 0201_Silk 1162.12,1398.51 r90 bottom value=0
R79 "CRCW02010000Z0ED" 0201_Silk 65.41,1408.72 r180 bottom value=0
R80 "CRCW02010000Z0ED" 0201_Silk 459.38,1398.27 r90 bottom value=0
R81 "CRCW02010000Z0ED" 0201_Silk 741.3,1394.54 r180 bottom value=0
R82 "CRCW02010000Z0ED" 0201_Silk 1091.03,1394.85 r180 bottom value=0
R85 "RC0201FR-7D2K2L" 0201 51.49,2016.16 r270 top value=2.20k
R86 "RC0201FR-7D2K2L" 0201 325.04,2186.62 r90 top value=2.20k
R87 "RC0201FR-073K6L" 0201 372.44,1879.26 r270 bottom value=3.60k
R88 "RC0201DR-0722KL" FP-RC0201DR-0722KL_0201-MFG 320.17,1908.41 r90 top value=22k
R91 "RC0201FR-075K49L" 0201 601.24,1879.26 r180 bottom value=5.49k
R92 "RC0201FR-079K53L" 0201 729.77,1887.16 r180 bottom value=9.53k
R93 "RC0201FR-071KL" 0201 261.64,1864.44 r180 bottom value=1.00k
R94 "RC0201FR-7D2KL" 0201 705.22,2005.41 r270 bottom value=2.00k
R95 "RC0201FR-7D1KL" 0201 732.82,2005.41 r270 bottom value=1.00k
R96 "CRCW02010000Z0ED" 0201_Silk 65.17,1443.24 r180 bottom value=0
R97 "CRCW02010000Z0ED" 0201_Silk 425.41,1469.03 r270 bottom value=0
R98 "CRCW02010000Z0ED" 0201_Silk 753.83,1473.09 r0 bottom value=0
R99 "CRCW02010000Z0ED" 0201_Silk 1073.06,1481.05 r0 bottom value=0
RT1 "TMP6131DECR" DEC0002A-MFG 131.14,1852.18 r90 bottom value=10k
RX "TP_SM_1MM" tp_custom 1367.8,2242.26 r0 top
TCK "TP_SM_1MM" tp_custom 1417.8,2242.26 r180 bottom
TDI "TP_SM_1MM" tp_custom 1267.8,2242.26 r0 top
TDO "TP_SM_1MM" tp_custom 1317.8,2242.26 r180 top
TMS "TP_SM_1MM" tp_custom 1367.8,2242.26 r180 bottom
TX "TP_SM_1MM" tp_custom 1417.8,2242.26 r0 top
U1 "ISO6521FREUR" REU0008A-MFG 265.3,1760.78 r180 bottom
U2 "ISO6521FREUR" REU0008A-MFG 591.95,1759.99 r180 bottom
U3 "ISO6521FREUR" REU0008A-MFG 907.56,1759.92 r180 bottom
U4 "ISO6521FREUR" REU0008A-MFG 1227.86,1759.57 r180 bottom
U5 "LMG3105R017" VBE0015A-MFG 285.83,1696.86 r0 top
U6 "LMG3105R017" VBE0015A-MFG 612.88,1697.95 r0 top
U7 "LMG3105R017" VBE0015A-MFG 930.36,1696.99 r0 top
U8 "LMG3105R017" VBE0015A-MFG 1248.12,1700.28 r0 top
U9 "LMG3105R017" VBE0015A-MFG 210.24,1460.07 r90 top
U10 "LMG3105R017" VBE0015A-MFG 537.3,1461.15 r90 top
U11 "LMG3105R017" VBE0015A-MFG 854.78,1460.19 r90 top
U12 "LMG3105R017" VBE0015A-MFG 1172.54,1460.48 r90 top
U13 "SN74LVC08ABQAR" BQA0014A-MFG 1055.62,1958.61 r90 top
U14 "INA241A5IDDF" DDF0008A-MFG 687.27,1191.95 r180 top
U15 "INA241A5IDDF" DDF0008A-MFG 700.44,500.35 r180 top
U16 "INA241A5IDDF" DDF0008A-MFG 1079.28,764.91 r90 bottom
U17 "INA241A5IDDF" DDF0008A-MFG 1181.82,583.56 r0 bottom
U18 "TMS320F28P550SJ6RSHR" RSH0056G-MFG 194.13,2084.26 r180 bottom
U19 "INA500AIDCKR" DCK0006A-MFG 632.25,1942.29 r180 bottom
U22 "TPSM365R6V5RDNR" RDN0011A-MFG 1345.18,2070.91 r0 bottom
U23 "TPS7A2033PDBVR" DBV0005A-MFG 1352.1,1867.36 r270 bottom

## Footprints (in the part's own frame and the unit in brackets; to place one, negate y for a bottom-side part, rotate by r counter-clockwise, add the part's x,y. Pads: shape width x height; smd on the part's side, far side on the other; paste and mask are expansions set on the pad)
0201 [mm] "Data from Kemet datasheet CC101_COM dated 7/28/11"
  rect 0.46x0.42 smd mask+0.048: 1(-0.33,0) 2(0.33,0)
  silkscreen extent -0.25,0.38 0.38,0.38, body extent -0.31,-0.16 0.31,0.16, height 0.26
0201_033 [mm] "SMD, 2-Leads, Height 0.33mm"
  rect 0.46x0.42 smd mask+0.048: 1(-0.33,0) 2(0.33,0)
  body extent -0.31,-0.16 0.31,0.16, height 0.33
0201_040 [mm] "SMD, 2-Leads, Height 0.33mm"
  rect 0.46x0.42 smd mask+0.048: 1(-0.33,0) 2(0.33,0)
  body extent -0.31,-0.16 0.31,0.16, height 0.4
0201_Silk [mm] "Data from Kemet datasheet CC101_COM dated 7/28/11"
  rect 0.46x0.42 smd mask+0.048: 1(-0.33,0) 2(0.33,0)
  silkscreen extent -0.75,-0.4 0.75,0.4, body extent -0.31,-0.16 0.31,0.16, height 0.26
0402 [mm] "0402 from SM-752 data"
  rect 0.8x0.6 smd: 1(-0.6,0) 2(0.6,0)
  silkscreen extent -1.22,-0.52 1.22,0.52, body extent -0.55,-0.3 0.55,0.3, height 0.6
0402_070 [mil] "SMD, 2-Leads, Body 1.2x0.7mm, Height 0.7mm"
  rect 15x24 smd: 1(-20,0) 2(20,0)
  body extent -24,-14 24,14, height 28
0402S [mil] "Based on C0402S footprint from PADS legacy"
  rect 15x24 smd: 1(-20,0) 2(20,0)
  body extent -22,-12 22,12, height 24
0603 [mm] "0603 from SM-752 data"
  rect 1x0.95 smd: 1(-0.8,0) 2(0.8,0)
  silkscreen extent -1.52,-0.69 1.52,0.69, body extent -0.87,-0.47 0.87,0.47, height 1
1210_270 [mm] "1210"
  rect 1.3x2.7 smd: 1(-1.45,0) 2(1.45,0)
  silkscreen extent -2.32,-1.57 2.32,1.57, body extent -1.7,-1.35 1.7,1.35, height 2.7
BQA0014A-MFG [mm] "Recommended Land Pattern"
  rrect40% 0.25x0.6 smd paste+0 mask+0: 1(-0.25,1.4) 7(-0.25,-1.4) 8(0.25,-1.4) 14(0.25,1.4)
  rrect40% 0.6x0.25 smd paste+0 mask+0: 2(-1.15,1) 3(-1.15,0.5) 4(-1.15,0) 5(-1.15,-0.5) 6(-1.15,-1) 9(1.15,-1) 10(1.15,-0.5) 11(1.15,0) 12(1.15,0.5) 13(1.15,1)
  rrect10% 1x1.5 smd paste-1000 mask+0: 15(0,0)
  silkscreen extent -1.3,-1.55 1.3,2.15, body extent -1.25,-1.5 1.25,1.5, height 0.8
CE_Mark_5mm [mil] "Minimum text height for CE Mark"
  silkscreen extent -138,-98 138,98
DBV0005A-MFG [mm]
  rrect17% 1.1x0.6 smd paste+0 mask+0: 1(-1.3,0.95) 2(-1.3,0) 3(-1.3,-0.95) 4(1.3,-0.95) 5(1.3,0.95)
  silkscreen extent -1.49,-1.53 0.87,1.84, body extent -1.4,-1.45 1.4,1.45, height 1.45
DCK0006A-MFG [mm] "Recommended Land Pattern"
  rrect25% 0.9x0.4 smd paste+0 mask+0: 1(-1.1,0.65) 2(-1.1,0) 3(-1.1,-0.65) 4(1.1,-0.65) 5(1.1,0) 6(1.1,0.65)
  silkscreen extent -1.28,-1.07 0.27,1.52, body extent -1.1,-1 1.1,1, height 1.1
DDF0008A-MFG [mm]
  rrect22% 1.05x0.45 smd paste+0 mask+0: 1(-1.3,0.975) 2(-1.3,0.325) 3(-1.3,-0.325) 4(-1.3,-0.975) 5(1.3,-0.975) 6(1.3,-0.325) 7(1.3,0.325) 8(1.3,0.975)
  silkscreen extent -2.5,-1.48 0.4,1.48, body extent -1.92,-1.73 1.92,1.73, height 0.25
DEC0002A-MFG [mm]
  rrect40% 0.25x0.5 smd paste-1000 mask+0: 1(-0.325,0) 2(0.325,0)
  silkscreen extent -1.15,-0.65 0.53,0.08, body extent -0.5,-0.3 0.5,0.3, height 0.5
FCC_disclaimer_stacked [mil]
Fiducial10-20 [mm]
  round 1 smd mask+0.5: 1(0,0)
  Top Layer keep-out circle w1.178: c0,0 r0.5
FP-50M020040D006_M2_NYLON_SCREW-MFG [mm]
  round 2.4 hole 2.4 unplated paste-2539.97 mask+0.127: ""(0,0)
  body extent -1.9,-1.9 1.9,1.9, height 2.15
FP-250R05L101FV4T_0201-MFG [mil]
  rrect39% 10x15 smd paste+0 mask+0: 1(-8.5,0) 2(8.5,0)
  silkscreen extent -12,-23 12,23, body extent -12,-6 12,6, height 13
FP-5191-0-00-15-00-00-03-0_CONN_PIN-MFG [mil] "Recommended Land Pattern"
  round 97.48 hole 64.02 paste-99999 mask+0: 1(0,0)
  body extent -46,-47 46,46, height 448
FP-06031C104K4T2A_0603-IPC_C [mil]
  rrect12% 31.75x34.18 smd paste+0 mask+0: 1(-24.64,0) 2(24.64,0)
  silkscreen extent -41,35 41,35, body extent -31,-16 31,16, height 37
FP-12061C225KAT2A_1206-IPC_C [mil]
  rrect9% 43.49x67.17 smd paste+0 mask+0: 1(-51.21,0) 2(51.21,0)
  silkscreen extent -18,-35 18,35, body extent -63,-31 63,31, height 70
FP-C1608X7R2A105K080AC_0603-MFG [mm] "Recommended Land Pattern"
  rrect14% 0.7x0.7 smd paste+0 mask+0: 1(-0.7,0) 2(0.7,0)
  silkscreen extent -0.9,-0.55 0.9,0.77, body extent -0.8,-0.4 0.8,0.4, height 1
FP-C2012X5R2A475K125AC_0805-MFG [mm]
  rrect13% 0.8x1.05 smd paste+0 mask+0: 1(-0.925,0) 2(0.925,0)
  silkscreen extent -0.15,-0.75 0.15,0.75, body extent -1,-0.63 1,0.63, height 1.5
FP-C3225X7R2A106K250AC_1210-MFG [mm]
  rrect9% 1.1x2.2 smd paste+0 mask+0: 1(-1.65,0) 2(1.65,0)
  silkscreen extent -0.72,-1.43 0.72,1.43, body extent -1.6,-1.25 1.6,1.25, height 2.85
FP-ERJ-1GNF1100C_0201-MFG [mm] "Recommended Land Pattern"
  rrect40% 0.25x0.3 smd paste+0 mask+0: 1(-0.3,0) 2(0.3,0)
  silkscreen extent -0.32,-0.29 0.32,0.29, body extent -0.3,-0.15 0.3,0.15, height 0.26
FP-ERUC23-2R8K_SMT_IND_26MM8_13MM8-MFG [mm]
  rrect3% 3.7x5.15 smd paste+0 mask+0: 1(-3.95,4.425) 2(11.85,4.425) 3(3.95,-4.425) 4(-11.85,-4.425)
  silkscreen extent -13.9,-7.05 13.4,7.05, body extent -13.8,-7.15 13.8,7.15, height 0.25
FP-GRT155R71A474KE01D_0402-MFG [mm] "Recommended Land Pattern"
  rrect25% 0.4x0.5 smd paste+0 mask+0: 1(-0.4,0) 2(0.4,0)
  silkscreen extent -0.5,0.62 0.5,0.62, body extent -0.7,-0.38 0.7,0.38, height 0.25
FP-GRT188R61C106KE13D_0603-MFG [mm] "Recommended Land Pattern"
  rrect13% 0.75x0.9 smd paste+0 mask+0: 1(-0.775,0) 2(0.775,0)
  silkscreen extent -0.87,-0.85 0.87,0.85, body extent -0.8,-0.4 0.8,0.4, height 0.95
FP-RC0201DR-0722KL_0201-MFG [mm] "Recommended Land Pattern"
  rrect29% 0.35x0.4 smd paste+0 mask+0: 1(-0.325,0) 2(0.325,0)
  silkscreen extent -0.32,-0.42 0.32,0.35, body extent -0.3,-0.15 0.3,0.15, height 0.26
FP-WSK1216L2000FEA_1612-MFG [mm]
  rrect14% 1.495x0.7 smd paste+0 mask+0: 1(-1.052,1.725) 2(1.052,1.725)
  rrect7% 1.495x2.95 smd paste+0 mask+0: 3(-1.052,-0.6) 4(1.052,-0.6)
  silkscreen extent -2.47,-2.45 1.55,2.45, body extent -1.9,-2.17 1.9,2.17, height 0.25
Net-Tie_10mil [mil] "10mil net tie, no solder mask opening, no solder paste"
  rect 10x10 smd paste-5 mask-5: 1(-10,0) 2(10,0)
  Top Layer region: -6,5 6,5 6,-5 -6,-5
RDN0011A-MFG [mm]
  rrect42% 1.2x0.475 smd paste-1000 mask-1000: 1(-1.4,1.962) 8(1.4,1.962)
  rrect57% 1.2x0.35 smd paste-1000 mask-1000: 2(-1.4,1.15) 3(-1.4,0.65) 6(1.4,0.65) 7(1.4,1.15)
  rrect13% 1.6x2.15 smd paste-1000 mask-1000: 4(-1.2,-1) 5(1.2,-1)
  rrect57% 0.35x0.9 smd paste-1000 mask-1000: 9(0.5,2.05) 11(-0.5,2.05)
  round 0.504 smd paste-1000 mask-1000: 10(0,1.005)
  silkscreen extent -2.53,-2.42 2.1,2.6, body extent -1.75,-2.25 1.75,2.25, height 2.1
REU0008A-MFG [mm]
  rrect40% 0.6x0.25 smd paste+0 mask+0: 1(-1.4,0.75) 2(-1.4,0.25) 3(-1.4,-0.25) 4(-1.4,-0.75) 5(1.4,-0.75) 6(1.4,-0.25) 7(1.4,0.25) 8(1.4,0.75)
  silkscreen extent -1.64,-1.05 0.72,1.4, body extent -1.5,-1 1.5,1, height 1.05
RSH0056G-MFG [mm]
  rrect50% 0.75x0.2 smd paste+0 mask+0: 1(-3.325,2.6) 2(-3.325,2.2) 3(-3.325,1.8) 4(-3.325,1.4) 5(-3.325,1) 6(-3.325,0.6) 7(-3.325,0.2) 8(-3.325,-0.2) 9(-3.325,-0.6) 10(-3.325,-1) 11(-3.325,-1.4) 12(-3.325,-1.8) 13(-3.325,-2.2) 14(-3.325,-2.6) 29(3.325,-2.6) 30(3.325,-2.2) 31(3.325,-1.8) 32(3.325,-1.4) 33(3.325,-1) 34(3.325,-0.6) 35(3.325,-0.2) 36(3.325,0.2) 37(3.325,0.6) 38(3.325,1) 39(3.325,1.4) 40(3.325,1.8) 41(3.325,2.2) 42(3.325,2.6)
  rrect50% 0.2x0.75 smd paste+0 mask+0: 15(-2.6,-3.325) 16(-2.2,-3.325) 17(-1.8,-3.325) 18(-1.4,-3.325) 19(-1,-3.325) 20(-0.6,-3.325) 21(-0.2,-3.325) 22(0.2,-3.325) 23(0.6,-3.325) 24(1,-3.325) 25(1.4,-3.325) 26(1.8,-3.325) 27(2.2,-3.325) 28(2.6,-3.325) 43(2.6,3.325) 44(2.2,3.325) 45(1.8,3.325) 46(1.4,3.325) 47(1,3.325) 48(0.6,3.325) 49(0.2,3.325) 50(-0.2,3.325) 51(-0.6,3.325) 52(-1,3.325) 53(-1.4,3.325) 54(-1.8,3.325) 55(-2.2,3.325) 56(-2.6,3.325)
  rrect2% 5.3x5.3 smd paste-1000 mask+0: 57(0,0)
  silkscreen extent -4.16,-3.55 3.55,3.55, body extent -3.5,-3.5 3.5,3.5, height 1
TI_Stacked_Overlay_Small_Vertical [mil]
  silkscreen extent -66,-288 69,288
tp_custom [mil]
  oval 25x100 smd: 1(0,0)
VBE0015A-MFG [mm] "Recommended Land Pattern"
  round 0.265 smd paste+0 mask-1000: 1(-1.675,2.875) 11(1.675,2.875)
  rrect40% 0.7x0.25 smd paste+0 mask-1000: 2(-1.85,2.325) 3(-1.85,1.825) 4(-1.85,1.325) 5(-1.85,0.825) 8(1.85,1.325) 9(1.85,1.825) 10(1.85,2.325)
  rrect11% 1.9x3.95 smd paste-1000 mask-1000: 6(-1.3,-1.525) 7(1.3,-1.525)
  rrect40% 0.25x0.7 smd paste+0 mask-1000: 12(0.575,3.1) 13(0.075,3.1) 14(-0.425,3.1) 15(-0.925,3.1)
  Top Layer region: 2.15,2.7 2.169,2.704 2.185,2.715 2.196,2.731 2.2,2.75 2.2,2.75 2.2,2.9 2.193,2.925 2.175,2.943 2.15,2.95 2.15,2.95 1.85,2.95 1.812,2.958 1.779,2.979 1.758,3.012 1.75,3.05 1.75,3.05 1.75,3.4 1.746,3.419 1.735,3.435 1.719,3.446 1.7,3.45 1.7,3.45 1.55,3.45 1.531,3.446 1.515,3.435 1.504,3.419 1.5,3.4 1.5,3.4 1.5,2.75 1.504,2.731 1.515,2.715 1.531,2.704 1.55,2.7 1.55,2.7
  Top Layer region: -2.15,2.7 -2.169,2.704 -2.185,2.715 -2.196,2.731 -2.2,2.75 -2.2,2.75 -2.2,2.9 -2.193,2.925 -2.175,2.943 -2.15,2.95 -2.15,2.95 -1.85,2.95 -1.812,2.958 -1.779,2.979 -1.758,3.012 -1.75,3.05 -1.75,3.05 -1.75,3.4 -1.746,3.419 -1.735,3.435 -1.719,3.446 -1.7,3.45 -1.7,3.45 -1.55,3.45 -1.531,3.446 -1.515,3.435 -1.504,3.419 -1.5,3.4 -1.5,3.4 -1.5,2.75 -1.504,2.731 -1.515,2.715 -1.531,2.704 -1.55,2.7 -1.55,2.7
  silkscreen extent -2.87,-3.55 2.35,3.55, body extent -2.35,-3.6 2.35,3.55, height 0.25
WEEE_Minimum [mil] "WEEElie bin"
  silkscreen extent -95,-172 99,104
Wurth_62000811121 [mm] "Header, 2mm, 8x1,TH"
  rect 1.3x1.3 hole 0.8: 1(-7,0)
  round 1.3 hole 0.8: 2(-5,0) 3(-3,0) 4(-1,0) 5(1,0) 6(3,0) 7(5,0) 8(7,0)
  silkscreen extent -8,-1 8,1.5, body extent -8,-1 8,1, height 6
YZB0004AEAE [mm] "BGA, 4-Balls, Body 0.96x0.964mm, Pitch 0.5mm"
  round 0.275 smd paste-0.14 mask+0.04: A1(-0.25,0.25) A2(0.25,0.25) B1(-0.25,-0.25) B2(0.25,-0.25)
  silkscreen extent -0.65,-0.65 0.65,0.65, body extent -0.5,-0.5 0.5,0.5, height 0.63

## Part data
3V3 GND RX TCK TDI TDO TMS TX: library part CMP-0003825-1, "1mm Test Point, SMT", Manufacturer=Any
C7 C9 C10 C11 C12: library part CMP-0096021-1, "10 µF ±10% 100V Ceramic Capacitor X7R 1210 (3225 Metric)", Digikey Part Number=445-C3225X7R2A106K250ACCT-ND, Manufacturer=TDK, Mouser Part Number=810-C3225X7R2A106K25, Operating Temperature Range="-55°C to +125°C", TempCo=15%, Temperature Characteristic=X7R, Tolerance_%=10%, ValueDisplayed=10uF
C13 C14 C15 C16 C17 C18 C19 C20 C21 C22 C23 C24 C33 C34 C35 C36 C37 C38 C39 C40 C41 C42 C43 C44: library part CMP-0098058-1, "4.7 µF ±10% 100V Ceramic Capacitor X5R 0805 (2012 Metric)", Digikey Part Number=445-C2012X5R2A475K125ACCT-ND, Manufacturer=TDK, Mouser Part Number=810-C2012X5R2A475K12, Operating Temperature Range="-55°C to +85°C", TempCo=15%, Temperature Characteristic=X5R, Tolerance_%=10%, ValueDisplayed=4.7uF
C45 C46 C47 C48 C49 C50 C51 C52 C81 C82 C83 C84 C94 C95 C144 C145 C146 C149 C152 C153 C154: library part CMP-0064970-1, "CAP, CERM, 0.1 uF, 16 V,+/- 10%, X7R, 0201", Cap_Case=0201, Manufacturer=MuRata, Supplier Part Number 1=81-GRM033Z71C104KE4D, TempCo=X7R, Tolerance_%=10%, Value1=Unknown, Value2=16V, ValueDisplayed=0.1uF
C53 C54 C55 C56: library part CMP-0124903-1, "Multi-Layer Ceramic Capacitor 470nF 10V X7R ±10% 0402 Paper T/R", Manufacturer=Murata, Operating Temperature Range="-55°C to +125°C", TempCo=0.15, Temperature Characteristic=X7R, Tolerance_%=10%, ValueDisplayed=470nF
C57 C58 C59 C60 C61 C62 C63 C64 C65: library part CMP-0079201-1, "CAP, CERM, 10 µF, 50 V,+/- 10%, X7R, 1210", Cap_Case=1210, Manufacturer="Samsung Electro-Mechanics", Supplier Part Number 1=1276-3388-1-ND, TempCo=X7R, Tolerance_%=10%, Value1="0.005 ohm", Value2=50V, ValueDisplayed=10µF
C66 C67 C68 C69 C120 C123 C124: library part CMP-0006275-2, "CAP, CERM, 2.2 uF, 16 V, +/- 10%, X5R, 0402", Cap_Case=0402, Manufacturer=TDK, Supplier Part Number 1=445-9085-1-ND, TempCo=X5R, Tolerance_%=10%, Value1=Unknown, Value2=16V, ValueDisplayed=2.2uF
C70 C71 C72 C73 C89 C90 C91 C92: library part CMP-0009762-1, "CAP, CERM, 100 pF, 25 V, +/- 5%, C0G/NP0, 0201", Cap_Case=0201, Manufacturer=MuRata, Supplier Part Number 1=81-GRM033R71E101JA1D, TempCo=C0G/NP0, Tolerance_%=5%, Value1=Unknown, Value2=25V, ValueDisplayed=100pF
C85 C86 C87 C88: library part CMP-0006641-2, "CAP, CERM, 0.1 uF, 16 V, +/- 10%, X7R, 0402", Cap_Case=0402, Manufacturer=MuRata, Supplier Part Number 1=490-3261-1-ND, TempCo=X7R, Tolerance_%=10%, Value1=Unknown, Value2=16V, ValueDisplayed=0.1uF
C93 C98: library part CMP-0860981-1, "CAP, CERM, 0.1 µF, 16 V,+/- 10%, X7R, 0201", Cap_Case=0201, Manufacturer="Passive Plus", TempCo=X7R, Tolerance_%=10%, Value2=16V, ValueDisplayed=0.1µF
C96: library part CMP-0092339-1, "100pF ±1% 25V Ceramic Capacitor C0G, NP0 0201 (0603 Metric)", Digikey Part Number=250R05L101FV4T-ND, Manufacturer=Johanson, Mouser Part Number=609-250R05L101FV4T, Operating Temperature Range="-55°C to +125°C", TempCo=30ppm/°C, Temperature Characteristic=NP0, Tolerance_%=1%, ValueDisplayed=100pF
C97 C107 C111: library part CMP-0009745-1, "CAP, CERM, 1000 pF, 16 V, +/- 10%, X7R, 0201", Cap_Case=0201, Manufacturer=MuRata, Supplier Part Number 1=GRM033R71C102KA01D-ND, TempCo=X7R, Tolerance_%=10%, Value1=Unknown, Value2=16V, ValueDisplayed=1000pF
C103: library part CMP-0009656-3, "CAP, CERM, 1 uF, 10 V, +/- 20%, X5R, 0201", Cap_Case=0201, Manufacturer="Samsung Electro-Mechanics", TempCo=X5R, Tolerance_%=20%, Value1=Unknown, Value2=10V, ValueDisplayed=1uF
C106 C114 C147 C148 C150 C151: library part CMP-0081160-1, "CAP, CERM, 2.2 µF, 10 V,+/- 10%, X5R, 0201", Cap_Case=0201, Manufacturer=MuRata, Supplier Part Number 1=490-13227-1-ND, TempCo=X5R, Tolerance_%=10%, Value2=10V, ValueDisplayed=2.2µF
C108: library part CMP-0009744-1, "CAP, CERM, 100 pF, 16 V, +/- 10%, X7R, 0201", Cap_Case=0201, Manufacturer=MuRata, Supplier Part Number 1=GRM033R71C101KA01D-ND, TempCo=X7R, Tolerance_%=10%, Value1=Unknown, Value2=16V, ValueDisplayed=100pF
C118: library part CMP-0092494-1, "2.2uF @ ±10% 100V Ceramic Capacitor X7R 15% 1206 (3216 Metric)", Digikey Part Number=478-10860-1-ND, Manufacturer=AVX, Mouser Part Number=581-12061C225KAT2A, Operating Temperature Range="-55°C to +125°C", TempCo=15%, Temperature Characteristic=X7R, Tolerance_%=10%, ValueDisplayed=2.2uF
C119: library part CMP-0094779-1, "Cap Ceramic 100nF 100V X7R 10% SMD 0603 125°C Paper T/R", Digikey Part Number=478-06031C104K4T2ACT-ND, Manufacturer="KYOCERA AVX", Mouser Part Number=581-06031C104K4T2A, Operating Temperature Range="-55°C to +125°C", TempCo=15%, Temperature Characteristic=X7R, Tolerance_%=10%, ValueDisplayed=100nF
C121 C122 C125: library part CMP-0126314-1, "Multi-Layer Ceramic Capacitor 10uF 16V X5R ±10% 0603 Paper T/R", Manufacturer=Murata, Operating Temperature Range="-55°C to +85°C", TempCo=15%, Temperature Characteristic=X5R, Tolerance_%=10%, ValueDisplayed=10uF
C127 C128 C129 C130 C131 C132 C133 C134 C135 C136 C137 C138 C139 C140 C141 C142: library part CMP-0125726-1, "1 µF ±10% 100V Ceramic Capacitor X7R 0603 (1608 Metric)", Digikey Part Number=445-C1608X7R2A105K080ACCT-ND, Manufacturer=TDK, Mouser Part Number=810-C1608X7R2A105K08, Operating Temperature Range="-55°C to +125°C", TempCo=15%, Temperature Characteristic=X7R, Tolerance_%=10%, ValueDisplayed=1uF
C143: library part CMP-0006565-2, "CAP, CERM, 10 uF, 10 V, +/- 20%, X5R, 0402", Cap_Case=0402, Manufacturer=MuRata, TempCo=X5R, Tolerance_%=20%, Value1=Unknown, Value2=10V, ValueDisplayed=10uF
C155: library part CMP-0006825-5, "CAP, CERM, 2.2 uF, 16 V, +/- 20%, X5R, 0603", Cap_Case=0603, Manufacturer="Wurth Elektronik", Supplier Part Number 1=732-7915-1-ND, TempCo=X5R, Tolerance_%=20%, Value1=Unknown, Value2=16V, ValueDisplayed=2.2uF
FID1 FID2 FID3 FID4 FID5 FID6: library part CMP-0077181-1, "Fiducial mark.  There is nothing to buy or mount.", Manufacturer=N/A
J1 J2 J3 J4 J5 J6 J7: library part CMP-0125276-1, "PC Pin Terminal Connector Through Hole Gold 0.060\" (1.52mm) Dia", Digikey Part Number=54-5191-0-00-15-00-00-03-0-ND, Manufacturer=Mill-Max, Mouser Part Number=575-5191000150000030, Operating Temperature Range="-55°C to +125°C"
J8: library part CMP-0054807-1, "Header, 2 mm, 8x1, Gold,TH", Color=Black, Manufacturer="Wurth Elektronik"
L1 L2: library part CMP-0123560-1, "Unshielded 2 Coil Inductor Array Inductance - Connected in Series 5.4 µH Inductance - Connected in Parallel 1.25mOhm DC Resistance (DCR) - Parallel Nonstandard, 4 Lead", Digikey Part Number=495-ERUC23-2R8KCT-ND, Manufacturer=TDK, Mouser Part Number=871-ERUC23-2R8K, Operating Temperature Range="-40°C to +150°C", Test Frequency=100kHz, Tolerance_%=10%
L3 L4: library part CMP-0003173-2, "Ferrite Bead, 60 ohm @ 100 MHz, 3 A, 0603", Manufacturer="Wurth Elektronik", Supplier Part Number 1=732-4660-1-ND, Value1="0.04 ohm", Value2=3A, ValueDisplayed="60 ohm"
Logo3: library part CMP-0074844-1
Logo4: library part CMP-0074838-1, "Texas Instrument Corporate Signature"
Logo5: library part CMP-0074847-1, "FCC_disclaimer"
Logo6: library part CMP-0074769-1
MP1 MP2: library part CMP-0086543-1, "Nylon M2 X .4 Cheese Head Slotted Machine Screw", Manufacturer="Essentra Components"
NT1: library part CMP-0078142-6, "Single point connection between nets.", Manufacturer=N/A
Q1: library part CMP-0000192-1, "MOSFET, N-CH, 12 V, 1.6 A, YZB0004AEAE (DSBGA-4)", Alternate Manufacturer=None, Manufacturer="Texas Instruments", Supplier Part Number 1=CSD13201W10-ND, Value1=0.02, Value2="2.3 nC"
R1 R2 R3 R4 R21 R22 R23 R24: library part CMP-0027280-3, "RES, 4.70 k, 1%, 0.05 W, 0201", Manufacturer=Vishay-Dale, Power_W=50mW, Supplier Part Number 1=541-4.70KAABCT-ND, TempCo="100 ppm/C", Tolerance_%=1%, Value2=0.05W, Value_Code=4k70, ValueDisplayed=4.70k
R5 R6 R7 R8: library part CMP-0027271-3, "RES, 2.00 k, 1%, 0.05 W, 0201", Manufacturer=Vishay-Dale, Power_W=50mW, Supplier Part Number 1=541-2.00KAABCT-ND, TempCo="100 ppm/C", Tolerance_%=1%, Value2=0.05W, Value_Code=2k00, ValueDisplayed=2.00k
R9 R11 R13 R15: library part CMP-0126316-1, "Res Thick Film 0201 110 Ohm 1% 0.05W(1/20W) ±200ppm/C Pad SMD Automotive T/R", Digikey Part Number=P122673CT-ND, Manufacturer="Panasonic Electronic Components", Mouser Part Number=667-ERJ-1GNF1100C, Operating Temperature Range="-55°C to +125°C", Power_W=50mW, TempCo=200ppm/°C, Tolerance_%=1%
R10 R12 R14 R16 R17 R18 R19 R20 R45 R51 R70 R71 R72 R73 R74 R75 R76 R77 R78 R79 R80 R81 R82 R96 R97 R98 R99: library part CMP-0027008-4, "RES, 0, 5%, 0.05 W, 0201", Manufacturer=Vishay-Dale, Power_W=50mW, Supplier Part Number 1=72M6743, TempCo=ppm/C, Tolerance_%=5%, Value2=0.05W, Value_Code=0000, ValueDisplayed=0
R27 R28 R31 R32: library part CMP-0037612-1, "0.2 mOhms ±1% 3W Chip Resistor Wide 1612 (3831 Metric), 1216 Anti-Sulfur, Automotive AEC-Q200, Current Sense, Pulse Withstanding Metal Element", Digikey Part Number=541-WSK1216L2000FEACT-ND, Manufacturer="Vishay Dale", Mouser Part Number=71-WSK1216L2000FEA, Operating Temperature Range="-65°C to +170°C", Power_W=8W, TempCo=35ppm/°C, Tolerance_%=1%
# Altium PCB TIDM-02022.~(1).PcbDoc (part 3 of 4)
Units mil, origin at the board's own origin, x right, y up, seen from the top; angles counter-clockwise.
Board outline 1448.82 x 2299.21 mil, 16 copper layers (Top Layer, GND1, PWR1, PWR2, PWR3, GND2, GND3/SIG1, SIG2, SIG3, GND3/SIG4, GND5, PWR4, PWR5, GND6, GND7, Bottom Layer), stack 148.806 mil thick; 257 components, 138 nets, 739 pads, 1147 vias.

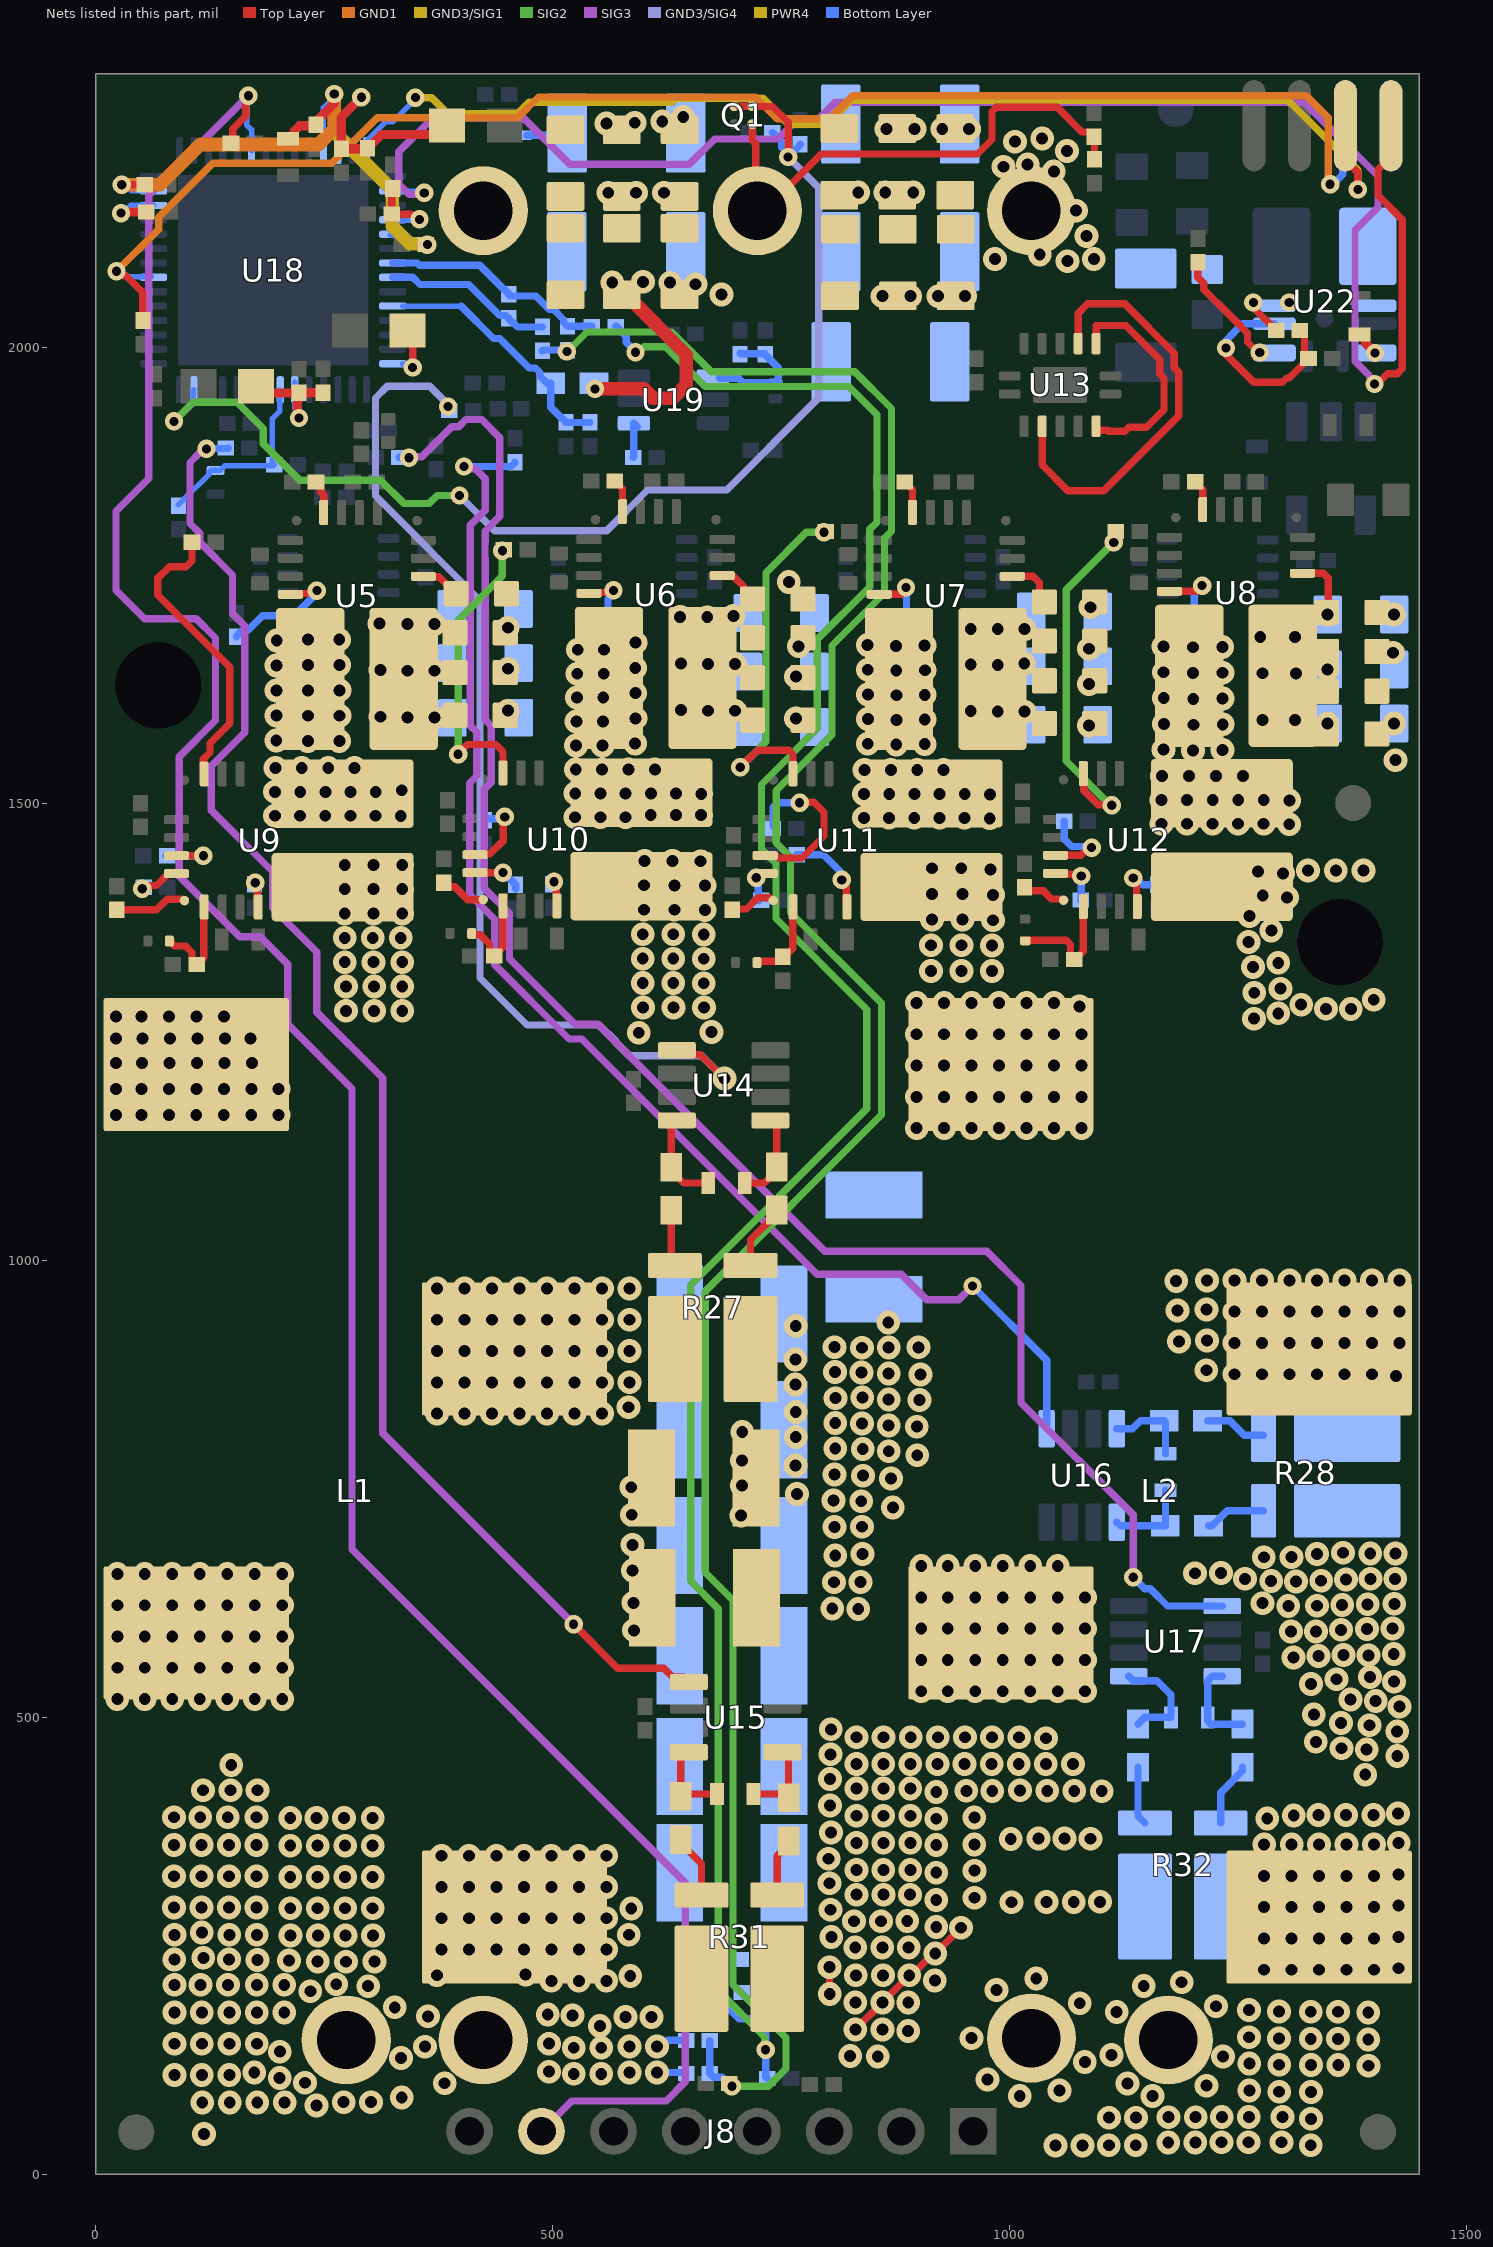
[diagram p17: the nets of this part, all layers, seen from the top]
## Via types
v1: diameter 26, hole 13, Top Layer to Bottom Layer, tented both sides, 921 vias
v2: diameter 20, hole 10, Top Layer to Bottom Layer, tented both sides, 226 vias

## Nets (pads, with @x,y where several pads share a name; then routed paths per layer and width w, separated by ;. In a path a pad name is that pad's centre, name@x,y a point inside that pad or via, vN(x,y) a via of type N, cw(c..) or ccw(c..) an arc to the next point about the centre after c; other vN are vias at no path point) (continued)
MCU_TMS: R85.1 TMS.1 U18.35 | length 1701.8
  Top Layer w8: v2(22.71,2083) 25.95,2083 30.77,2078.18 33,2078.18 51.49,2059.7 R85.1@51.49,2029.15
  GND1 w8: v2(22.71,2083) 68.81,2129.1 68.81,2142.16 127.94,2201.29 258.27,2201.29 308.12,2251.14 461.98,2251.14 484.69,2273.84 721.77,2273.84 745.65,2249.96 803.5,2249.96 828.65,2275.11 1325.03,2275.11 1349.09,2251.05 1349.09,2180.34 v2(1351.17,2178.27)
  Bottom Layer w6: v2(22.71,2083) 26.49,2083 32.67,2076.82 U18.35@60.79,2076.82
  Bottom Layer w8: v2(1351.17,2178.27) 1354.27,2178.27 1364.96,2188.95 1364.96,2241.91 TMS.1@1367.8,2244.76
MCU_VREFHI: C155.2 U18.14 | length 43.1
  Top Layer w8: C155.2@342.47,2004.09 346.35,2004.09 346.82,2003.62 v2(346.82,1977.67)
  Bottom Layer w6: U18.14@335.93,1981.83 336.8,1980.96 339.75,1980.96 343.03,1977.67 v2(346.82,1977.67)
NetC70_1: C70.1 R9.2 U9.2 | length 114.1
  Top Layer w8: R9.2@80.55,1349.86 80.55,1348.88 81.47,1347.96 82.55,1347.96 86.16,1344.35 98.37,1344.35 105.4,1337.32 105.4,1328.35 109.66,1324.08 C70.1@110.32,1324.08 111.11,1324.08 118.3,1331.27 118.3,1386.83 U9.2@118.71,1387.23 ; R9.2@81.44,1351.77 R9.2@81.95,1351.26
NetC71_1: C71.1 R11.2 U10.2 | length 92.6
  Top Layer w8: R11.2@411.52,1358.16 411.52,1357.8 412.44,1356.87 420.88,1356.87 431.07,1346.68 431.07,1340.59 C71.1@433.07,1338.58 ; C71.1@436,1333.44 445.36,1342.81 445.36,1388.32 U10.2@445.76,1388.32
NetC72_1: C72.1 R13.2 U11.2 | length 90.6
  Top Layer w8: R13.2@723.77,1326.29 723.77,1326.81 724.69,1327.73 747.72,1327.73 751.98,1332 C72.1@751.98,1332.53 ; C72.1@753.48,1332.48 762.84,1341.85 762.84,1387.36 U11.2@763.24,1387.36
NetC73_1: C73.1 R15.2 U12.2 | length 132.4
  Top Layer w8: R15.2@1017.51,1350.14 1018.13,1350.76 1062.37,1350.76 1067.06,1346.07 1067.06,1333.44 C73.1@1070.84,1329.66 1075.11,1333.92 1076.21,1333.92 1080.9,1338.61 U12.2@1080.9,1387.55
NetC85_1: C85.1 R33.2 U14.8 | length 104.3
  Top Layer w8: U14.8@636.09,1153.56 634.87,1153.56 630.01,1148.7 R33.2@630.01,1102.36 630.01,1098.42 643.4,1085.04 C85.1@670.42,1085.04
NetC85_2: C85.2 R41.2 U14.1 | length 99.6
  Top Layer w8: C85.2@710.42,1085.04 731.76,1085.04 745.37,1098.64 R41.2@745.37,1102.58 745.37,1148.7 740.51,1153.56 U14.1@738.45,1153.56
NetC86_1: C86.1 R34.2 U15.8 | length 95.1
  Top Layer w8: U15.8@649.25,461.96 645.11,461.96 640.26,457.1 R34.2@640.26,413.77 642.7,416.22 C86.1@679.97,416.22
NetC86_2: C86.2 R42.2 U15.1 | length 94
  Top Layer w8: C86.2@719.97,416.22 754.13,416.22 R42.2@758.35,412 758.35,457.1 753.49,461.96 U15.1@751.62,461.96
NetC87_1: C87.1 R35.2 U16.8 | length 92.2
  Bottom Layer w8: U16.8@1117.67,816.09 1134.86,816.09 1143.48,824.71 R35.2@1169.6,824.71 1170.87,823.45 C87.1@1170.87,788.57
NetC87_2: C87.2 R43.2 U16.1 | length 93.7
  Bottom Layer w8: U16.1@1117.67,713.73 1121.72,709.68 R43.2@1170.73,709.68 1170.87,709.81 C87.2@1170.87,748.57
NetC88_1: C88.1 R36.2 U17.8 | length 101.7
  Bottom Layer w8: U17.8@1233,545.18 1221.9,545.18 1217.04,540.32 C88.1@1217.04,500.12 1217.04,496.21 1220.54,492.71 R36.2@1255.2,492.71
NetC88_2: C88.2 R44.2 U17.1 | length 118.9
  Bottom Layer w8: U17.1@1130.64,545.18 1135.5,540.32 1161.72,540.32 1177.04,525 C88.2@1177.04,500.12 1148.25,500.12 R44.2@1140.83,492.71
NetC96_2: C96.2 R94.2 R95.2 U19.1 | length 129
  Bottom Layer w8: U19.1@682.35,1966.64 683.23,1965.76 703.55,1965.76 708.39,1960.92 C96.2@743.57,1960.92 ; R94.2@705.22,1993.39 705.7,1992.91 732.33,1992.91 R95.2@732.82,1992.42 ; R95.2@732.75,1991.7 747.09,1977.36 747.09,1961.53 C96.2@746.16,1960.6
NetC120_1: C120.1 U22.8 | length 29.9
  Top Layer w10: C120.1@1383.08,2013.79 1387.58,2013.79 1390.08,2011.29 1390.08,2003.88 v2(1400.3,1993.66)
NetR5_2: R5.2 U5.15 | length 37.2
  Top Layer w8: R5.2@241.04,1852.18 241.83,1852.18 246.1,1847.91 246.1,1841.58 249.41,1838.27 U5.15@249.41,1818.91
NetR6_2: R6.2 U6.15 | length 36.7
  Top Layer w8: R6.2@568.1,1853.27 576.47,1844.9 U6.15@576.47,1820
NetR7_2: R7.2 U7.15 | length 36.7
  Top Layer w8: R7.2@885.58,1852.31 893.95,1843.94 U7.15@893.95,1819.04
NetR8_2: R8.2 U8.15 | length 36.7
  Top Layer w8: R8.2@1203.34,1852.6 1211.71,1844.23 U8.15@1211.71,1819.33
NetR10_2: R10.2 U9.1 | length 79.5
  Top Layer w8: R10.2@22.9,1384 66.54,1384 78.11,1395.57 94.94,1395.57 96.39,1394.12 U9.1@97.05,1394.12
NetR12_2: R12.2 U10.1 | length 51.2
  Top Layer w8: R12.2@380.84,1413.9 380.84,1413.55 385.11,1409.29 392.98,1409.29 407.06,1395.21 U10.1@424.11,1395.21
NetR14_2: R14.2 U11.1 | length 46.3
  Top Layer w8: R14.2@696.76,1384.22 697.44,1384.9 712.34,1384.9 724.58,1397.14 U11.1@737.69,1397.14
NetR16_2: R16.2 U12.1 | length 49.2
  Top Layer w8: R16.2@1016.66,1408.6 1020.48,1404.78 1036.97,1404.78 1045.86,1395.89 1057.33,1395.89 1058.21,1395.01 U12.1@1060.2,1395.01
NetR17_1: R17.1 U9.10 | length 324.7
  Top Layer w8: R17.1@105.31,1786.44 105.31,1766.2 98.83,1759.72 80.61,1759.72 67.72,1746.83 67.72,1728.61 146.51,1649.82 146.51,1587.97 125.09,1566.56 125.09,1556.2 117.78,1548.89 117.78,1533.82 U9.10@118.71,1532.9
NetR18_1: R18.1 U10.10 | length 327.5
  Top Layer w8: v2@393.7,1555.12 396.91,1555.12 406.75,1564.96 437.99,1564.96 445.76,1557.19 U10.10@445.76,1533.99 ; v2(445.05,1777.05) 446.17,1778.17 R18.1@446.71,1778.17
  SIG2 w8: v2(396.65,1554.31) 396.65,1701.15 445.05,1749.55 v2(445.05,1777.05)
NetR19_1: R19.1 U11.10 | length 397.3
  Top Layer w8: v2(705.49,1540.05) 724.24,1558.81 758.56,1558.81 763.24,1554.12 U11.10@763.24,1533.03 ; v2(797.24,1797.31) 797.94,1798.01 R19.1@798.97,1798.01
  SIG2 w8: v2(705.49,1540.05) 733.63,1568.19 733.63,1753.18 777.75,1797.31 v2(797.24,1797.31)
NetR20_1: R20.1 U12.10 | length 400.2
  Top Layer w8: U12.10@1081,1533.32 1081.46,1532.86 1081.46,1514.84 1097.38,1498.92 1111.66,1498.92 v2(1112.07,1498.5) ; v2(1114.27,1786.32) 1115.8,1787.83 1115.8,1796.77 R20.1@1117.32,1798.3
  SIG2 w8: v2(1112.07,1498.5) 1110.61,1498.5 1062.21,1546.91 1062.21,1734.34 1114.19,1786.32 v2(1114.27,1786.32)
NetR37_1: R37.1 U14.5 | length 1161.4
  Top Layer w8: U14.5@636.09,1230.33 647.9,1230.33 652.76,1225.48 662.05,1225.48 v1(688.15,1199.37)
  GND3/SIG4 w8: v2(385.67,1934.94) 385.67,1937.07 365.6,1957.14 319.03,1957.14 306.15,1944.26 306.15,1837.16 420.64,1722.67 420.64,1309.37 472,1258 551.43,1258 569.31,1240.12 569.31,1239.21 584.06,1224.46 663.06,1224.46 v1(688.15,1199.37)
  Bottom Layer w6: v2(385.67,1934.94) 390.04,1934.94 R37.1@390.7,1934.28
NetR38_1: R38.1 U15.5 | length 1675.4
  Top Layer w8: v2(523.12,602.02) 571.19,553.95 621.88,553.95 631.74,544.09 643.9,544.09 U15.5@649.25,538.73
  SIG3 w8: v2(121.3,1888.62) 118.05,1888.62 112.16,1882.73 112.07,1882.73 103.05,1873.72 103.05,1807 113.83,1796.23 113.83,1786.26 149.58,1750.5 149.58,1708.29 163.04,1694.82 163.04,1578.2 126.31,1541.46 126.31,1493.2 193.52,1425.99 193.52,1405.89 193.52,1386.28 242,1337.8 242,1272.03 314,1200.03 314,811.14 v2(523.12,602.02)
  Bottom Layer w8: v2@124.21,1886.28 124.21,1886.38 126.84,1889.01 144.97,1889.01 R38.1@145.36,1889.41
NetR39_1: R39.1 U16.5 | length 1514
  SIG3 w8: v2(403.05,1869.32) 405.34,1867.02 415.32,1867.02 426.28,1856.06 426.28,1821.36 410.05,1805.13 410.05,1585.58 417,1578.63 417,1530.45 409.37,1522.82 409.37,1400.9 436.87,1373.39 436.87,1323.84 518.02,1242.68 532.01,1242.68 789.4,985.3 881.67,985.3 909.77,957.2 944.61,957.2 v2(959.68,972.27)
  Bottom Layer w8: v2(403.05,1869.32) 454.55,1869.32 458.82,1873.59 R39.1@458.82,1874.17 ; v2(959.68,972.27) 1040.9,891.06 U16.5@1040.9,816.09
NetR40_1: R40.1 U17.5 | length 1919.1
  SIG3 w8: v2(342.84,1878.86) 344.04,1880.07 356.74,1880.07 389.62,1912.94 397.2,1912.94 404.93,1920.67 422.39,1920.67 442.28,1900.78 442.28,1814.73 426.28,1798.73 426.28,1785.15 426.05,1784.92 426.05,1769.18 426.28,1768.95 426.28,1591.98 433,1585.26 433,1523.82 425.37,1516.19 425.37,1407.52 452.87,1380.02 452.87,1330.46 524.65,1258.68 549.64,1258.68 798.05,1010.27 975.42,1010.27 1012.82,972.88 1012.82,844.58 1135.63,721.77 v2(1135.63,653.43)
  Bottom Layer w8: R40.1@332.23,1879.39 332.5,1879.13 342.57,1879.13 v2(342.84,1878.86) ; v2(1135.63,653.43) 1148.25,640.81 1154.31,640.81 1173.17,621.95 U17.5@1233,621.95
NetR60_1: R60.1 R61.2 U22.2 | length 224.1
  Top Layer w8: v2(1237.3,1999.03) 1237.3,1991.77 1267.65,1961.42 1298.64,1961.42 1303.46,1966.24 1306.29,1966.24 R61.2@1327.49,1987.44 1323.14,1991.78 1323.14,2013.03 R60.1@1318.09,2018.09
  Bottom Layer w8: v2(1237.3,1999.03) 1237.3,2007.35 1245.77,2015.83 1245.77,2015.95 1255.45,2025.63 U22.2@1290.06,2025.63
NetR62_2: R62.2 U22.1 | length 127.6
  Top Layer w8: R62.2@1206.33,2095.01 1206.33,2076.34 1212.69,2069.97 1212.69,2063.17 1247.69,2028.17 1247.79,2028.17 1260.68,2015.29 1260.68,2005.65 v2@1271.74,1994.58
  other v2: 1274.17,1994.04
NetR71_2: R71.2 U5.5 | length 141.9
  Top Layer w8: U5.5@212.99,1729.34 213.91,1730.27 235.58,1730.27 238.76,1733.45 v2(242,1733.45)
  Bottom Layer w8: R71.2@153.95,1682.78 153.95,1683.57 158.22,1687.83 159,1687.83 160.88,1689.71 166.36,1689.71 182.54,1705.89 217.37,1705.89 242,1730.52 v2(242,1733.45)
NetR72_2: R72.2 U6.5 | length 61.2
  Top Layer w8: U6.5@540.05,1730.43 540.97,1731.35 561.01,1731.35 563.39,1733.74 v2(566.64,1733.74)
  Bottom Layer w8: R72.2@559.32,1703.51 560.64,1704.83 560.64,1724.49 566.64,1730.49 v2(566.64,1733.74)
NetR73_2: R73.2 U7.5 | length 68.4
  Top Layer w8: U7.5@857.53,1729.47 882.28,1729.47 886.97,1734.16 v2(886.97,1736.78)
  Bottom Layer w8: v2(886.97,1736.78) 887.39,1736.37 887.39,1703.57 R73.2@888.12,1702.84
NetR74_2: R74.2 U8.5 | length 78.4
  Top Layer w8: U8.5@1175.29,1732.76 1204.88,1732.76 v2(1211.06,1738.94)
  Bottom Layer w8: R74.2@1201.08,1703.05 1202.55,1704.52 1202.55,1730.43 v2(1211.06,1738.94)
NetR75_2: R75.2 U9.5 | length 27.9
  Top Layer w8: v2(174.52,1413.76) 174.52,1410.51 176.84,1408.2 176.84,1388.15 U9.5@177.76,1387.23
NetR76_2: R76.2 U10.5 | length 29.6
  Top Layer w8: v2(501.58,1414.85) 501.58,1411.6 503.89,1409.29 503.89,1389.24 U10.5@504.82,1388.32
  Bottom Layer w8: R76.2@500.34,1416.09 v2(501.58,1414.85)
NetR77_2: R77.2 U11.5 | length 96.9
  Top Layer w8: v2(816.63,1416.84) 816.63,1413.59 821.38,1408.85 821.38,1388.28 U11.5@822.3,1387.36
  Bottom Layer w8: R77.2@767.29,1444.3 796.63,1444.3 814.34,1426.59 814.34,1419.13 v2(816.63,1416.84)
NetR78_2: R78.2 U12.5 | length 69
  Top Layer w8: v2(1135.63,1418.76) 1135.63,1415.51 1139.13,1412.01 1139.13,1381.85 U12.5@1140.06,1380.92
  Bottom Layer w8: v2@1135.63,1418.43 1138.94,1418.43 1145.86,1411.51 R78.2@1162.12,1411.51
NetR79_2: R79.2 U9.15 | length 45
  Top Layer w8: v2@49.49,1408.46 51.79,1410.75 66.44,1410.75 79.34,1423.65 U9.15@88.19,1423.65
  other v2: 50.86,1407.05
NetR80_2: R80.2 U10.15 | length 54.5
  Top Layer w8: U10.15@415.25,1424.74 v2(445.76,1424.74)
  Bottom Layer w8: v2(445.76,1424.74) 446.69,1424.74 459.78,1411.65 R80.2@459.78,1407.05
NetR81_2: R81.2 U11.15 | length 26.3
  Bottom Layer w8: v2(723.02,1419.14) 725.32,1416.84 725.32,1394.77 R81.2@726.02,1394.07
NetR82_2: R82.2 U12.15 | length 56
  Top Layer w8: U12.15@1050.49,1424.06 1051.41,1423.14 1076.59,1423.14 v2(1078.73,1421)
  Bottom Layer w8: R82.2@1078.03,1394.85 1078.73,1395.54 v2(1078.73,1421)
NetR91_2: R91.2 U19.4 | length 43.2
  Bottom Layer w8: R91.2@588.25,1879.26 588.94,1879.95 U19.4@588.94,1916.7 U19.4@592.82,1912.82
NetR96_1: R96.1 U9.14 | length 70.7
  Top Layer w8: U9.14@88.19,1443.33 U9.14@88.19,1443.33 117.74,1443.29 v2(117.79,1443.24)
  Bottom Layer w8: R96.1@76.77,1443.11 76.84,1443.17 117.72,1443.17 v2(117.79,1443.24)
NetR97_1: R97.1 U10.14 | length 87.6
  Top Layer w8: U10.14@415.25,1444.42 416.17,1445.34 431.45,1445.34 445.89,1459.78 445.89,1484.01 v2(447.67,1485.78)
  Bottom Layer w8: R97.1@425.41,1482.02 427.3,1483.9 445.78,1483.9 v2(447.67,1485.78)
NetR98_1: R98.1 U11.14 | length 184.5
  Top Layer w8: U11.14@732.73,1443.46 733.65,1442.54 745.45,1442.54 747.2,1440.8 773.08,1440.8 797.23,1464.94 797.23,1490.9 786.25,1501.88 772.52,1501.88 v2@771.34,1503.05
  Bottom Layer w8: R98.1@741.61,1475.22 741.61,1496.5 746.3,1501.19 v2(770.45,1501.19)
NetR99_1: R99.1 U12.14 | length 104.7
  Top Layer w8: U12.14@1042.42,1443.9 1042.57,1443.75 1078.5,1443.75 1086.87,1452.12 v2(1090.12,1452.12)
  Bottom Layer w8: R99.1@1060.07,1481.05 1060.07,1461.52 1068.12,1453.47 1088.77,1453.47 v2(1090.12,1452.12)
NetU13_3: U13.3 U13.10 | length 473
  Top Layer w8: U13.3@1035.94,1913.33 1035.94,1870.96 1064.04,1842.86 1081.95,1842.86 1103.34,1842.86 1185.38,1924.91 1185.38,1972.58 1180.69,1977.27 1180.69,1993.12 1126.43,2047.38 1085.48,2047.38 1075.31,2037.21 U13.10@1075.31,2003.88
NetU13_6: U13.6 U13.9 | length 250.2
  Top Layer w8: U13.6@1094.99,1913.33 1095.92,1912.41 1095.92,1908.95 1107.16,1908.95 1108.31,1907.8 1126.53,1907.8 1131.08,1912.35 1150.2,1912.35 1169.38,1931.53 1169.38,1965.95 1164.69,1970.64 1164.69,1986.49 1127.62,2023.57 1095,2023.57 U13.9@1094.99,2003.88
NetU22_5: U22.5 U22.6
ON/OFF: C114.1 J7.1 Q1.A1 R58.1 | length 567.4
  Top Layer w8: Q1.A1@719.12,2243.5 Q1.A1@718.58,2244.05 718.58,2226.51 722.36,2222.72 J7.1@722.36,2151.16 ; J7.1@724.16,2149.36 731.94,2149.36 794.02,2211.44 965.14,2211.44 981.06,2227.37 981.06,2257.84 985.75,2262.53 1052.3,2262.53 1079.42,2235.4 1088.39,2235.4 1093.27,2230.53 R58.1@1093.27,2205.43
P_GOOD: J8.7 R56.1 U18.48 | length 2875.9
  Top Layer w8: R56.1@145.9,2222.67 149.88,2226.65 149.88,2238.75 164.16,2253.02 164.16,2272.37 v2(167.01,2275.22)
  SIG3 w8: v2(167.01,2275.22) 57.98,2166.19 57.98,1856.22 22.08,1820.32 22.08,1733.72 53.28,1702.52 110.09,1702.52 131.04,1681.57 131.04,1591.45 91.31,1551.71 91.31,1420.86 157.72,1354.45 180.1,1354.45 210,1324.54 210,1258.77 280.45,1188.33 280.45,684.18 645.42,319.21 645.42,101.2 624.33,80.1 521.13,80.1 J8.7@487.94,46.91
  Bottom Layer w6: v2(167.01,2275.22) 165.16,2273.37 165.16,2243.15 170.51,2237.79 U18.48@170.51,2215.16
PGND: C7.1 C9.1 C10.1 C11.1 C12.1 C13.1 C14.1 C15.1 C16.1 C17.1 C18.1 C19.1 C20.1 C21.1 C22.1 C23.1 C24.1 C33.1 C34.1 C35.1 C36.1 C37.1 C38.1 C39.1 C40.1 C41.1 C42.1 C43.1 C44.1 C57.2 C58.2 C59.2 C60.2 C61.2 C62.2 C63.2 C64.2 C65.2 C111.2 C127.1 C128.1 C129.1 C130.1 C131.1 C132.1 C133.1 C134.1 C135.1 C136.1 C137.1 C138.1 C139.1 C140.1 C141.1 C142.1 J2.1 J4.1 J6.1 NT1.2 R68.1 U9.6 U10.6 U11.6 U12.6 | length 111.7
  Bottom Layer w8: NT1.2@471.71,2231.97 513.59,2231.97 C10.1@515.86,2234.23 ; v1(614.38,111.31) 645.08,111.31 C111.2@646.11,110.28 ; v1(614.38,139.93) 619.25,139.93 625.88,146.55 R68.1@646.11,146.55
  other v1: 118.4,44 241.55,75.25 116.53,78.61 146.61,78.61 176.69,78.61 206.77,78.61 271.32,78.88 301.4,78.88 334.87,84.1 229.05,100.17 381.89,99.56 201.25,105.24 86.05,108.51 116.13,108.51 146.21,108.51 523.2,109.86 553.28,109.86 173.41,111.3 584.3,111.31 496.04,112.27 334.03,127.1 201.49,134.15 523.2,138.47 553.28,138.47 360.28,139.62 584.3,139.93 86.05,142.76 116.13,142.76 146.21,142.76 176.29,142.76 496.04,142.89 551.8,162.26 579.82,172.16 608.2,172.16 363.53,172.83 521.9,173.89 494.71,174.74 86.05,177.01 116.13,177.01 146.21,177.01 176.29,177.01 206.37,177.01 327.3,182.66 234.85,200.26 298.17,205.88 86.05,207.33 114.72,207.33 144.8,207.33 176.29,207.33 206.37,207.33 263.26,207.9 242.91,232.81 273.77,232.59 305.12,232.75 176.96,234.38 211.4,233.89 86.02,235.03 145.77,235.2 117.74,236.85 213.23,261.24 243.31,261.24 273.39,261.24 303.47,261.24 86.06,262.01 146.22,262.01 176.3,262.01 116.13,264.52 212.83,291.14 242.91,291.14 272.99,291.14 303.07,291.14 85.66,291.91 115.74,291.91 145.82,291.91 175.9,291.91 212.83,325.39 242.91,325.39 272.99,325.39 303.07,325.39 85.66,326.16 115.74,326.16 145.82,326.16 175.9,326.16 85.66,360.41 115.74,360.41 145.82,360.41 175.9,360.41 212.83,359.64 242.91,359.64 272.99,359.64 303.07,359.64 212.83,389.96 241.5,389.96 271.58,389.96 303.07,389.96 85.66,390.73 114.33,390.73 144.41,390.73 175.9,390.73 117.35,420.26 147.43,420.26 177,420.26 148.26,447.97 589.06,595.37 588.61,625.45 587.66,660.79 587.58,688.91 586.63,721.91 586.18,751.99 594.42,1249.46 674.05,1250.39 1267.96,1264.94 1294.32,1270.74 274.01,1273.45 304.74,1273.45 335.46,1273.45 1346.54,1275.63 1373.84,1275.59 598.97,1277.09 632.33,1277.08 665.69,1277.03 1319.44,1280.25 1398.88,1285.57 1268.11,1293.21 1296.86,1297.74 274.01,1300.09 304.74,1300.09 335.46,1300.09 598.79,1303.85 632.15,1303.84 665.5,1303.74 914.18,1317.12 947.54,1317.12 980.9,1317.12 1266.71,1321.49 1294.32,1326 272.53,1326.73 304,1326.73 335.46,1326.73 665.5,1330.44 598.79,1330.61 632.15,1330.6 914.18,1345.24 947.54,1345.24 980.9,1344.87 1261.76,1348.81 272.53,1353.37 303.19,1353.37 333.85,1353.37 598.79,1357.37 632.15,1357.35 665.5,1357.14 1286.82,1361.35 915.36,1373.35 948.72,1373.35 982.08,1372.62 1262.86,1377.42 272.53,1380.01 304,1380.01 335.46,1380.01 599.97,1384.13 633.32,1384.11 666.68,1383.85 1304.09,1397.5 982.08,1400.37 1277.34,1399.67 915.36,1401.46 948.72,1401.46 272.53,1406.65 304,1406.65 335.46,1406.65 599.97,1410.89 633.32,1410.86 666.68,1410.55 1299.76,1423.79 1272.09,1425.95 1327.07,1427.06 1357.43,1427.06 1387.79,1427.06 979.4,1428.12 915.36,1429.58 947.38,1429.58 272.53,1433.29 304,1433.29 335.46,1433.29 662.09,1437.25 600.61,1437.65 631.35,1437.62 1422.72,1547.89 1087.21,1585.74 1421.27,1587.97 766.5,1593.58 451.03,1602.03 1087.21,1631.12 766.5,1639.28 451.03,1647.96 1420.12,1665.51 1087.21,1669.86 769.4,1672.49 451.03,1692.86 1421.27,1707.28 1088.77,1715.31 758.63,1742.83 560.96,2168.96 591.51,2168.96 621.98,2168.96 834.69,2169.25 864.22,2169.25 894.77,2169.25
"PMBUS CONTROL": C106.1 Q1.B1 Q1.B2 R55.1 U18.27 | length 1332.5
  Top Layer w8: Q1.B2@698.89,2263.73 Q1.B1@718.58,2263.73 718.89,2263.41 740.59,2263.41 757.87,2246.13 v2(757.87,2208.11)
  SIG2 w8: v2(85.74,1918.78) 106.5,1939.54 154.56,1939.54 183.28,1910.82 183.28,1894.35 223.25,1854.38 311.72,1854.38 337.17,1828.93 365.1,1828.93 373.8,1837.63 v2(398.15,1837.63)
  GND3/SIG4 w8: v2(398.15,1837.63) 436.67,1799.1 559.38,1799.1 603.96,1843.68 690.56,1843.68 791.38,1944.5 791.38,2174.61 v2(757.87,2208.11)
  Bottom Layer w6: v2@82.48,1914.28 97.79,1929.59 98.28,1929.59 106.58,1937.89 106.58,1952.42 U18.27@107.52,1953.35
  Bottom Layer w8: C106.1@740.62,2235 741.4,2235 750.78,2225.63 750.78,2218.45 v2@757.87,2211.36 ; v2(757.87,2208.11) 757.87,2208.17 v2@758.66,2208.96 ; v2@757.87,2208.96 v2@758.66,2208.96 ; R55.1@771.04,2222.13 771.04,2221.34 v2@758.66,2208.96
RS+: C107.1 R45.2 R65.1 R66.2 | length 2501.2
  SIG2 w8: v2(590.82,1994.45) 594.07,1994.45 600.07,2000.45 623.71,2000.45 667.23,1956.94 824.29,1956.94 855.12,1926.1 855.12,1808.32 847.28,1800.48 847.28,1737.44 789.9,1680.06 789.9,1582.44 728.78,1521.32 728.78,1450.59 744.5,1434.88 744.5,1374.49 844,1274.99 844,1166.19 651.14,973.33 651.14,649.44 681.43,619.16 681.43,288.57 681.53,288.47 681.53,200.67 732.1,150.11 732.1,139.79 734.49,137.39 v2(733.28,136.18)
  Bottom Layer w8: R65.1@569.06,2022.79 569.85,2022.79 580.75,2011.89 580.75,2005.14 590.82,1995.07 v2(590.82,1994.45) ; C107.1@680.23,234.96 680.69,234.5 R66.2@680.69,198.62 ; R66.2@681.15,199.03 681.94,199.03 686.21,194.77 686.21,191.95 688.08,190.08 688.08,186.62 704.47,170.24 716.9,170.24 733.28,153.86 v2(733.28,136.18) 733.28,106.42 R45.2@735.01,104.69
RS-: C111.1 R51.2 R67.1 R68.2 R69.1 | length 2595.1
  SIG2 w8: v2@516.34,1995.16 537.64,2016.45 630.34,2016.45 673.86,1972.94 830.91,1972.94 871.12,1932.73 871.12,1798.6 863.28,1790.76 863.28,1730.82 805.9,1673.44 805.9,1575.81 744.78,1514.69 744.78,1457.22 760.5,1441.5 760.5,1381.12 860,1281.62 860,1159.56 667.14,966.7 667.14,658.64 697.53,628.25 697.53,207.3 755.53,149.3 755.53,115.52 736.24,96.23 v2(696.27,96.23)
  Bottom Layer w8: R69.1@488.84,1996.11 489.55,1996.83 R67.1@516.34,1996.83 516.34,1995.86 v2(515.64,1995.16) ; R68.2@672.1,146.36 C111.1@672.1,110.28 676.36,106.02 685.59,106.02 695.37,96.23 v2(696.27,96.23)
SCI_RX: RX.1 U18.56 | length 1282.9
  Top Layer w8: RX.1@1367.8,2242.26 1367.8,2205.29 1381.52,2191.57 v2(1381.52,2172.53) ; RX.1@1367.8,2244.76 RX.1@1369.05,2243.51
  GND3/SIG1 w8: v2(349.8,2273.07) 367.72,2273.07 385.23,2255.56 461.84,2255.56 474.41,2268.12 630.36,2268.12 634.51,2272.27 729.95,2272.27 758.33,2243.9 801.01,2243.9 827.05,2269.94 1305.42,2269.94 1381.52,2193.83 v2(1381.52,2172.53)
  Bottom Layer w6: U18.56@296.49,2215.16 296.49,2225.99 297.43,2226.93 317.19,2246.68 324.76,2246.68 349.8,2271.73 v2(349.8,2273.07)
SCI_TX: TX.1 U18.2 | length 1836.4
  Top Layer w8: v2(1399.62,1959.75) 1402.87,1959.75 1413.97,1970.85 1424.48,1970.85 1430.14,1976.5 1430.14,2139.5 1403.55,2166.09 1403.55,2194.07 1414.55,2205.07 1414.55,2241.5 TX.1@1417.8,2244.76
  SIG3 w8: v2(359.5,2168.9) 357.88,2167.29 342.77,2167.29 331.8,2178.26 331.8,2213.75 369.19,2251.14 467.86,2251.14 518.92,2200.08 649.67,2200.08 677.49,2227.9 746.55,2227.9 762.32,2243.67 784.97,2243.67 809.42,2268.12 1322.66,2268.12 1403.52,2187.26 1403.52,2153 1378.3,2127.78 1378.3,1984.55 1393.8,1969.04 1393.8,1968.82 1399.62,1963 v2(1399.62,1959.75)
  Bottom Layer w6: U18.2@325.04,2170.87 v2@353.6,2170.87
SW1: L1.2 U5.6 U9.7
  other v1: 22.08,1159.47 49.88,1159.47 79.96,1159.47 110.04,1159.47 140.12,1159.47 170.2,1159.47 200.16,1159.47 22.08,1188.07 50.15,1188.07 80.23,1188.07 110.31,1188.07 140.39,1188.07 170.47,1188.07 200.16,1188.07 22.08,1216.4 50.69,1216.4 80.77,1216.4 110.85,1216.4 140.93,1216.4 171.01,1216.4 22.08,1243.11 51.23,1243.11 81.31,1243.11 111.39,1243.11 141.47,1243.11 169.48,1243.11 22.08,1267.19 50.15,1267.19 80.23,1267.19 110.31,1267.19 140.39,1267.19 196.06,1487.05 223.62,1487.05 251.18,1487.05 278.74,1487.05 306.3,1487.05 333.87,1486.85 196.21,1513.23 223.77,1513.23 251.33,1513.23 278.89,1513.23 306.45,1513.23 334.91,1514.93 196.65,1539.41 225.53,1539.41 254.41,1539.41 283.29,1539.41 197.61,1569.28 232.1,1568.8 266.59,1568.8 197.95,1596.67 232.45,1596.55 266.94,1596.55 197.79,1624.05 232.29,1624.3 266.78,1624.3 197.63,1651.44 232.12,1652.04 266.62,1652.04 198.1,1678.83 232.28,1679.79 266.46,1679.79
SW2: L1.1 U6.6 U10.7
  other v1: 23.59,520.11 53.67,520.11 83.75,520.11 113.83,520.11 143.91,520.11 173.99,520.11 204.07,520.11 23.59,554.36 53.67,554.36 83.75,554.36 113.83,554.36 143.91,554.36 173.99,554.36 204.07,554.36 23.59,588.62 53.67,588.62 83.75,588.62 113.83,588.62 143.91,588.62 173.99,588.62 204.07,588.62 23.59,622.87 53.67,622.87 83.75,622.87 113.83,622.87 143.91,622.87 173.99,622.87 204.07,622.87 23.59,657.12 53.67,657.12 83.75,657.12 113.83,657.12 143.91,657.12 173.99,657.12 204.07,657.12 524.75,1485.41 552.31,1485.41 579.87,1485.41 607.43,1487.65 634.99,1487.65 662.55,1487.65 662.7,1511.04 524.89,1511.58 552.46,1511.58 580.02,1511.58 607.58,1511.58 635.14,1511.58 525.33,1537.77 554.22,1537.77 583.1,1537.77 611.98,1537.77 525.77,1563.96 554.66,1563.96 590.45,1566.02 526.21,1590.14 555.1,1590.14 590.79,1593.63 526.65,1616.33 555.54,1616.33 590.63,1621.25 527.09,1642.52 555.98,1642.52 590.47,1648.86 527.53,1668.7 556.42,1668.7 590.82,1676.47
SW3: L2.2 U7.6 U11.7
  other v1: 898.57,1145.08 928.65,1145.08 958.73,1145.08 988.81,1145.08 1018.89,1145.08 1048.97,1145.08 1079.05,1145.08 898.57,1179.33 928.65,1179.33 958.73,1179.33 988.81,1179.33 1018.89,1179.33 1048.97,1179.33 1079.05,1179.33 898.57,1213.58 928.65,1213.58 958.73,1213.58 988.81,1213.58 1018.89,1213.58 1048.97,1213.58 1079.05,1213.58 898.57,1247.83 928.65,1247.83 958.73,1247.83 988.81,1247.83 1018.89,1247.83 1048.97,1247.83 1079.05,1247.83 1076.89,1278.18 898.57,1282.08 928.65,1282.08 958.73,1282.08 988.81,1282.08 1018.89,1282.08 1048.97,1282.08 978.63,1484.18 840.82,1484.73 868.38,1484.73 895.94,1484.73 923.5,1484.73 951.06,1484.73 978.77,1510.36 840.97,1510.91 868.53,1510.91 896.09,1510.91 923.65,1510.91 951.21,1510.91 841.41,1537.09 870.29,1537.09 899.17,1537.09 928.05,1537.09 876.25,1564.95 907.47,1565.36 845.04,1565.84 876.43,1591.95 907.47,1592.36 845.39,1592.84 876.35,1618.95 907.47,1619.36 845.23,1619.84 876.28,1645.95 907.49,1646.36 845.07,1646.84 876.12,1672.94 907.33,1673.35 844.9,1673.84
SW4: L2.1 U8.6 U12.7
  other v1: 903.55,528.67 932.63,528.67 962.71,528.67 992.79,528.67 1022.87,528.67 1052.95,528.67 1083.03,528.67 903.55,562.92 932.63,562.92 962.71,562.92 992.79,562.92 1022.87,562.92 1052.95,562.92 1083.03,562.92 903.55,597.17 932.63,597.17 962.71,597.17 992.79,597.17 1022.87,597.17 1052.95,597.17 1083.03,597.17 903.55,631.42 932.63,631.42 962.71,631.42 992.79,631.42 1022.87,631.42 1052.95,631.42 1083.03,631.42 903.55,665.67 932.63,665.67 962.71,665.67 992.79,665.67 1022.87,665.67 1052.95,665.67 1166.55,1478.21 1194.51,1478.21 1222.47,1478.21 1250.44,1478.21 1278.4,1478.21 1306.36,1477.67 1166.7,1504.39 1194.66,1504.39 1222.62,1504.39 1250.58,1504.39 1278.55,1504.39 1306.51,1503.85 1167.14,1530.58 1196.69,1530.58 1226.24,1530.58 1255.79,1530.58 1201.1,1558.46 1168.89,1559.35 1233.31,1558.87 1201.45,1586.7 1233.66,1587.11 1169.24,1587.6 1201.29,1614.95 1233.5,1615.36 1169.07,1615.84 1201.12,1643.2 1168.91,1644.09 1233.34,1643.61 1200.96,1671.45 1168.75,1672.34 1233.17,1671.86
TEMP_P: C103.1 R47.1 RT1.2 U18.21 | length 209.3
  Bottom Layer w6: R47.1@90.25,1827.18 R47.1@95.68,1832.61 ; R47.1@95.68,1832.65 124.3,1861.27 124.3,1863.05 126.52,1865.28 136.37,1865.28 141.37,1870.28 C103.1@194.3,1870.28 ; C103.1@195.26,1871.25 192.99,1873.52 192.99,1921.38 201.63,1930.01 U18.21@201.63,1952.98
VDD_1V25: C143.1 C144.1 C145.1 C146.1 U18.5 U18.41 U18.53 | length 754
  Top Layer w8: v2(28.36,2177.74) C146.1@53.55,2177.74
  Top Layer w10: C143.1@210.24,2228.17 214.74,2228.17 217.24,2230.67 217.24,2236.47 223.1,2242.33 240.15,2242.33 244.31,2246.49 244.31,2250.17 v2@261.16,2267.02
  GND1 w15: v2(28.36,2177.74) 70.25,2177.74 114.29,2221.78 243.73,2221.78 261.06,2239.12 v2(261.06,2276.97)
  PWR4 w15: v2(261.06,2276.97) 261.06,2235.6 324.57,2172.1 324.57,2132.36 343.7,2113.23 358.35,2113.23 358.46,2113.11 362,2113.11 v2(362.95,2112.16)
  Bottom Layer w6: v2(28.36,2177.74) 32.15,2177.74 38.85,2171.04 U18.41@64.74,2171.04 ; U18.53@249.25,2223.16 249.25,2261.91 261.06,2273.72 v2(261.06,2276.97) ; U18.5@322.55,2122.69 340.5,2122.69 348.36,2114.84 360.27,2114.84 v2(362.95,2112.16)
VDDA_3V3: C148.1 C149.1 L3.2 U18.20 | length 136.3
  Top Layer w10: L3.2@177.5,1949.81 C149.1@222.31,1949.81 222.49,1950 248.05,1950 C148.1@248.23,1949.81 ; v2(222.49,1922.31) 220.66,1924.14 220.66,1941.08 C149.1@224.11,1944.54
  Bottom Layer w6: U18.20@217.75,1961.35 U18.20@217.75,1953.35 217.75,1933.71 217.94,1933.53 217.94,1932.82 219.28,1931.47 219.28,1925.51 v2(222.49,1922.31)
VDDIO_3V3: C151.1 C152.1 C153.1 L4.2 U18.40 U18.54 | length 319.4
  Top Layer w10: v2(27.62,2146.63) 28.75,2147.76 C152.1@55.01,2147.76 ; C153.1@268.71,2217.3 268.71,2251.5 v2(290.68,2273.47) ; C153.1@268.93,2217.08 297.03,2217.08 297.03,2217.86 300.8,2221.64 301.59,2221.64 312.55,2232.59 374.83,2232.59 L4.2@384.67,2242.44
  Bottom Layer w6: v2(27.62,2146.63) 29.64,2146.63 38.13,2155.13 U18.40@63.22,2155.13 ; U18.54@265,2223.67 265,2247.79 v2(290.68,2273.47)
VIN: C7.2 C9.2 C10.2 C11.2 C12.2 C13.2 C14.2 C15.2 C16.2 C17.2 C18.2 C19.2 C20.2 C21.2 C22.2 C23.2 C24.2 C33.2 C34.2 C35.2 C36.2 C37.2 C38.2 C39.2 C40.2 C41.2 C42.2 C43.2 C44.2 C118.2 C119.2 C127.2 C128.2 C129.2 C130.2 C131.2 C132.2 C133.2 C134.2 C135.2 C136.2 C137.2 C138.2 C139.2 C140.2 C141.2 C142.2 J1.1 R46.2 R60.2 U5.7 U5.8 U6.7 U6.8 U7.7 U7.8 U8.7 U8.8 U22.3 | length 499.2
  Top Layer w8: U5.8@358.66,1749.03 358.93,1748.76 375.72,1748.76 C138.2@394.46,1730.02 ; U6.8@685.72,1750.12 686.64,1749.2 697.88,1749.2 709.17,1737.91 709.17,1733.93 C142.2@718.95,1724.15 ; U7.8@1003.2,1749.16 1025.93,1749.16 1032.98,1742.11 1032.98,1726.4 C134.2@1038.36,1721.02 ; v2(1267.11,2048.96) 1267.25,2048.81 1267.25,2043.18 R60.2@1292.11,2018.32 ; U8.8@1320.96,1752.44 1343.76,1752.44 1349.16,1747.05 1349.16,1725.69
  Top Layer w15: v2(546.55,1954.3) 599.94,1954.3 610.36,1943.88 631.49,1943.88 646.43,1958.81 646.43,1991.59 582.21,2055.81 577.11,2055.81 567.42,2065.5 567.42,2068.66 v1(565.31,2070.77)
  Bottom Layer w8: v1@684.98,2056.24 v1(684.98,2057.69)
  other v1: 1348.43,1587.97 1276.94,1591.64 1312.8,1591.64 311.58,1595.39 341.04,1594.7 370.57,1594.7 987.28,1600.99 1016.8,1600.99 670.13,1601.92 699.66,1601.92 957.82,1601.68 640.67,1602.61 1277.29,1642.98 1313.67,1642.64 311.58,1646.49 341.04,1645.8 370.57,1645.8 1348.43,1647.25 987.28,1652.08 670.13,1653.02 699.66,1653.02 957.82,1652.78 640.67,1653.71 1016.35,1653.81 1274.68,1682.53 1312.8,1682.67 957.76,1691.48 987.28,1691.48 1016.8,1691.48 310.58,1697.28 341.04,1696.9 370.57,1696.9 669.29,1704.41 639.67,1704.5 698.05,1705.75 1348.43,1707.28 861.1,2055.81 891.65,2055.81 922.11,2055.81 951.64,2055.81 656.56,2068.76 599.09,2071.43 628.72,2070.59 1063.66,2094.13 984.25,2096.46 1092.52,2096.46 1033.33,2101.49 1084.55,2121.59 1072.9,2149.36 1048.74,2192.17 993.51,2197.39 1020.07,2199.87 1062.99,2214.57 1006.34,2224.89 1035.94,2228.48 865.52,2238.78 896.07,2238.78 926.53,2238.78 956.06,2238.78 559.04,2244.76 589.95,2245.58 620.08,2246.85 643,2251.77
  other v2: 1306.48,2048.95
VINOVP: C93.1 R46.1 R49.2 U18.10 | length 276.1
  Bottom Layer w6: U18.10@335.8,2044.83 399.99,2044.83
  Bottom Layer w8: 399.99,2044.83 435.46,2009.37 442.27,2009.37 474.58,1977.06 481.39,1977.06 486.28,1972.16 486.28,1968.23 494.1,1960.42 R46.1@498.03,1960.42 498.03,1934.14 509.55,1922.63 510.33,1922.63 514.6,1918.36 C93.1@514.6,1917.57 R49.2@541,1917.57
VOSNS_N: C108.2 R69.2 U18.8 | length 186.8
  Bottom Layer w6: U18.8@325.04,2076.39 U18.8@325.1,2076.32
  Bottom Layer w8: U18.8@325.1,2076.32 347.03,2076.32 354.82,2068.53 408.22,2068.53 442.1,2034.66 449.08,2034.66 C108.2@452.02,2031.72 452.02,2030.93 456.29,2026.66 457.08,2026.66 461.64,2022.1 R69.2@488.84,2022.1
VOSNS_P: C108.1 R65.2 R67.2 U18.7 | length 249.1
  Bottom Layer w8: U18.7@325.04,2092.13 351.86,2092.13 354.44,2089.56 420.16,2089.56 446.97,2062.76 447.75,2062.76 452.02,2058.49 C108.1@452.02,2057.7 453.83,2055.9 481.77,2055.9 496.51,2041.15 501.25,2041.15 512.07,2030.33 512.07,2027.08 R67.2@516.34,2022.81 R65.2@543.08,2022.79
VOUT: C57.1 C58.1 C59.1 C60.1 C61.1 C62.1 C63.1 C64.1 C65.1 C107.2 J3.1 J5.1 R27.4 R28.4 R31.4 R32.4 R66.1 | length 194.1
  Top Layer w8: v1(803.18,226.66) 803.18,204.59 806.92,200.85 v1(803.48,197.4) ; v1(831.41,158.33) 831.48,158.33 861.01,187.86 861.01,188.04 890.51,217.54 892.52,217.54 916.65,241.67 v1(918.91,241.67) v1(947.05,269.8)
  other v1: 1050.53,31.45 1080.21,31.45 1108.92,31.68 1138.45,31.68 1330,31.68 1173.92,34.72 1203.6,34.72 1232.31,34.95 1261.84,34.95 1298,34.95 1330.35,60.65 1109.03,61.93 1138.56,61.93 1174.26,62.46 1203.94,62.46 1232.65,62.69 1262.18,62.69 1299,62.69 1011.45,85.6 1156.76,85.53 1295.39,90.26 1330.24,89.92 1054.9,91.7 1262.72,91.75 1215.92,96.96 1129.38,99.35 976,103.76 1330.24,119.44 1360.01,119.44 1393.16,118.77 1295.39,119.78 1262.72,121.28 1082.69,122.96 855.97,128.83 1233.85,128.89 825.75,129.52 1111.98,130.63 1392.93,147.48 1295.16,148.5 1330,148.16 1359.78,148.16 958.56,148.95 1262.49,150 889.23,156.71 861.08,158.33 1117.49,177.44 1392.93,177.16 1295.16,178.17 1330,177.83 1359.78,177.83 1262.49,179.67 1226.31,183.85 1077.13,187.16 831.41,187.86 861.08,187.86 889.31,187.93 985.83,201.54 1147.13,205.99 1188.67,210.11 918.45,212.02 1029.43,214.21 831.97,217.72 861.64,217.72 890.44,217.72 831.34,248.1 861.02,248.1 889.81,248.1 805.18,259.71 919.95,270.72 830.02,276.86 859.55,276.86 888.26,277.09 804.36,289.57 1002.36,297.68 1040.8,297.92 1070.48,297.92 1099.19,298.15 919.95,300.25 961.92,302.61 832.67,306.01 862.34,306.01 891.14,306.01 803.03,318.49 919.95,330.11 961.92,332.29 832.6,333.07 862.12,333.07 891.65,333.07 802.03,345.34 919.95,360.48 961.69,361 832.6,362.74 862.12,362.74 891.65,362.74 1001.54,366.98 1088.87,367.27 1031.81,367.55 1060.34,367.55 804.9,374.14 919.95,389.06 961.69,390.53 832.6,392.41 862.12,392.41 891.65,392.41 803.8,403.72 919.95,418.39 1101.12,419.32 952.92,419.64 981.27,419.58 1011.64,420.2 1041.5,419.64 1071.03,419.64 832.6,422.09 862.12,422.09 891.65,422.09 803.8,432.75 1389.58,437.38 832.6,448.96 862.12,448.96 891.65,448.96 921.31,448.96 950.98,448.96 980.65,448.96 1010.33,448.96 1040,448.96 1069.67,448.96 1424.68,457.67 804.35,459.59 1391.16,464.95 1363.59,466.27 1335.52,473.29 1040.07,477.22 832.6,478.27 862.37,478.27 892.05,478.27 921.72,478.27 951.39,478.27 981.07,478.27 1010.74,478.27 1424.51,484.73 804.63,486.97 1394.15,491.39 1363.18,493.88 1333.31,503.24 1427.17,511.81 1400.98,518.13 1373.59,519.6 1330.35,536.54 1421.15,539.18 1358.26,541.79 1394.67,544.34 1311.17,565.72 1338.55,567.16 1365.86,568.38 1393.11,567.99 1420.76,569.55 1308.38,594.16 1335.73,594.16 1363.01,595.89 1391.47,596.82 1419.37,597.38 806.15,619.33 834.58,618.76 1305.44,621.92 1336.9,622.3 1364.32,623.22 1392.22,623.79 1421.43,624.35 1277.24,625.09 808.04,647.93 837.04,648.22 1286.63,649.45 1313.87,648.7 1341.31,649.64 1368.44,651.13 1257.97,651.69 1395.21,651.69 1422.37,651.69 1203.14,657.9 1231.82,658.25 1278.6,675.37 1308.75,675.44 809.47,677.28 839.33,678.91 1336.79,679.03 1395.03,679.4 1422.74,679.4 1365.25,680.34 808.66,708.49 838.78,708.76 706.43,721.08 872.49,729.79 837.97,736.71 807.57,737.53 767.62,744.72 707.34,753.78 870.37,761.59 839.87,764.67 808.71,765.88 765.83,775.66 707.34,781.22 899.17,787 867.97,791.39 809.5,794.32 839.54,793.78 766.19,806.93 707.71,812.49 898.78,818.33 867.9,819.58 809.49,822.36 838.81,821.82 766.19,834.37 901.57,847.37 867.9,848.07 809.76,849.5 839.08,850.33 765.74,864.44 902.71,875.38 838.27,877.49 867.9,876.56 809.13,878.16 765.74,891.88 808.5,905.35 838.81,904.66 867.9,905.05 900.71,905.11 766.19,928.59 867.46,932.23
VOUT1: L1.3 R27.3
  other v1: 373.6,832.59 403.68,832.59 433.76,832.59 463.84,832.59 493.92,832.59 524,832.59 554.08,832.59 583.19,839.5 373.6,866.84 403.68,866.84 433.76,866.84 463.84,866.84 493.92,866.84 524,866.84 554.08,866.84 584.15,866.84 373.6,901.09 403.68,901.09 433.76,901.09 463.84,901.09 493.92,901.09 524,901.09 554.08,901.09 584.15,901.09 373.6,935.34 403.68,935.34 433.76,935.34 463.84,935.34 493.92,935.34 524,935.34 554.08,935.34 584.15,935.34 373.6,969.59 403.68,969.59 433.76,969.59 463.84,969.59 493.92,969.59 524,969.59 554.08,969.59 584.15,969.59
VOUT1_S: R27.1 R33.1 | length 62
  Top Layer w8: R33.1@630.01,1055.12 630.01,998.63 R27.1@633.9,994.74
VOUT2: L1.4 R31.3
  other v1: 498.69,211.66 528.77,211.66 558.85,211.66 585,217.05 373.32,217.75 470.58,218.7 378.37,245.92 408.45,245.92 438.53,245.92 468.61,245.92 498.69,245.92 528.77,245.92 558.85,245.92 583.52,262.13 378.37,280.17 408.45,280.17 438.53,280.17 468.61,280.17 498.69,280.17 528.77,280.17 558.85,280.17 586.17,290.99 378.37,314.42 408.45,314.42 438.53,314.42 468.61,314.42 498.69,314.42 528.77,314.42 558.85,314.42 378.37,348.67 408.45,348.67 438.53,348.67 468.61,348.67 498.69,348.67 528.77,348.67 558.85,348.67
VOUT2_S: R31.1 R34.1 | length 70.5
  Top Layer w8: R34.1@640.26,366.53 640.26,362.59 663.12,339.73 R31.1@663.12,305.54
VOUT3: L2.3 R28.3
  other v1: 1423.32,873.95 1246.56,875.68 1276.64,875.68 1306.72,875.68 1336.79,875.68 1366.87,875.68 1396.95,875.68 1215.63,880.06 1246.56,909.94 1276.64,909.94 1306.72,909.94 1336.79,909.94 1366.87,909.94 1396.95,909.94 1427.03,909.94 1185.83,911.55 1216.24,912.53 1246.56,944.19 1276.64,944.19 1306.72,944.19 1336.79,944.19 1366.87,944.19 1396.95,944.19 1427.03,944.19 1184.21,945.5 1215.77,946.56 1182.6,977.84 1216.24,978.23 1246.56,978.44 1276.64,978.44 1306.72,978.44 1336.79,978.44 1366.87,978.44 1396.95,978.44 1427.03,978.44
VOUT3_S: R28.1 R35.1 | length 68
  Bottom Layer w8: R35.1@1216.84,824.71 1241.35,824.71 1257,809.07 R28.1@1278.32,809.07
VOUT4: L2.4 R32.3
  other v1: 1278.94,223.85 1309.02,223.85 1339.1,223.85 1369.18,223.85 1399.26,223.85 1426.19,225.5 1278.94,258.1 1309.02,258.1 1339.1,258.1 1369.18,258.1 1399.26,258.1 1426.19,259.75 1278.94,292.35 1309.02,292.35 1339.1,292.35 1369.18,292.35 1399.26,292.35 1426.19,294 1278.94,326.6 1309.02,326.6 1339.1,326.6 1369.18,326.6 1399.26,326.6 1426.19,328.25 1278.94,360.85 1309.02,360.85 1339.1,360.85 1369.18,360.85 1399.26,360.85 1426.19,362.51 1282.34,389.32 1311.27,392.63 1338.35,393.17 1368.43,393.17 1398.51,393.17 1425.44,394.82
VOUT4_S: R32.1 R36.1 | length 70.9
  Bottom Layer w8: R32.1@1231.38,384.4 1231.38,417.7 1255.2,441.53 R36.1@1255.2,445.46
VOUTA_S: R27.2 R41.1 | length 72.4
  Top Layer w8: R27.2@716.78,994.74 716.78,1022.81 745.37,1051.4 R41.1@745.37,1055.33
VOUTB_S: R31.2 R42.1 | length 64.3
  Top Layer w8: R31.2@745.99,305.54 745.99,348.45 758.35,360.82 R42.1@758.35,364.75
VOUTC_S: R28.2 R43.1 | length 67.2
  Bottom Layer w8: R43.1@1217.98,709.68 1221.92,709.68 1238.43,726.19 R28.2@1278.32,726.19
VOUTD_S: R32.2 R44.1 | length 64.2
  Bottom Layer w8: R44.1@1140.83,445.46 1140.83,392.08 R32.2@1148.51,384.4
XRSn: C154.1 R86.1 U18.4 | length 91.2
  Top Layer w8: C154.1@323.88,2145.54 344.2,2145.54 344.58,2145.16 345.91,2145.16 351.18,2139.89 v2(354.43,2139.89) ; C154.1@323.88,2145.64 323.88,2172.47 R86.1@325.04,2173.63
  Bottom Layer w6: U18.4@325.04,2139.38 325.36,2139.05 353.59,2139.05 v2(354.43,2139.89)
pads on no net: FID1.1 FID2.1 FID3.1 FID4.1 FID5.1 FID6.1 MP1. MP2. U5.1 U5.9 U5.10 U5.11 U5.12 U5.14 U6.1 U6.9 U6.10 U6.11 U6.12 U6.14 U7.1 U7.9 U7.10 U7.11 U7.12 U7.14 U8.1 U8.9 U8.10 U8.11 U8.12 U8.14 U9.11 U9.12 U10.11 U10.12 U11.11 U11.12 U12.11 U12.12 U13.15 U18.3 U18.6 U18.9 U18.23 U18.24 U18.25 U18.28 U18.29 U18.32 U18.37 U18.38 U18.39 U18.49 U18.50 U22.7

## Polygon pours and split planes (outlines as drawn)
GND on Bottom Layer "BOTTOM_LAYER_GND_P044" (solid, remove dead copper, pour order 44): 9.84,1958.66 9.84,2293.31 462.6,2293.31 462.6,2224.41 442.91,2204.72 383.86,2204.72 383.86,1978.35 364.17,1958.66
PGND on Bottom Layer "BOTTOM_LAYER_PGND_P174" (solid, remove dead copper, pour order 174): 543.39,2204.72 563.07,2185.04 669.29,2185.04 669.29,2155.51 550.15,2155.51 543.39,2148.57 543.39,2068.98 521.65,2047.24 403.54,2047.24 364.17,2086.61 364.17,2214.57 438.58,2288.98 543.39,2288.98
PGND on Bottom Layer "BOTTOM_LAYER_PGND_P165" (solid, remove dead copper, pour order 165): 21 vertices, not listed, extent 9.84,9.84 1437.01,1742.13
3V3 on Bottom Layer "NONET_L-01_P-001" (solid, remove dead copper, pour order 241): 28 vertices, not listed, extent 1200.56,1755.82 1372.35,1938.18
VOUT on Bottom Layer "Bottom Layer-VOUT" (solid, remove dead copper, pour order 164): 47 vertices, not listed, extent 679.13,9.84 1440.48,994.09
GND on Bottom Layer "BOTTOM_LAYER_GND_P239" (solid, remove dead copper, pour order 239): 21 vertices, not listed, extent 1112.21,2175.2 1342.78,2288.91
VIN on Bottom Layer "BOTTOM_LAYER_VIN_P106" (solid, remove dead copper, pour order 106): 41 vertices, not listed, extent 836.62,1919.29 1317.64,2286.6
5V on Bottom Layer "NONET_L-01_P-001" (solid, remove dead copper, pour order 240): 28 vertices, not listed, extent 1295.61,1870.46 1432.85,2007.92
GND on Bottom Layer "NONET_L-01_P-001" (solid, remove dead copper, pour order 0): 37 vertices, not listed, extent 978.63,536.89 1291.57,887
VIN on Bottom Layer "BOTTOM_LAYER_VIN_P234" (solid, remove dead copper, pour order 234): 624.46,1718.61 624.46,1561.13 722.89,1561.13 732.73,1570.97 732.73,1738.3 693.36,1738.3 673.67,1718.61 653.99,1718.61
VIN on Bottom Layer "BOTTOM_LAYER_VIN_P181" (solid, remove dead copper, pour order 181): 934.34,1715 934.34,1557.52 1032.76,1557.52 1042.6,1567.37 1042.6,1734.69 1003.23,1734.69 983.55,1715 963.86,1715
PGND on Bottom Layer "BOTTOM_LAYER_PGND_P175" (solid, remove dead copper, pour order 175): 17 vertices, not listed, extent 748.03,1929.13 964.57,2287.77
5V on Bottom Layer "NONET_L-01_P-001" (solid, remove dead copper, pour order 52): 1164.23,2121.67 1175.18,2110.71 1253.78,2110.71 1265.53,2098.97 1265.53,2070.5 1268.21,2067.82 1326.9,2067.82 1326.9,2157.96 1320.7,2164.17 1123.72,2164.17 1115.92,2156.37 1115.92,2122.96 1117.21,2121.67
VIN on Bottom Layer "BOTTOM_LAYER_VIN_P180" (solid, remove dead copper, pour order 180): 620.08,2145.67 551.18,2076.77 551.18,2047.24 561.02,2037.4 688.98,2037.4 698.82,2047.24 698.82,2106.3 659.45,2145.67
VIN on Bottom Layer "BOTTOM_LAYER_VIN_P179" (solid, remove dead copper, pour order 179): 555.07,2284.01 551.18,2280.13 551.18,2214.57 570.87,2194.88 669.29,2194.88 688.98,2214.57 688.85,2214.7 688.85,2284.99
NetU22_5 on Bottom Layer "NONET_L-01_P-001" (solid, remove dead copper, pour order 279): 1363.33,2047.71 1373.27,2037.77 1423.97,2037.77 1429.58,2043.38 1429.58,2144.54 1421.52,2152.6 1363.33,2152.6
VIN on Bottom Layer "BOTTOM_LAYER_VIN_P236" (solid, remove dead copper, pour order 236): 1259.84,1712.6 1259.84,1555.12 1358.27,1555.12 1368.11,1564.96 1368.11,1732.28 1328.74,1732.28 1309.06,1712.6 1289.37,1712.6
VOUT3 on Bottom Layer "BOTTOM_LAYER_VOUT3_P150" (solid, remove dead copper, pour order 150): 1302.34,827.62 1306.56,823.39 1306.56,779.13 1312.08,773.61 1434.45,773.61 1446.01,785.17 1446.01,994.94 1170.75,994.94 1170.75,827.62
VOUT4 on Bottom Layer "BOTTOM_LAYER_VOUT4_P151" (solid, remove dead copper, pour order 151): 1225.39,378.94 1254.92,378.94 1259.84,383.86 1259.84,413.39 1437.01,413.39 1437.01,206.69 1240.16,206.69 1220.47,226.38 1220.47,374.02
VIN on Bottom Layer "BOTTOM_LAYER_VIN_P235" (solid, remove dead copper, pour order 235): 303.9,1715.84 303.9,1558.36 402.32,1558.36 412.17,1568.21 412.17,1735.53 372.8,1735.53 353.11,1715.84 333.43,1715.84
VIN on Bottom Layer "BOTTOM_LAYER_VIN_P070" (solid, remove dead copper, pour order 70): 1259.84,1712.6 1259.84,1555.12 1358.27,1555.12 1368.11,1564.96 1368.11,1732.28 1328.74,1732.28 1309.06,1712.6 1289.37,1712.6
VOUT1 on Bottom Layer "BOTTOM_LAYER_VOUT1_P163" (solid, remove dead copper, pour order 163): 600.39,983.17 597.51,980.29 597.51,822.08 364.53,822.08 358.03,828.58 358.03,973.69 367.51,983.17
VOUT2 on Bottom Layer "BOTTOM_LAYER_VOUT2_P152" (solid, remove dead copper, pour order 152): 357.17,352.91 361.84,357.58 600.39,357.58 600.39,200.81 365.2,200.81 357.17,208.85
VIN on PWR5 "PWR5_VIN_P262" (solid, remove dead copper, pour order 262): 40 vertices, not listed, extent 291.3,1564.96 1437.01,2283.46
GND on PWR5 "NONET_L-01_P-001" (solid, remove dead copper, pour order 343): 396.75,2278.53 397.98,2277.3 462.25,2277.3 495.55,2244 495.55,2006.14 287.96,1798.55 287.96,1731.13 266.19,1709.36 42.75,1709.36 13,1739.1 13,2276.33 16.25,2279.58 396.75,2279.58
SW2 on PWR5 "PWR5_SW2_P269" (solid, remove dead copper, pour order 269): 32 vertices, not listed, extent 8.1,490.83 697.07,1702.8
SW4 on PWR5 "PWR5_SW4_P261" (solid, remove dead copper, pour order 261): 19 vertices, not listed, extent 884.08,528.45 1435.26,1689.58
SW1 on PWR5 "PWR5_SW1_P268" (solid, remove dead copper, pour order 268): 17 vertices, not listed, extent 9.67,1136.16 346.82,1708.46
VOUT on PWR5 "PWR5_VOUT_P266" (solid, remove dead copper, pour order 266): 678.01,984.25 678.01,118.11 712.16,83.96 997.6,83.96 1002.81,78.74 1002.81,19.68 1012.65,9.84 1406.36,9.84 1435.88,39.37 1435.88,767.72 1130.76,767.72 914.23,984.25
SW3 on PWR5 "PWR5_SW3_P270" (solid, remove dead copper, pour order 270): 23 vertices, not listed, extent 697.07,1132.05 1092.34,1689.58
VOUT2 on PWR5 "PWR5_VOUT2_P265" (solid, remove dead copper, pour order 265): 357.17,352.91 361.84,357.58 624.97,357.58 624.97,200.81 365.2,200.81 357.17,208.85
PGND on PWR5 "NONET_L-01_P-001" (solid, remove dead copper, pour order 267): 19.69,442.91 49.21,472.44 324.8,472.44 344.49,452.76 344.49,206.69 354.33,196.85 616.99,196.85 630.66,183.17 630.59,183.1 630.59,84.86 571.7,25.96 72.46,25.96 19.69,78.74
VOUT4 on PWR5 "PWR5_VOUT4_P264" (solid, remove dead copper, pour order 264): 1240.16,206.69 1220.47,226.38 1220.47,374.02 1259.84,413.39 1437.01,413.39 1437.01,206.69
VOUT1 on PWR5 "PWR5_VOUT1_P263" (solid, remove dead copper, pour order 263): 358.03,973.69 367.51,983.17 616.26,983.17 616.26,832.06 620.61,827.71 614.97,822.08 364.53,822.08 358.03,828.58
VOUT3 on PWR5 "PWR5_VOUT3_P260" (solid, remove dead copper, pour order 260): 1230.32,993.63 1223.32,1000.63 1172.07,1000.63 1158,986.56 1158,841.77 1172.43,827.34 1448.2,827.34 1446.85,828.69 1446.85,994.75 1230.32,994.75
PGND on Top Layer "TOP_LAYER_PGND_P169" (solid, remove dead copper, pour order 169): 374.02,2194.88 403.54,2224.41 954.73,2224.41 964.57,2214.57 964.57,2125.98 935.04,2096.46 492.13,2096.46 472.44,2076.77 383.86,2076.77 374.02,2086.61 374.02,2185.04
VIN on Top Layer "TOP_LAYER_VIN_P170" (solid, remove dead copper, pour order 170): 964.57,2096.46 501.97,2096.46 492.13,2086.61 492.13,2037.4 501.97,2027.56 1083.62,2027.56 1116.2,2060.14 1116.2,2292.1 492.13,2293.31 492.13,2244.09 511.81,2224.41 964.57,2224.41
5V on Top Layer "NONET_L-01_P-001" (solid, remove dead copper, pour order 276): 1167.27,2151.44 1171.64,2155.81 1317.34,2155.81 1324.68,2148.46 1324.68,2088.91 1302.34,2066.57 1266.72,2066.57 1223.98,2109.31 1175.36,2109.31 1167.27,2117.4
PGND on Top Layer "TOP_LAYER_PGND_P140" (solid, remove dead copper, pour order 140): 38 vertices, not listed, extent 9.84,9.84 1437.01,1446.85
PGND on Top Layer "TOP_LAYER_PGND_P147" (solid, remove dead copper, pour order 147): 423.23,1584.65 423.23,1761.81 442.91,1761.81 462.6,1742.13 462.6,1584.65
VIN on Top Layer "NONET_L-01_P-001" (solid, remove dead copper, pour order 233): 1251.33,2051.24 1261.38,2061.29 1308.55,2061.29 1317.76,2052.08 1317.76,2041.86 1313.3,2037.41 1308.1,2037.41 1304.49,2033.79 1304.49,2012.11 1302.2,2009.82 1263.02,2009.82 1251.33,2021.51
GND on Top Layer "TOP_LAYER_GND_P171" (solid, remove dead copper, pour order 171): 9.84,2293.31 9.84,1938.98 334.65,1938.98 334.65,2293.31
5V on Top Layer "NONET_L-01_P-001" (solid, remove dead copper, pour order 280): 22 vertices, not listed, extent 1083.62,2124.64 1167.27,2278.83
VOUT on Top Layer "Top Layer-VOUT" (solid, remove dead copper, pour order 57): 42 vertices, not listed, extent 678.33,13.11 1437.01,982.28
SW2 on Top Layer "NONET_L-01_P-001" (solid, remove dead copper, pour order 4): 216.58,679.65 228.03,668.2 228.03,511.54 215.07,498.57 10.95,498.57 4,505.52 4,677.65 6,679.65
SW4 on Top Layer "NONET_L-01_P-001" (solid, remove dead copper, pour order 284): 889.37,521.87 889.37,520.14 894.86,514.65 1088.79,514.65 1097.51,523.36 1097.51,671.1 1086.71,681.91 894.35,681.91 889.23,676.79 889.23,657.12
SW3 on Top Layer "NONET_L-01_P-001" (solid, remove dead copper, pour order 34): 1085.75,1130.82 1094.55,1139.62 1094.55,1286.04 1083.76,1296.83 883.37,1296.83 880.77,1294.23 880.77,1137.46 887.4,1130.82
5V on Top Layer "NONET_L-01_P-001" (solid, remove dead copper, pour order 277): 23 vertices, not listed, extent 1296.31,1869 1440.54,1964.77
3V3 on Top Layer "NONET_L-01_P-001" (solid, remove dead copper, pour order 283): 1308.31,1876.39 1363.13,1876.39 1371.08,1868.45 1371.08,1860.36 1380.13,1851.31 1380.13,1815.18 1377.83,1812.88 1351.15,1812.88 1347.17,1816.85 1347.17,1833.23 1337.55,1842.86 1305.85,1842.86 1302.2,1846.52 1302.2,1875.2 1303.46,1876.46
GND on Top Layer "TOP_LAYER_GND_P193" (solid, remove dead copper, pour order 193): 265.75,1870.08 305.12,1870.08 305.12,1889.76 265.75,1889.76
VOUT2 on Top Layer "TOP_LAYER_VOUT2_P035" (solid, remove dead copper, pour order 35): 692.54,287.65 692.54,155.31 689.79,152.55 638.27,152.55 630.66,160.16 630.66,188.41 621.23,197.85 368.17,197.85 357.17,208.85 357.17,352.91 366.1,361.84 566.07,361.84 602.93,324.98 655.21,324.98
GND on Top Layer "NONET_L-01_P-001" (solid, remove dead copper, pour order 282): 1178.86,2221.03 1167.27,2209.45 1167.27,2190.71 1175.88,2182.1 1220.46,2182.1 1230.23,2191.88 1230.23,2257.75 1211.89,2276.09 1181.42,2276.09 1178.86,2273.53
GND on Top Layer "NONET_L-01_P-001" (solid, remove dead copper, pour order 231): 1343.83,1978.58 1345.64,1976.77 1376.32,1976.77 1379.58,1979.98 1379.58,2004.63 1386.58,2011.63 1390.79,2011.63 1391.53,2012.33 1391.53,2151.08 1381.15,2161.46 1336.22,2161.46 1333.93,2158.3 1333.93,2014.15 1343.83,2004.25
VIN on Top Layer "TOP_LAYER_VIN_P192" (solid, remove dead copper, pour order 192): 295.28,1564.96 305.12,1555.12 374.02,1555.12 413.39,1594.49 413.39,1742.13 383.86,1742.13 374.02,1732.28 305.12,1732.28 295.28,1722.44
VIN on Top Layer "TOP_LAYER_VIN_P182" (solid, remove dead copper, pour order 182): 627.4,1710.73 627.4,1563.81 636.09,1555.12 708.66,1555.12 728.35,1574.8 728.35,1732.28 639.76,1732.28 629.92,1722.44 629.92,1712.6
3V3 on Top Layer "NONET_L-01_P-001" (solid, remove dead copper, pour order 281): 418.31,2230.86 426.31,2222.86 467.39,2222.86 486.86,2242.33 486.86,2288.29 479.4,2295.75 422.96,2295.75 418.31,2291.1
SW2 on Top Layer "TOP_LAYER_SW2_P145" (solid, remove dead copper, pour order 145): 659.45,1466.54 669.29,1476.38 669.29,1545.28 629.92,1545.28 610.24,1564.96 610.24,1712.6 521.65,1712.6 521.65,1555.12 511.81,1545.28 511.81,1476.38 521.65,1466.54
PGND on Top Layer "TOP_LAYER_PGND_P149" (solid, remove dead copper, pour order 149): 1072.56,1571.83 1072.56,1739.15 1102.08,1739.15 1111.93,1729.31 1111.93,1571.83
